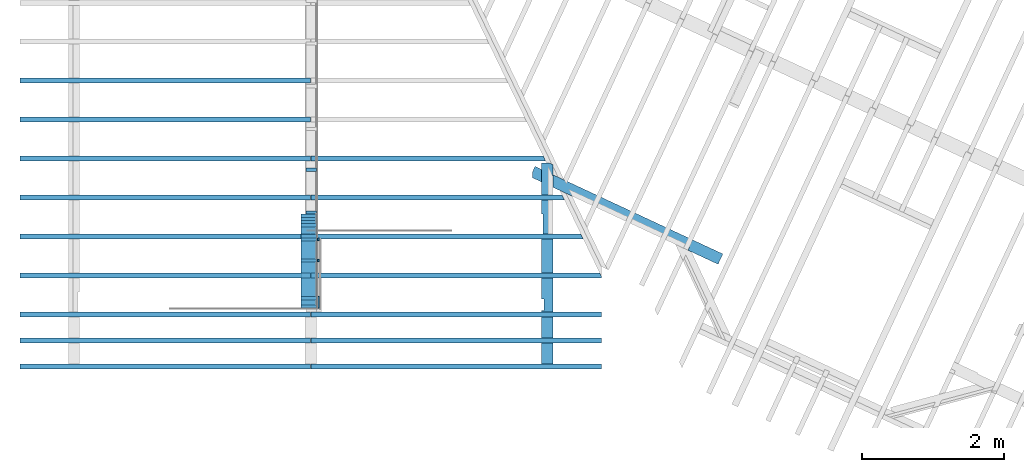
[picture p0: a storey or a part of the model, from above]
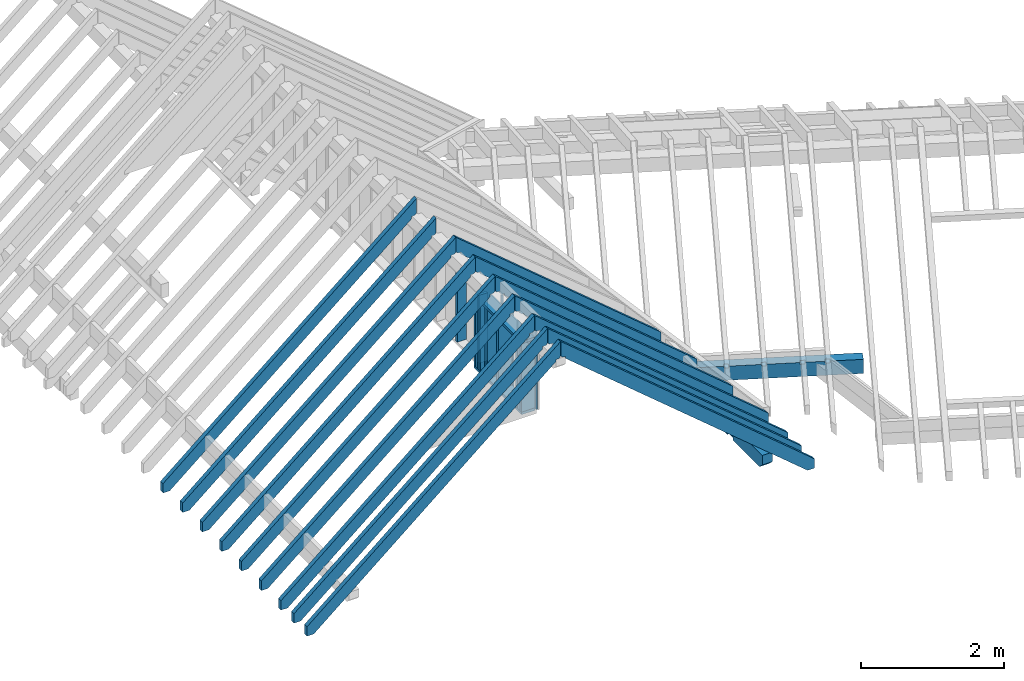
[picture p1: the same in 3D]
Properties of the parts of a building model (IFC2X3), part 1 of 4

# File
Description: ViewDefinition [CoordinationView_V2.0]
File name: Export_V2
Time: 2022-12-03T16:46:10
Made in: cadwork

# IfcSite
RefElevation: 0 m

# IfcBuildingStorey (4)
In: Building 1
Elevation: 0 m
Name
Comble et couverture
Dalle
Premier Etage
Rez de chaussée

# IfcBeam (12)
Material: NH II
BaseQuantities - GrossWeight: 0; NetWeight: 0
Pset cadwork 3d - Group: Charpente
Name | In | Width (m) | Height (m) | Length (m) | CrossSectionArea (m2) | OuterfaceArea (m2) | TotalSurfaceArea (m2) | GrossVolume (m3) | NetVolume (m3) | SubGroup | Prod_Nb
Blochet | Premier Etage | 0.092 | 0.192 | 1.5533 | 3.3915 | 0.8393 | 0.8747 | 0.0274 | 0.0259 | F01 | 1504
Solive balcon | Rez de chaussée | 0.092 | 0.192 | 1.0028 | 3.3915 | 0.5696 | 0.6049 | 0.0182 | 0.0177 | Balcon | 1508
2 x Solive balcon | Rez de chaussée | 0.092 | 0.192 | 2.862 | 3.3915 | 1.6256 | 1.6609 | 0.0515 | 0.0506 | Balcon | 1509
Solive balcon | Rez de chaussée | 0.2 | 0.2 | 1.1768 | 8 | 0.9042 | 0.9842 | 0.0482 | 0.0435 | Balcon | 1510
Poteau | Rez de chaussée | 0.2 | 0.2 | 2.605 | 8 | 2.084 | 2.164 | 0.106 | 0.1042 | Balcon | 1507
Blochet | Premier Etage | 0.092 | 0.192 | 1.5533 | 3.3915 | 0.8367 | 0.872 | 0.0274 | 0.0257 | F01 | 1504
Poteau | Rez de chaussée | 0.2 | 0.2 | 2.3756 | 8 | 1.8567 | 1.9367 | 0.095 | 0.088 | Ferme Garage | 1520
Solive balcon | Rez de chaussée | 0.2 | 0.2 | 3.656 | 8 | 2.8826 | 2.9626 | 0.1462 | 0.1422 | Balcon | 1511
Poteau | Premier Etage | 0.1 | 0.2 | 1.6441 | 4 | 0.9702 | 1.0102 | 0.0329 | 0.0319 | F01 | 1505
Poinçon | Rez de chaussée | 0.16 | 0.16 | 2.7152 | 4.096 | 1.7108 | 1.762 | 0.0695 | 0.0674 | Ferme Garage | 1518
Poteau | Rez de chaussée | 0.2 | 0.2 | 2.3756 | 8 | 1.8567 | 1.9367 | 0.095 | 0.088 | Ferme Garage | 1519

# IfcBuildingElementProxy (122)
Material: NH II
BaseQuantities - Width: 0 m; CrossSectionArea: 0 m2; GrossVolume: 0 m3; GrossWeight: 0; NetWeight: 0
Name | In | Height (m) | Length (m) | OuterfaceArea (m2) = TotalSurfaceArea (m2) | NetVolume (m3) | Group
Surf_doubl_mur_Etage | Premier Etage | 2.894 | 3.88 | 7.715 | 0.0077 | MURS ETAGE
Surf_doubl_mur_RDC | Rez de chaussée | 1.8334 | 0.28 | 0.5133 | 0.0005 | MURS RDC
Surf_doubl_mur_RDC | Rez de chaussée | 0.9327 | 0.152 | 0.1418 | 0.0001 | MURS RDC
Surf_doubl_mur_RDC | Rez de chaussée | 0.18 | 1.1 | 0.198 | 0.0002 | MURS RDC
Surf_doubl_refend_RDC | Rez de chaussée | 1.7023 | 2.8 | 4.7665 | 0.0048 | MURS RDC
Surf_rampant isolé | Comble et couverture | 4.8508 | 4.4463 | 16.2012 | 0.0162
Surf_doubl_mur_RDC | Rez de chaussée | 2.894 | 2.248 | 4.513 | 0.0045 | MURS RDC
Surf_doubl_mur_RDC | Rez de chaussée | 3.2344 | 2.248 | 3.1855 | 0.0032 | MURS RDC
Surf_plancher | Premier Etage | 9.0638 | 14.1239 | 82.3637 | 0.0824 | Plancher étage
Surf_doubl_mur_RDC | Rez de chaussée | 0.8282 | 3.6116 | 2.7932 | 0.0028 | MURS RDC
Surf_doubl_mur_RDC | Rez de chaussée | 5.0771 | 2.8 | 13.4331 | 0.0134 | MURS RDC
Surf_doubl_mur_RDC | Rez de chaussée | 0.4294 | 2.8 | 1.2023 | 0.0012 | MURS RDC
Surf_doubl_refend_RDC | Rez de chaussée | 1.5736 | 2.8 | 4.4061 | 0.0044 | MURS RDC
2 x Surf_doubl_refend_RDC | Rez de chaussée | 2.6107 | 2.8 | 7.3098 | 0.0073 | MURS RDC
Surf_doubl_refend_RDC | Rez de chaussée | 3.0682 | 2.8 | 8.5909 | 0.0086 | MURS RDC
Surf_rampant isolé | Comble et couverture | 4.851 | 4.0712 | 12.7698 | 0.0128
Surf_doubl_mur_Etage | Premier Etage | 5.1796 | 2.7561 | 10.3865 | 0.0104 | MURS ETAGE
Surf_doubl_mur_RDC | Rez de chaussée | 1.2715 | 0.325 | 0.4132 | 0.0004 | MURS RDC
Surf_doubl_mur_RDC | Rez de chaussée | 1.6903 | 0.152 | 0.2569 | 0.0003 | MURS RDC
Surf_doubl_mur_RDC | Rez de chaussée | 3.171 | 2.8 | 7.1393 | 0.0071 | MURS RDC
Surf_doubl_mur_Etage | Premier Etage | 1.2715 | 1.1631 | 1.1788 | 0.0012 | MURS ETAGE
Surf_doubl_mur_RDC | Rez de chaussée | 0.552 | 1.5291 | 0.7561 | 0.0008 | MURS RDC
Surf_doubl_mur_Etage | Premier Etage | 9.0512 | 1.3586 | 12.2969 | 0.0123 | MURS ETAGE
Surf_doubl_mur_RDC | Rez de chaussée | 2.2245 | 2.248 | 3.7389 | 0.0037 | MURS RDC
surf_placo | Premier Etage | 1.9838 | 2.3904 | 3.7124 | 0.0037 | MURS ETAGE
2 x Surf_doubl_mur_RDC | Rez de chaussée | 0.1385 | 0.4 | 0.0554 | 0.0001 | MURS RDC
Surf_doubl_mur_RDC | Rez de chaussée | 0.3275 | 1.1 | 0.3602 | 0.0004 | MURS RDC
2 x Surf_doubl_mur_RDC | Rez de chaussée | 0.0844 | 1.923 | 0.1624 | 0.0002 | MURS RDC
Surf_doubl_mur_RDC | Rez de chaussée | 4.519 | 0.6723 | 3.0382 | 0.003 | MURS RDC
Surf_rampant isolé | Comble et couverture | 3.1634 | 3.2996 | 8.223 | 0.0082
2 x Surf_doubl_refend_RDC | Rez de chaussée | 1.3947 | 2.8 | 3.9052 | 0.0039 | MURS RDC
2 x Surf_doubl_mur_RDC | Rez de chaussée | 0.1385 | 1.923 | 0.2664 | 0.0003 | MURS RDC
surf_placo | Premier Etage | 1.9838 | 3.9546 | 7.845 | 0.0078 | MURS ETAGE
2 x Surf_doubl_refend_RDC | Rez de chaussée | 0.277 | 2.8 | 0.7756 | 0.0008 | MURS RDC
Surf_doubl_mur_RDC | Rez de chaussée | 2.3298 | 1.923 | 4.4802 | 0.0045 | MURS RDC
Surf_doubl_mur_RDC | Rez de chaussée | 0.8282 | 0.152 | 0.1259 | 0.0001 | MURS RDC
Surf_rampant isolé | Comble et couverture | 4.3185 | 2.4595 | 8.3437 | 0.0083
Surf_doubl_mur_RDC | Rez de chaussée | 0.18 | 0.325 | 0.0585 | 0.0001 | MURS RDC
Surf_doubl_mur_RDC | Rez de chaussée | 0.7186 | 2.248 | 1.062 | 0.0011 | MURS RDC
Surf_doubl_mur_RDC | Rez de chaussée | 2.2947 | 0.152 | 0.3488 | 0.0003 | MURS RDC
Surf_doubl_refend_RDC | Rez de chaussée | 1.0276 | 2.8 | 2.8773 | 0.0029 | MURS RDC
Surf_doubl_mur_RDC | Rez de chaussée | 1.0637 | 3.6854 | 3.5148 | 0.0035 | MURS RDC
Surf_doubl_mur_RDC | Rez de chaussée | 1.9672 | 0.325 | 0.6394 | 0.0006 | MURS RDC
Surf_doubl_mur_RDC | Rez de chaussée | 1.7489 | 1.109 | 0.28 | 0.0003 | MURS RDC
Surf_doubl_mur_RDC | Rez de chaussée | 0.9327 | 0.325 | 0.3031 | 0.0003 | MURS RDC
Surf_doubl_mur_RDC | Rez de chaussée | 0.18 | 2.323 | 0.418 | 0.0004 | MURS RDC
Surf_doubl_mur_RDC | Rez de chaussée | 0.4632 | 1.2104 | 0.5606 | 0.0006 | MURS RDC
Surf_doubl_mur_RDC | Rez de chaussée | 0.2762 | 4.0116 | 1.0861 | 0.0011 | MURS RDC
Surf_doubl_mur_RDC | Rez de chaussée | 1.2271 | 3.5334 | 3.2899 | 0.0033 | MURS RDC
Surf_doubl_mur_RDC | Rez de chaussée | 0.3275 | 0.325 | 0.1064 | 0.0001 | MURS RDC
surf_placo | Premier Etage | 3.058 | 3.9546 | 7.4298 | 0.0074 | MURS ETAGE
surf_placo | Premier Etage | 3.058 | 3.9546 | 6.4139 | 0.0064 | MURS ETAGE
2 x Surf_doubl_mur_RDC | Rez de chaussée | 0.0844 | 0.4 | 0.0338 | 0 | MURS RDC
Surf_doubl_mur_RDC | Rez de chaussée | 1.1008 | 2.248 | 2.4747 | 0.0025 | MURS RDC
Surf_doubl_mur_RDC | Rez de chaussée | 0.3384 | 0.325 | 0.11 | 0.0001 | MURS RDC
Surf_doubl_mur_RDC | Rez de chaussée | 0.9492 | 1.923 | 1.8253 | 0.0018 | MURS RDC
Surf_doubl_mur_RDC | Rez de chaussée | 0.4632 | 1.923 | 0.8907 | 0.0009 | MURS RDC
Surf_rampant isolé | Comble et couverture | 7.908 | 4.3782 | 32.1627 | 0.0322
Surf_doubl_mur_RDC | Rez de chaussée | 0.9327 | 1.923 | 1.7936 | 0.0018 | MURS RDC
Surf_doubl_mur_RDC | Rez de chaussée | 0.552 | 1.923 | 1.0615 | 0.0011 | MURS RDC
Surf_doubl_mur_RDC | Rez de chaussée | 1.5214 | 2.248 | 2.775 | 0.0028 | MURS RDC
Surf_doubl_mur_RDC | Rez de chaussée | 0.1515 | 1.923 | 0.2914 | 0.0003 | MURS RDC
Surf_doubl_mur_RDC | Rez de chaussée | 3.2494 | 2.248 | 6.2115 | 0.0062 | MURS RDC
Surf_doubl_mur_RDC | Rez de chaussée | 0.2868 | 2.248 | 0.4353 | 0.0004 | MURS RDC
Surf_doubl_mur_RDC | Rez de chaussée | 3.26 | 2.248 | 2.9849 | 0.003 | MURS RDC
Surf_doubl_mur_RDC | Rez de chaussée | 0.3272 | 1.923 | 0.6293 | 0.0006 | MURS RDC
Surf_doubl_refend_RDC | Rez de chaussée | 0.2832 | 2.8 | 0.793 | 0.0008 | MURS RDC
2 x Surf_doubl_refend_RDC | Rez de chaussée | 2.4835 | 2.8 | 6.9539 | 0.007 | MURS RDC
Surf_doubl_refend_RDC | Rez de chaussée | 3.171 | 2.8 | 8.8788 | 0.0089 | MURS RDC
Surf_doubl_mur_RDC | Rez de chaussée | 1.9188 | 2.8 | 4.2796 | 0.0043 | MURS RDC
Surf_doubl_refend_RDC | Rez de chaussée | 2.1486 | 2.8 | 6.016 | 0.006 | MURS RDC
Surf_doubl_mur_RDC | Rez de chaussée | 0.0844 | 0.278 | 0.0215 | 0 | MURS RDC
Surf_doubl_mur_RDC | Rez de chaussée | 0.1385 | 1.7421 | 0.2362 | 0.0002 | MURS RDC
Surf_doubl_mur_RDC | Rez de chaussée | 1.8334 | 1.1548 | 0.2936 | 0.0003 | MURS RDC
Surf_doubl_mur_RDC | Rez de chaussée | 0.0844 | 0.2059 | 0.0135 | 0 | MURS RDC
Surf_doubl_mur_RDC | Rez de chaussée | 0.1385 | 0.2353 | 0.0222 | 0 | MURS RDC
Surf_rampant isolé | Comble et couverture | 4.4009 | 4.0712 | 12.4025 | 0.0124
2 x Surf_doubl_refend_RDC | Rez de chaussée | 0.202 | 2.8 | 0.5656 | 0.0006 | MURS RDC
Surf_doubl_mur_RDC | Rez de chaussée | 4.519 | 0.152 | 0.6869 | 0.0007 | MURS RDC
2 x Surf_doubl_mur_RDC | Rez de chaussée | 1.9719 | 0.152 | 0.2997 | 0.0003 | MURS RDC
Surf_doubl_mur_RDC | Rez de chaussée | 0.2606 | 2.9953 | 0.7804 | 0.0008 | MURS RDC
Surf_rampant isolé | Comble et couverture | 2.9828 | 2.8104 | 2.5966 | 0.0026
Surf_rampant isolé | Comble et couverture | 1.8478 | 2.8105 | 2.5966 | 0.0026
2 x Surf_doubl_refend_RDC | Rez de chaussée | 1.9838 | 2.8 | 5.5546 | 0.0056 | MURS RDC
Surf_doubl_refend_RDC | Rez de chaussée | 0.4124 | 2.8 | 1.1546 | 0.0012 | MURS RDC
Surf_doubl_mur_Etage | Premier Etage | 2.2947 | 0.6912 | 1.5861 | 0.0016 | MURS ETAGE
Surf_doubl_mur_Etage | Premier Etage | 1.5494 | 1.2662 | 1.5164 | 0.0015 | MURS ETAGE
Surf_doubl_mur_Etage | Premier Etage | 2.2245 | 1.2662 | 2.8166 | 0.0028 | MURS ETAGE
Surf_doubl_mur_Etage | Premier Etage | 0.2868 | 1.4515 | 0.3818 | 0.0004 | MURS ETAGE
Surf_doubl_mur_Etage | Premier Etage | 0.1764 | 1.4016 | 0.2434 | 0.0002 | MURS ETAGE
Surf_doubl_mur_Etage | Premier Etage | 6.229 | 4.0335 | 16.9842 | 0.017 | MURS ETAGE
Surf_rampant isolé | Comble et couverture | 7.908 | 4.554 | 22.9358 | 0.0229
2 x Surf_doubl_refend_Etage | Premier Etage | 3.103 | 3.9546 | 7.5511 | 0.0076 | MURS ETAGE
Surf_doubl_refend_Etage | Premier Etage | 6.2532 | 3.9546 | 21.217 | 0.0212 | MURS ETAGE
Surf_doubl_mur_Etage | Premier Etage | 7.354 | 1.4517 | 10.6756 | 0.0107 | MURS ETAGE
Surf_doubl_refend_Etage | Premier Etage | 6.2532 | 3.943 | 21.1444 | 0.0211 | MURS ETAGE
Surf_doubl_mur_Etage | Premier Etage | 0.7186 | 1.4515 | 1.0431 | 0.001 | MURS ETAGE
Surf_doubl_mur_Etage | Premier Etage | 3.26 | 4.0335 | 9.1627 | 0.0092 | MURS ETAGE
Surf_doubl_mur_Etage | Premier Etage | 1.1008 | 3.88 | 4.2712 | 0.0043 | MURS ETAGE
Surf_doubl_refend_Etage | Premier Etage | 5.001 | 2.7561 | 8.4138 | 0.0084 | MURS ETAGE
Surf_doubl_refend_Etage | Premier Etage | 5.5345 | 2.7561 | 9.4741 | 0.0095 | MURS ETAGE
Surf_rampant isolé | Comble et couverture | 5.3117 | 2.4595 | 10.7866 | 0.0108
Surf_doubl_refend_RDC | Rez de chaussée | 3.7651 | 2.8 | 10.5424 | 0.0105 | MURS RDC
Surf_doubl_refend_RDC | Rez de chaussée | 7.0648 | 2.8 | 19.7815 | 0.0198 | MURS RDC
Surf_doubl_mur_RDC | Rez de chaussée | 2.1569 | 2.323 | 5.0105 | 0.005 | MURS RDC
Surf_doubl_mur_RDC | Rez de chaussée | 0.0371 | 2.323 | 0.0863 | 0.0001 | MURS RDC
Surf_doubl_mur_RDC | Rez de chaussée | 1.2715 | 0.152 | 0.1933 | 0.0002 | MURS RDC
Surf_doubl_mur_RDC | Rez de chaussée | 1.12 | 0.152 | 0.1702 | 0.0002 | MURS RDC
Surf_doubl_mur_RDC | Rez de chaussée | 2.4175 | 0.152 | 0.3675 | 0.0004 | MURS RDC
Surf_doubl_mur_RDC | Rez de chaussée | 0.0371 | 0.152 | 0.0056 | 0 | MURS RDC

# IfcColumn, Poteau
In: Premier Etage
Material: NH II
BaseQuantities - Width: 0.2 m; Height: 0.2 m; Length: 1.4178 m; CrossSectionArea: 8 m2; OuterfaceArea: 1.0491 m2; TotalSurfaceArea: 1.1291 m2; GrossVolume: 0.0585 m3; NetVolume: 0.0493 m3; GrossWeight: 0; NetWeight: 0
Pset cadwork 3d - Group: Charpente; SubGroup: F01; Prod_Nb: 1506

# IfcCurtainWall (113)
Name | In | Material
71 x Escalier | Rez de chaussée | NH II
20 x Pare-pluie | Rez de chaussée | pare-pluie
18 x Pare-pluie | Premier Etage | pare-pluie
4 x Pare-pluie | Comble et couverture | pare-pluie

# IfcFooting (3)
Material: Béton
BaseQuantities - Height: 0.2 m
Pset cadwork 3d - Group: Maçonnerie
Name | In | Width (m) | Length (m) | CrossSectionArea (m2) | OuterfaceArea (m2) | TotalSurfaceArea (m2) | GrossVolume (m3) | NetVolume (m3) | GrossWeight | NetWeight
Dalle | Rez de chaussée | 6.28 | 5.3065 | 251.2 | 68.7722 | 71.2842 | 6.665 | 6.665 | 159.959 | 159.959 | Pset cadwork 3d - SubGroup: Garage
Dalle | Dalle | 18.5542 | 9.5894 | 742.167 | 237.702 | 245.124 | 35.5846 | 23.4288 | 854.03 | 562.292
Dalle | Rez de chaussée | 0.4 | 0.4 | 16 | 0.48 | 0.64 | 0.032 | 0.032 | 0.768 | 0.768

# IfcMember (1988)
Name | In | Material | Width (m) | Height (m) | Length (m) | CrossSectionArea (m2) | OuterfaceArea (m2) | TotalSurfaceArea (m2) | GrossVolume (m3) | NetVolume (m3) | GrossWeight | NetWeight | SKU | Group | SubGroup | Prod_Nb
5 x latte 27/40 | Premier Etage | Epicéa C24 | 0.04 | 0.024 | 0.6979 | 0.023 | 0.0893 | 0.0912 | 0.0007 | 0.0007 | 0.0028 | 0.0028 | 0 | MURS ETAGE | OB125 | 754
2 x Lisse basse | Premier Etage | Epicéa C24 | 0.045 | 0.145 | 2.1858 | 0.9461 | 0.8306 | 0.8436 | 0.0143 | 0.0143 | 0.0599 | 0.0599 | 0 | Plancher étage | ETA | 27
2 x Chevron | Comble et couverture | NH II | 0.07 | 0.192 | 5.4036 | 2.5805 | 2.7812 | 2.8081 | 0.0726 | 0.0712 | 0 | 0 |  | Charpente | Chevrons | 2091
7 x Montant | Premier Etage | Epicéa C24 | 0.045 | 0.22 | 0.5729 | 2.178 | 0.3036 | 0.3234 | 0.0057 | 0.0057 | 0.0238 | 0.0238 | 0 | MURS ETAGE | OB125 | 528
17 x latte 27/40 | Rez de chaussée | Epicéa C24 | 0.04 | 0.024 | 2.698 | 0.023 | 0.3453 | 0.3473 | 0.0026 | 0.0026 | 0.0109 | 0.0109 | 0 | MURS RDC | OB01 | 679
Solive | Premier Etage | NH II | 0.092 | 0.22 | 8.4685 | 4.4528 | 5.273 | 5.3135 | 0.1724 | 0.171 | 0 | 0 |  | Plancher étage | Solivage_220 | 1064
9 x Montant | Premier Etage | Epicéa C24 | 0.045 | 0.22 | 2.6405 | 2.178 | 1.3994 | 1.4192 | 0.0261 | 0.0261 | 0.1098 | 0.1098 | 0 | MURS ETAGE | OB13 | 248
latte 27/40 | Premier Etage | Epicéa C24 | 0.04 | 0.024 | 1.0505 | 0.023 | 0.1345 | 0.1364 | 0.001 | 0.001 | 0.0042 | 0.0042 | 0 | MURS COMBLE | OB12 | 612
15 x Montant | Premier Etage | Epicéa C24 | 0.045 | 0.145 | 2.6405 | 0.9461 | 1.0034 | 1.0164 | 0.0172 | 0.0172 | 0.0724 | 0.0724 | 0 | MURS ETAGE | OB129 | 252
4 x Couvre joint | Rez de chaussée | NH II | 0.027 | 0.105 | 3.4036 | 0.2977 | 0.8707 | 0.8764 | 0.0096 | 0.0092 | 0 | 0 |  | Couvre-joint
Panne | Comble et couverture | NH II | 0.16 | 0.2 | 5.1216 | 6.4 | 3.6585 | 3.7225 | 0.1639 | 0.1609 | 0 | 0 |  | Charpente | Toiture mezzanine | 1530
5 x Montant | Rez de chaussée | Epicéa C24 | 0.045 | 0.22 | 2.478 | 2.178 | 1.3133 | 1.3331 | 0.0245 | 0.0245 | 0.103 | 0.103 | 0 | MURS RDC | OB04 | 85
9 x Montant | Rez de chaussée | Epicéa C24 | 0.045 | 0.22 | 2.45 | 2.178 | 1.2985 | 1.3183 | 0.0243 | 0.0243 | 0.1019 | 0.1019 | 0 | MURS RDC | OB010 | 347
5 x latte 27/40 | Rez de chaussée | Epicéa C24 | 0.04 | 0.024 | 0.443 | 0.023 | 0.0567 | 0.0586 | 0.0004 | 0.0004 | 0.0018 | 0.0018 | 0 | MURS RDC | OB020 | 630
Montant | Premier Etage | Epicéa C24 | 0.045 | 0.145 | 0.87 | 0.9461 | 0.3306 | 0.3436 | 0.0057 | 0.0057 | 0.0238 | 0.0238 | 0 | MURS ETAGE | OB131 | 499
24 x Montant | Rez de chaussée | Epicéa C24 | 0.045 | 0.22 | 2.478 | 2.178 | 1.3133 | 1.3331 | 0.0245 | 0.0245 | 0.103 | 0.103 | 0 | MURS RDC | OB020 | 153
5 x Montant | Premier Etage | Epicéa C24 | 0.045 | 0.22 | 0.2045 | 2.178 | 0.1084 | 0.1282 | 0.002 | 0.002 | 0.0085 | 0.0085 | 0 | MURS ETAGE | OB14 | 89
9 x Montant | Rez de chaussée | Epicéa C24 | 0.045 | 0.22 | 0.73 | 2.178 | 0.3869 | 0.4067 | 0.0072 | 0.0072 | 0.0304 | 0.0304 | 0 | MURS RDC | OB01 | 260
23 x Montant | Rez de chaussée | Epicéa C24 | 0.045 | 0.22 | 2.478 | 2.178 | 1.3133 | 1.3331 | 0.0245 | 0.0245 | 0.103 | 0.103 | 0 | MURS RDC | OB01 | 262
Montant | Premier Etage | Epicéa C24 | 0.045 | 0.22 | 0.7144 | 2.178 | 0.3679 | 0.3877 | 0.0071 | 0.0068 | 0.0297 | 0.0286 | 0 | MURS ETAGE | OB124 | 518
7 x Montant | Rez de chaussée | Epicéa C24 | 0.045 | 0.145 | 2.43 | 0.9461 | 0.9234 | 0.9364 | 0.0159 | 0.0159 | 0.0666 | 0.0666 | 0 | MURS RDC | OB025 | 202
Montant | Rez de chaussée | Epicéa C24 | 0.045 | 0.1286 | 2.665 | 0.7445 | 0.8887 | 0.9003 | 0.0154 | 0.0144 | 0.0648 | 0.0607 | 0 | MURS RDC | OB013 | 429
Montant | Premier Etage | Epicéa C24 | 0.045 | 0.22 | 0.9874 | 2.178 | 0.5164 | 0.5362 | 0.0098 | 0.0096 | 0.0411 | 0.0403 | 0 | MURS COMBLE | OB12 | 75
2 x latte 27/40 | Premier Etage | Epicéa C24 | 0.04 | 0.024 | 1.1361 | 0.023 | 0.1454 | 0.1473 | 0.0011 | 0.0011 | 0.0046 | 0.0046 | 0 | MURS ETAGE | OB123 | 745
5 x Montant | Rez de chaussée | Epicéa C24 | 0.045 | 0.22 | 0.24 | 2.178 | 0.1272 | 0.147 | 0.0024 | 0.0024 | 0.01 | 0.01 | 0 | MURS RDC | OB08 | 309
Chevron | Comble et couverture | NH II | 0.07 | 0.192 | 2.3318 | 2.5805 | 1.1547 | 1.1816 | 0.0313 | 0.0293 | 0 | 0 |  | Charpente | Chevrons | 2071
Montant | Rez de chaussée | Epicéa C24 | 0.045 | 0.178 | 2.935 | 1.4263 | 1.2603 | 1.2763 | 0.0235 | 0.0221 | 0.0988 | 0.0929 | 0 | MURS RDC | OB014 | 454
Montant | Premier Etage | Epicéa C24 | 0.045 | 0.22 | 1.4003 | 2.178 | 0.7352 | 0.755 | 0.0139 | 0.0137 | 0.0582 | 0.0574 | 0 | MURS COMBLE | OB12 | 76
7 x Montant | Rez de chaussée | Epicéa C24 | 0.045 | 0.22 | 2.67 | 2.178 | 1.4151 | 1.4349 | 0.0264 | 0.0264 | 0.111 | 0.111 | 0 | MURS RDC | OB08 | 314
2 x Enrayure | Dalle | NH II | 0.188 | 0.5 | 2.2539 | 47 | 2.9905 | 3.1785 | 0.2119 | 0.2025 | 0 | 0 |  | Maçonnerie
10 x Montant | Premier Etage | Epicéa C24 | 0.045 | 0.145 | 2.5593 | 0.9461 | 0.9725 | 0.9856 | 0.0167 | 0.0167 | 0.0701 | 0.0701 | 0 | MURS ETAGE | OB128 | 132
4 x latte 27/40 | Rez de chaussée | Epicéa C24 | 0.04 | 0.024 | 2.67 | 0.023 | 0.3418 | 0.3437 | 0.0026 | 0.0026 | 0.0108 | 0.0108 | 0 | MURS RDC | OB07 | 687
9 x Montant | Rez de chaussée | Epicéa C24 | 0.045 | 0.22 | 0.417 | 2.178 | 0.221 | 0.2408 | 0.0041 | 0.0041 | 0.0173 | 0.0173 | 0 | MURS RDC | OB01 | 259
2 x Montant | Comble et couverture | Epicéa C24 | 0.045 | 0.22 | 1.3208 | 2.178 | 0.7 | 0.7198 | 0.0131 | 0.0131 | 0.0549 | 0.0549 | 0 | MURS COMBLE | OB13 | 255
3 x Montant | Premier Etage | Epicéa C24 | 0.045 | 0.145 | 0.1783 | 0.9461 | 0.0678 | 0.0808 | 0.0012 | 0.0012 | 0.0049 | 0.0049 | 0 | MURS ETAGE | OB131 | 493
4 x Solive | Premier Etage | NH II | 0.07 | 0.192 | 0.3809 | 2.5805 | 0.1996 | 0.2265 | 0.0053 | 0.0051 | 0 | 0 |  | Plancher étage | Solivage_192 | 1022
3 x Montant | Rez de chaussée | Epicéa C24 | 0.045 | 0.145 | 2.45 | 0.9461 | 0.931 | 0.944 | 0.016 | 0.016 | 0.0671 | 0.0671 | 0 | MURS RDC | OB024 | 536
contre poutre | Premier Etage | NH II | 0.027 | 0.165 | 0.8587 | 0.7351 | 0.2944 | 0.3034 | 0.0038 | 0.0034 | 0 | 0 |  | Plancher étage
2 x latte 27/40 | Rez de chaussée | Epicéa C24 | 0.04 | 0.024 | 0.715 | 0.023 | 0.0915 | 0.0934 | 0.0007 | 0.0007 | 0.0029 | 0.0029 | 0 | MURS RDC | OB011 | 718
Montant | Premier Etage | Epicéa C24 | 0.012 | 0.22 | 0.4051 | 0.5808 | 0.188 | 0.1932 | 0.0011 | 0.0011 | 0.0045 | 0.0045 | 0 | MURS ETAGE | OB126 | 538
Montant | Premier Etage | Epicéa C24 | 0.045 | 0.1414 | 0.4736 | 0.8999 | 0.1635 | 0.1762 | 0.003 | 0.0026 | 0.0127 | 0.011 | 0 | MURS ETAGE | OB19 | 335
4 x Montant | Premier Etage | Epicéa C24 | 0.045 | 0.22 | 1.8448 | 2.178 | 0.9777 | 0.9975 | 0.0183 | 0.0183 | 0.0767 | 0.0767 | 0 | MURS ETAGE | OB127 | 177
latte 27/40 | Premier Etage | Epicéa C24 | 0.04 | 0.024 | 0.5515 | 0.023 | 0.0706 | 0.0725 | 0.0005 | 0.0005 | 0.0022 | 0.0022 | 0 | MURS COMBLE | OB14 | 625
Solive | Premier Etage | NH II | 0.07 | 0.192 | 0.3725 | 2.5805 | 0.1952 | 0.2221 | 0.0051 | 0.005 | 0 | 0 |  | Plancher étage | Solivage_192 | 1021
contre poutre | Premier Etage | NH II | 0.027 | 0.165 | 1.3492 | 0.7351 | 0.5181 | 0.527 | 0.006 | 0.006 | 0 | 0 |  | Plancher étage
Montant | Premier Etage | Epicéa C24 | 0.045 | 0.22 | 0.6367 | 2.178 | 0.3324 | 0.3522 | 0.0063 | 0.0062 | 0.0265 | 0.026 | 0 | MURS ETAGE | OB122 | 447
3 x Montant | Premier Etage | Epicéa C24 | 0.045 | 0.22 | 1.0511 | 2.178 | 0.5571 | 0.5769 | 0.0104 | 0.0104 | 0.0437 | 0.0437 | 0 | MURS ETAGE | OB127 | 169
Couvre joint | Rez de chaussée | NH II | 0.027 | 0.105 | 3.41 | 0.2977 | 0.8391 | 0.8448 | 0.0097 | 0.0086 | 0 | 0 |  | Couvre-joint
11 x Montant | Rez de chaussée | Epicéa C24 | 0.045 | 0.22 | 2.478 | 2.178 | 1.3133 | 1.3331 | 0.0245 | 0.0245 | 0.103 | 0.103 | 0 | MURS RDC | OB03 | 242
12 x Solive | Premier Etage | NH II | 0.092 | 0.22 | 0.3432 | 4.4528 | 0.2142 | 0.2547 | 0.0071 | 0.0069 | 0 | 0 |  | Plancher étage | Solivage_220 | 1045
Montant | Premier Etage | Epicéa C24 | 0.045 | 0.22 | 2.2698 | 2.178 | 1.1873 | 1.2071 | 0.0225 | 0.022 | 0.0944 | 0.0925 | 0 | MURS COMBLE | OB12 | 80
2 x latte 27/40 | Premier Etage | Epicéa C24 | 0.04 | 0.024 | 0.9027 | 0.023 | 0.1155 | 0.1175 | 0.0009 | 0.0009 | 0.0036 | 0.0036 | 0 | MURS ETAGE | OB127 | 646
6 x Montant | Rez de chaussée | Epicéa C24 | 0.045 | 0.22 | 1.926 | 2.178 | 1.0208 | 1.0406 | 0.0191 | 0.0191 | 0.0801 | 0.0801 | 0 | MURS RDC | OB01 | 261
latte 27/40 | Premier Etage | Epicéa C24 | 0.04 | 0.024 | 0.7094 | 0.023 | 0.0908 | 0.0927 | 0.0007 | 0.0007 | 0.0029 | 0.0029 | 0 | MURS COMBLE | OB12 | 611
Lisse basse traitée | Dalle | Epicéa C24 Traité | 0.045 | 0.22 | 1.4915 | 2.178 | 0.7438 | 0.7636 | 0.0148 | 0.0139 | 0 | 0 | 0 | MURS RDC | Ossature RDC | 12
10 x latte 27/40 | Rez de chaussée | Epicéa C24 | 0.04 | 0.024 | 2.67 | 0.023 | 0.3418 | 0.3437 | 0.0026 | 0.0026 | 0.0108 | 0.0108 | 0 | MURS RDC | OB015 | 741
Montant | Comble et couverture | Epicéa C24 | 0.045 | 0.145 | 1.0525 | 0.9461 | 0.3948 | 0.4078 | 0.0069 | 0.0067 | 0.0288 | 0.0283 | 0 | MURS COMBLE | OB128 | 138
latte 27/40 | Rez de chaussée | Epicéa C24 | 0.04 | 0.024 | 0.415 | 0.023 | 0.0531 | 0.055 | 0.0004 | 0.0004 | 0.0017 | 0.0017 | 0 | MURS RDC | OB015 | 739
3 x latte 27/40 | Rez de chaussée | Epicéa C24 | 0.04 | 0.024 | 1.047 | 0.023 | 0.134 | 0.1359 | 0.001 | 0.001 | 0.0042 | 0.0042 | 0 | MURS RDC | OB020 | 631
Lisse basse | Rez de chaussée | Epicéa C24 | 0.045 | 0.145 | 2.6107 | 0.9461 | 0.992 | 1.0051 | 0.017 | 0.017 | 0.0715 | 0.0715 | 0 | MURS RDC | OB026 | 490
2 x Montant | Premier Etage | Epicéa C24 | 0.045 | 0.22 | 0.2449 | 2.178 | 0.1298 | 0.1496 | 0.0024 | 0.0024 | 0.0102 | 0.0102 | 0 | MURS ETAGE | OB120 | 359
Lisse basse | Premier Etage | Epicéa C24 | 0.045 | 0.22 | 2.094 | 2.178 | 1.1098 | 1.1296 | 0.0207 | 0.0207 | 0.0871 | 0.0871 | 0 | Plancher étage | ETA | 39
Lisse basse | Rez de chaussée | Epicéa C24 | 0.045 | 0.22 | 0.5962 | 2.178 | 0.316 | 0.3358 | 0.0059 | 0.0059 | 0.0248 | 0.0248 | 0 | MURS RDC | OB016 | 491
2 x Montant | Rez de chaussée | Epicéa C24 | 0.045 | 0.22 | 2.17 | 2.178 | 1.1501 | 1.1699 | 0.0215 | 0.0215 | 0.0902 | 0.0902 | 0 | MURS RDC | OB04 | 84
Main courante | Premier Etage | NH II | 0.045 | 0.057 | 0.078 | 0.1462 | 0.0159 | 0.021 | 0.0002 | 0.0002 | 0 | 0 |  | Balcon Etage | balustrade | 5006
4 x Chevron | Comble et couverture | NH II | 0.07 | 0.192 | 3.6791 | 2.5805 | 1.8304 | 1.8573 | 0.0494 | 0.0463 | 0 | 0 |  | Charpente | Chevrons | 2112
3 x latte 27/40 | Rez de chaussée | Epicéa C24 | 0.04 | 0.024 | 0.547 | 0.023 | 0.07 | 0.0719 | 0.0005 | 0.0005 | 0.0022 | 0.0022 | 0 | MURS RDC | OB01 | 678
Montant | Premier Etage | Epicéa C24 | 0.045 | 0.22 | 0.278 | 2.178 | 0.1422 | 0.162 | 0.0028 | 0.0026 | 0.0116 | 0.0111 | 0 | MURS ETAGE | OB121 | 419
16 x Chevron | Comble et couverture | NH II | 0.07 | 0.192 | 5.4354 | 2.5805 | 2.7841 | 2.811 | 0.0731 | 0.0713 | 0 | 0 |  | Charpente | Chevrons | 2030
2 x latte 27/40 | Premier Etage | Epicéa C24 | 0.04 | 0.024 | 2.1655 | 0.023 | 0.2772 | 0.2791 | 0.0021 | 0.0021 | 0.0087 | 0.0087 | 0 | MURS ETAGE | OB127 | 660
4 x Balustre horizontale | Premier Etage | NH II | 0.027 | 0.165 | 1.2258 | 0.7351 | 0.4707 | 0.4796 | 0.0055 | 0.0055 | 0 | 0 |  | Balcon Etage | balustrade | 5001
Montant | Premier Etage | Epicéa C24 | 0.0322 | 0.22 | 0.3425 | 1.5577 | 0.1728 | 0.1869 | 0.0024 | 0.0024 | 0.0102 | 0.0102 | 0 | MURS ETAGE | OB127 | 156
Panne | Comble et couverture | NH II | 0.16 | 0.2 | 9.715 | 6.4 | 6.959 | 7.023 | 0.3109 | 0.3071 | 0 | 0 |  | Charpente | Toiture habitation | 1527
4 x Montant | Premier Etage | Epicéa C24 | 0.045 | 0.22 | 0.73 | 2.178 | 0.3869 | 0.4067 | 0.0072 | 0.0072 | 0.0304 | 0.0304 | 0 | MURS ETAGE | OB127 | 166
2 x latte 27/40 | Rez de chaussée | Epicéa C24 | 0.04 | 0.024 | 0.147 | 0.023 | 0.0188 | 0.0207 | 0.0001 | 0.0001 | 0.0006 | 0.0006 | 0 | MURS RDC | OB07 | 685
2 x latte 27/40 | Rez de chaussée | Epicéa C24 | 0.04 | 0.024 | 2.74 | 0.023 | 0.3507 | 0.3526 | 0.0026 | 0.0026 | 0.011 | 0.011 | 0 | MURS RDC | OB016 | 747
2 x Cache moineau | Comble et couverture | NH II | 0.07 | 0.192 | 0.4302 | 2.5805 | 0.2196 | 0.2465 | 0.0058 | 0.0056 | 0 | 0 |  | Chevrons | Toiture Salon | 2102
10 x Montant | Premier Etage | Epicéa C24 | 0.045 | 0.22 | 2.6405 | 2.178 | 1.3994 | 1.4192 | 0.0261 | 0.0261 | 0.1098 | 0.1098 | 0 | MURS ETAGE | OB127 | 182
Montant | Premier Etage | Epicéa C24 | 0.045 | 0.22 | 2.4876 | 2.178 | 1.3184 | 1.3382 | 0.0246 | 0.0246 | 0.1034 | 0.1034 | 0 | MURS ETAGE | OB18 | 319
Montant | Rez de chaussée | Epicéa C24 | 0.045 | 0.22 | 1.7489 | 2.178 | 0.9269 | 0.9467 | 0.0173 | 0.0173 | 0.0727 | 0.0727 | 0 | MURS RDC | OB012 | 408
3 x Montant | Premier Etage | Epicéa C24 | 0.045 | 0.22 | 0.6787 | 2.178 | 0.3458 | 0.3656 | 0.0067 | 0.0063 | 0.0282 | 0.0267 | 0 | MURS ETAGE | OB14 | 94
9 x Montant | Comble et couverture | Epicéa C24 | 0.045 | 0.22 | 1.16 | 2.178 | 0.6148 | 0.6346 | 0.0115 | 0.0115 | 0.0482 | 0.0482 | 0 | MURS COMBLE | OB13 | 254
3 x latte 27/40 | Premier Etage | Epicéa C24 | 0.04 | 0.024 | 1.1678 | 0.023 | 0.1495 | 0.1514 | 0.0011 | 0.0011 | 0.0047 | 0.0047 | 0 | MURS ETAGE | OB11 | 680
10 x latte 27/40 | Rez de chaussée | Epicéa C24 | 0.04 | 0.024 | 2.698 | 0.023 | 0.3453 | 0.3473 | 0.0026 | 0.0026 | 0.0109 | 0.0109 | 0 | MURS RDC | OB020 | 636
Montant | Premier Etage | Epicéa C24 | 0.045 | 0.22 | 0.2808 | 2.178 | 0.1488 | 0.1686 | 0.0028 | 0.0028 | 0.0117 | 0.0117 | 0 | MURS ETAGE | OB15 | 204
2 x latte 27/40 | Premier Etage | Epicéa C24 | 0.04 | 0.024 | 0.6579 | 0.023 | 0.0842 | 0.0861 | 0.0006 | 0.0006 | 0.0027 | 0.0027 | 0 | MURS ETAGE | OB125 | 753
7 x Cache moineau | Comble et couverture | NH II | 0.07 | 0.192 | 0.53 | 2.5805 | 0.2777 | 0.3046 | 0.0071 | 0.0071 | 0 | 0 |  | Chevrons | Toiture Salon | 2103
3 x Montant | Premier Etage | Epicéa C24 | 0.045 | 0.22 | 0.4622 | 2.178 | 0.245 | 0.2648 | 0.0046 | 0.0046 | 0.0192 | 0.0192 | 0 | MURS ETAGE | OB127 | 164
2 x Solive | Premier Etage | NH II | 0.07 | 0.192 | 0.242 | 2.5805 | 0.1268 | 0.1537 | 0.0033 | 0.0033 | 0 | 0 |  | Plancher étage | Solivage_192 | 1019
latte 27/40 | Rez de chaussée | Epicéa C24 | 0.04 | 0.024 | 2.4452 | 0.023 | 0.313 | 0.3149 | 0.0023 | 0.0023 | 0.0099 | 0.0099 | 0 | MURS RDC | OB020 | 633
Lisse basse | Rez de chaussée | Epicéa C24 | 0.045 | 0.22 | 1.3069 | 2.178 | 0.6927 | 0.7125 | 0.0129 | 0.0129 | 0.0543 | 0.0543 | 0 | MURS RDC | OB07 | 292
4 x Montant | Premier Etage | Epicéa C24 | 0.045 | 0.145 | 2.166 | 0.9461 | 0.8231 | 0.8361 | 0.0141 | 0.0141 | 0.0594 | 0.0594 | 0 | MURS ETAGE | OB129 | 251
Lisse basse | Rez de chaussée | Epicéa C24 | 0.045 | 0.145 | 1.6186 | 0.9461 | 0.6151 | 0.6281 | 0.0106 | 0.0106 | 0.0444 | 0.0444 | 0 | MURS RDC | OB024 | 535
Solive | Premier Etage | NH II | 0.092 | 0.22 | 5.8533 | 4.4528 | 3.6412 | 3.6817 | 0.1195 | 0.118 | 0 | 0 |  | Plancher étage | Solivage_220 | 1054
Montant | Premier Etage | Epicéa C24 | 0.045 | 0.22 | 1.4594 | 2.178 | 0.7578 | 0.7776 | 0.0144 | 0.014 | 0.0607 | 0.0588 | 0 | MURS ETAGE | OB12 | 63
4 x latte 27/40 | Rez de chaussée | Epicéa C24 | 0.04 | 0.024 | 2.67 | 0.023 | 0.3418 | 0.3437 | 0.0026 | 0.0026 | 0.0108 | 0.0108 | 0 | MURS RDC | OB06 | 682
3 x latte 27/40 | Rez de chaussée | Epicéa C24 | 0.04 | 0.024 | 0.124 | 0.023 | 0.0159 | 0.0178 | 0.0001 | 0.0001 | 0.0005 | 0.0005 | 0 | MURS RDC | OB04 | 614
latte 27/40 | Comble et couverture | Epicéa C24 | 0.165 | 0.024 | 1.3669 | 0.095 | 0.5167 | 0.5246 | 0.0054 | 0.0054 | 0.0227 | 0.0227 | 0 | MURS COMBLE | OB13 | 676
2 x Lisse basse traitée | Dalle | Epicéa C24 Traité | 0.045 | 0.22 | 1.0482 | 2.178 | 0.5556 | 0.5754 | 0.0104 | 0.0104 | 0 | 0 | 0 | MURS RDC | Ossature RDC | 10
Solive | Premier Etage | NH II | 0.07 | 0.192 | 0.4025 | 2.5805 | 0.2109 | 0.2378 | 0.0055 | 0.0054 | 0 | 0 |  | Plancher étage | Solivage_192 | 1024
4 x Montant | Premier Etage | Epicéa C24 | 0.045 | 0.145 | 1.0511 | 0.9461 | 0.3994 | 0.4125 | 0.0069 | 0.0069 | 0.0288 | 0.0288 | 0 | MURS ETAGE | OB130 | 221
2 x Montant | Premier Etage | Epicéa C24 | 0.045 | 0.145 | 3.103 | 0.9461 | 1.1791 | 1.1922 | 0.0202 | 0.0202 | 0.085 | 0.085 | 0 | MURS ETAGE | OB128 | 133
Montant | Rez de chaussée | Epicéa C24 | 0.045 | 0.22 | 2.2142 | 2.178 | 1.1735 | 1.1933 | 0.0219 | 0.0219 | 0.0921 | 0.0921 | 0 | MURS RDC | OB014 | 461
3 x latte 27/40 | Rez de chaussée | Epicéa C24 | 0.04 | 0.024 | 0.443 | 0.023 | 0.0567 | 0.0586 | 0.0004 | 0.0004 | 0.0018 | 0.0018 | 0 | MURS RDC | OB04 | 615
Montant | Premier Etage | Epicéa C24 | 0.045 | 0.22 | 0.1133 | 2.178 | 0.0601 | 0.0799 | 0.0011 | 0.0011 | 0.0047 | 0.0047 | 0 | MURS ETAGE | OB120 | 355
8 x Cache moineau | Comble et couverture | NH II | 0.07 | 0.22 | 0.4776 | 3.388 | 0.277 | 0.3078 | 0.0074 | 0.0074 | 0 | 0 |  | Chevrons | Toiture habitation | 2008
3 x Montant | Rez de chaussée | Epicéa C24 | 0.045 | 0.145 | 2.67 | 0.9461 | 1.0146 | 1.0276 | 0.0174 | 0.0174 | 0.0732 | 0.0732 | 0 | MURS RDC | OB022 | 118
3 x latte 27/40 | Premier Etage | Epicéa C24 | 0.04 | 0.024 | 0.653 | 0.023 | 0.0836 | 0.0855 | 0.0006 | 0.0006 | 0.0026 | 0.0026 | 0 | MURS ETAGE | OB12 | 604
Montant | Premier Etage | Epicéa C24 | 0.045 | 0.22 | 1.7576 | 2.178 | 0.9315 | 0.9513 | 0.0174 | 0.0174 | 0.0731 | 0.0731 | 0 | MURS COMBLE | OB14 | 113
8 x Montant | Rez de chaussée | Epicéa C24 | 0.045 | 0.22 | 2.67 | 2.178 | 1.4151 | 1.4349 | 0.0264 | 0.0264 | 0.111 | 0.111 | 0 | MURS RDC | OB017 | 525
Couvre joint | Rez de chaussée | NH II | 0.027 | 0.105 | 0.8111 | 0.2977 | 0.2141 | 0.2198 | 0.0023 | 0.0023 | 0 | 0 |  | Couvre-joint
Cache moineau | Comble et couverture | NH II | 0.07 | 0.22 | 0.8413 | 3.388 | 0.4093 | 0.4401 | 0.013 | 0.0105 | 0 | 0 |  | Chevrons | Toiture mezzanine | 2052
15 x Montant | Premier Etage | Epicéa C24 | 0.045 | 0.22 | 1.0828 | 2.178 | 0.5739 | 0.5937 | 0.0107 | 0.0107 | 0.045 | 0.045 | 0 | MURS ETAGE | OB11 | 265
6 x Montant | Premier Etage | Epicéa C24 | 0.045 | 0.145 | 0.4295 | 0.9461 | 0.1632 | 0.1762 | 0.0028 | 0.0028 | 0.0118 | 0.0118 | 0 | MURS ETAGE | OB129 | 249
2 x Montant | Rez de chaussée | Epicéa C24 | 0.045 | 0.145 | 2.288 | 0.9461 | 0.8694 | 0.8825 | 0.0149 | 0.0149 | 0.0627 | 0.0627 | 0 | MURS RDC | OB021 | 244
Enrayure | Dalle | NH II | 0.2 | 0.5 | 6.5952 | 50 | 9.2185 | 9.4185 | 0.6595 | 0.6454 | 0 | 0 |  | Maçonnerie
Montant | Premier Etage | Epicéa C24 | 0.045 | 0.22 | 3.8884 | 2.178 | 2.0608 | 2.0806 | 0.0385 | 0.0385 | 0.1617 | 0.1617 | 0 | MURS COMBLE | OB127 | 199
latte chantier | Rez de chaussée | Epicéa C24 | 0.04 | 0.024 | 1.0092 | 0.023 | 0.1292 | 0.1311 | 0.001 | 0.001 | 0.0041 | 0.0041 | 0 | MURS RDC | L2 | 824
latte 27/40 | Premier Etage | Epicéa C24 | 0.04 | 0.024 | 1.5011 | 0.023 | 0.1921 | 0.1941 | 0.0014 | 0.0014 | 0.0061 | 0.0061 | 0 | MURS COMBLE | OB12 | 613
6 x latte 27/40 | Rez de chaussée | Epicéa C24 | 0.04 | 0.024 | 2.74 | 0.023 | 0.3507 | 0.3526 | 0.0026 | 0.0026 | 0.011 | 0.011 | 0 | MURS RDC | OB017 | 752
2 x latte 27/40 | Premier Etage | Epicéa C24 | 0.04 | 0.024 | 0.2557 | 0.023 | 0.0327 | 0.0346 | 0.0002 | 0.0002 | 0.001 | 0.001 | 0 | MURS ETAGE | OB127 | 638
2 x Montant | Premier Etage | Epicéa C24 | 0.045 | 0.145 | 0.1183 | 0.9461 | 0.045 | 0.058 | 0.0008 | 0.0008 | 0.0032 | 0.0032 | 0 | MURS ETAGE | OB130 | 211
3 x Montant | Rez de chaussée | Epicéa C24 | 0.045 | 0.22 | 2.21 | 2.178 | 1.1713 | 1.1911 | 0.0219 | 0.0219 | 0.0919 | 0.0919 | 0 | MURS RDC | OB06 | 274
2 x Montant | Premier Etage | Epicéa C24 | 0.045 | 0.145 | 0.87 | 0.9461 | 0.3306 | 0.3436 | 0.0057 | 0.0057 | 0.0238 | 0.0238 | 0 | MURS ETAGE | OB129 | 250
Chevron | Comble et couverture | NH II | 0.07 | 0.192 | 1.445 | 2.5805 | 0.69 | 0.7169 | 0.0194 | 0.0174 | 0 | 0 |  | Charpente | Chevrons | 2066
Lisse basse | Rez de chaussée | Epicéa C24 | 0.045 | 0.145 | 3.059 | 0.9461 | 1.1624 | 1.1755 | 0.02 | 0.02 | 0.0838 | 0.0838 | 0 | MURS RDC | OB022 | 119
Montant | Rez de chaussée | Epicéa C24 | 0.045 | 0.22 | 1.64 | 2.178 | 0.8692 | 0.889 | 0.0162 | 0.0162 | 0.0682 | 0.0682 | 0 | MURS RDC | OB08 | 310
2 x Montant | Rez de chaussée | Epicéa C24 | 0.045 | 0.22 | 1.426 | 2.178 | 0.7558 | 0.7756 | 0.0141 | 0.0141 | 0.0593 | 0.0593 | 0 | MURS RDC | OB020 | 148
Montant | Premier Etage | Epicéa C24 | 0.045 | 0.22 | 0.278 | 2.178 | 0.1422 | 0.162 | 0.0028 | 0.0026 | 0.0116 | 0.0111 | 0 | MURS ETAGE | OB122 | 445
Montant | Premier Etage | Epicéa C24 | 0.045 | 0.22 | 0.8486 | 2.178 | 0.4498 | 0.4696 | 0.0084 | 0.0084 | 0.0353 | 0.0353 | 0 | MURS ETAGE | OB15 | 205
3 x latte 27/40 | Rez de chaussée | Epicéa C24 | 0.04 | 0.024 | 0.443 | 0.023 | 0.0567 | 0.0586 | 0.0004 | 0.0004 | 0.0018 | 0.0018 | 0 | MURS RDC | OB02 | 600
Lisse basse | Rez de chaussée | Epicéa C24 | 0.045 | 0.22 | 3.028 | 2.178 | 1.6048 | 1.6246 | 0.03 | 0.03 | 0.1259 | 0.1259 | 0 | MURS RDC | OB04 | 86
Montant | Premier Etage | Epicéa C24 | 0.045 | 0.22 | 1.5182 | 2.178 | 0.8046 | 0.8244 | 0.015 | 0.015 | 0.0631 | 0.0631 | 0 | MURS COMBLE | OB127 | 196
5 x Montant | Premier Etage | Epicéa C24 | 0.045 | 0.22 | 0.873 | 2.178 | 0.4627 | 0.4825 | 0.0086 | 0.0086 | 0.0363 | 0.0363 | 0 | MURS ETAGE | OB14 | 96
Chevron | Comble et couverture | NH II | 0.07 | 0.192 | 2.9047 | 2.5805 | 1.4307 | 1.4576 | 0.039 | 0.0363 | 0 | 0 |  | Charpente | Chevrons | 2018
6 x latte 27/40 | Rez de chaussée | Epicéa C24 | 0.04 | 0.024 | 2.698 | 0.023 | 0.3453 | 0.3473 | 0.0026 | 0.0026 | 0.0109 | 0.0109 | 0 | MURS RDC | OB02 | 602
Montant | Premier Etage | Epicéa C24 | 0.045 | 0.22 | 0.4884 | 2.178 | 0.2519 | 0.2717 | 0.0048 | 0.0046 | 0.0203 | 0.0195 | 0 | MURS COMBLE | OB14 | 108
latte chantier | Rez de chaussée | Epicéa C24 | 0.04 | 0.024 | 0.5086 | 0.023 | 0.0651 | 0.067 | 0.0005 | 0.0005 | 0.0021 | 0.0021 | 0 | MURS RDC | L2 | 823
3 x Montant | Rez de chaussée | Epicéa C24 | 0.045 | 0.145 | 1.8389 | 0.9461 | 0.6988 | 0.7118 | 0.012 | 0.012 | 0.0504 | 0.0504 | 0 | MURS RDC | OB013 | 430
3 x Montant | Premier Etage | Epicéa C24 | 0.045 | 0.22 | 0.4051 | 2.178 | 0.2147 | 0.2345 | 0.004 | 0.004 | 0.0168 | 0.0168 | 0 | MURS ETAGE | OB126 | 539
2 x Contrefiche | Rez de chaussée | NH II | 0.16 | 0.16 | 1.5694 | 4.096 | 0.9607 | 1.0119 | 0.042 | 0.0381 | 0 | 0 |  | Charpente | Ferme Garage | 1512
Montant | Premier Etage | Epicéa C24 | 0.045 | 0.22 | 2.327 | 2.178 | 1.2176 | 1.2374 | 0.023 | 0.0226 | 0.0968 | 0.0949 | 0 | MURS COMBLE | OB14 | 114
2 x Cache moineau | Comble et couverture | NH II | 0.07 | 0.192 | 0.3256 | 2.5805 | 0.1706 | 0.1975 | 0.0044 | 0.0044 | 0 | 0 |  | Chevrons | Toiture mezzanine | 2088
3 x latte 27/40 | Premier Etage | Epicéa C24 | 0.04 | 0.024 | 1.0436 | 0.023 | 0.1336 | 0.1355 | 0.001 | 0.001 | 0.0042 | 0.0042 | 0 | MURS ETAGE | OB16 | 684
3 x latte 27/40 | Premier Etage | Epicéa C24 | 0.04 | 0.024 | 0.04 | 0.023 | 0.0051 | 0.007 | 0 | 0 | 0.0002 | 0.0002 | 0 | MURS ETAGE | OB122 | 732
2 x Montant | Premier Etage | Epicéa C24 | 0.045 | 0.145 | 0.87 | 0.9461 | 0.3306 | 0.3436 | 0.0057 | 0.0057 | 0.0238 | 0.0238 | 0 | MURS ETAGE | OB130 | 220
Couvre joint | Rez de chaussée | NH II | 0.027 | 0.105 | 3.9386 | 0.2977 | 1.0355 | 1.0412 | 0.0112 | 0.0099 | 0 | 0 |  | Couvre-joint
Cache moineau | Comble et couverture | NH II | 0.07 | 0.22 | 0.4052 | 3.388 | 0.213 | 0.2438 | 0.0062 | 0.0051 | 0 | 0 |  | Chevrons | Toiture habitation | 2003
latte 27/40 | Premier Etage | Epicéa C24 | 0.04 | 0.024 | 0.7249 | 0.023 | 0.0928 | 0.0947 | 0.0007 | 0.0007 | 0.0029 | 0.0029 | 0 | MURS ETAGE | OB14 | 620
Chevron | Comble et couverture | NH II | 0.07 | 0.192 | 5.4355 | 2.5805 | 2.7842 | 2.811 | 0.0731 | 0.0713 | 0 | 0 |  | Charpente | Chevrons | 2032
11 x Montant | Rez de chaussée | Epicéa C24 | 0.045 | 0.145 | 2.67 | 0.9461 | 1.0146 | 1.0276 | 0.0174 | 0.0174 | 0.0732 | 0.0732 | 0 | MURS RDC | OB023 | 125
Montant | Premier Etage | Epicéa C24 | 0.045 | 0.22 | 1.2513 | 2.178 | 0.6581 | 0.6779 | 0.0124 | 0.0123 | 0.052 | 0.0515 | 0 | MURS ETAGE | OB122 | 449
Ceinture | Premier Etage | NH II | 0.092 | 0.22 | 1.6925 | 4.4528 | 0.9838 | 1.0242 | 0.0343 | 0.0309 | 0 | 0 |  | Plancher étage | Solivage_220 | 1040
2 x Montant | Premier Etage | Epicéa C24 | 0.045 | 0.22 | 1.6278 | 2.178 | 0.8627 | 0.8825 | 0.0161 | 0.0161 | 0.0677 | 0.0677 | 0 | MURS ETAGE | OB11 | 266
Montant | Rez de chaussée | Epicéa C24 | 0.045 | 0.22 | 0.2248 | 2.178 | 0.1191 | 0.1389 | 0.0022 | 0.0022 | 0.0093 | 0.0093 | 0 | MURS RDC | OB011 | 389
2 x latte 27/40 | Premier Etage | Epicéa C24 | 0.04 | 0.024 | 1.003 | 0.023 | 0.1284 | 0.1303 | 0.001 | 0.001 | 0.004 | 0.004 | 0 | MURS ETAGE | OB14 | 621
4 x Montant | Premier Etage | Epicéa C24 | 0.045 | 0.22 | 0.9186 | 2.178 | 0.4869 | 0.5067 | 0.0091 | 0.0091 | 0.0382 | 0.0382 | 0 | MURS ETAGE | OB15 | 206
3 x latte 27/40 | Premier Etage | Epicéa C24 | 0.04 | 0.024 | 0.04 | 0.023 | 0.0051 | 0.007 | 0 | 0 | 0.0002 | 0.0002 | 0 | MURS ETAGE | OB121 | 723
4 x latte 27/40 | Premier Etage | Epicéa C24 | 0.04 | 0.024 | 0.5086 | 0.023 | 0.0651 | 0.067 | 0.0005 | 0.0005 | 0.0021 | 0.0021 | 0 | MURS ETAGE | OB18 | 696
10 x Chevron | Comble et couverture | NH II | 0.07 | 0.165 | 4.2825 | 1.9058 | 1.9637 | 1.9868 | 0.0495 | 0.0481 | 0 | 0 |  | Charpente | Chevrons | 2001
2 x latte 27/40 | Rez de chaussée | Epicéa C24 | 0.04 | 0.024 | 0.415 | 0.023 | 0.0531 | 0.055 | 0.0004 | 0.0004 | 0.0017 | 0.0017 | 0 | MURS RDC | OB07 | 686
latte 27/40 | Premier Etage | Epicéa C24 | 0.04 | 0.024 | 0.7537 | 0.023 | 0.0965 | 0.0984 | 0.0007 | 0.0007 | 0.003 | 0.003 | 0 | MURS ETAGE | OB122 | 735
3 x Montant | Rez de chaussée | Epicéa C24 | 0.045 | 0.22 | 2.845 | 2.178 | 1.5079 | 1.5277 | 0.0282 | 0.0282 | 0.1183 | 0.1183 | 0 | MURS RDC | OB011 | 400
2 x latte 27/40 | Rez de chaussée | Epicéa C24 | 0.04 | 0.024 | 0.124 | 0.023 | 0.0159 | 0.0178 | 0.0001 | 0.0001 | 0.0005 | 0.0005 | 0 | MURS RDC | OB020 | 628
Montant | Premier Etage | Epicéa C24 | 0.045 | 0.22 | 1.4101 | 2.178 | 0.742 | 0.7618 | 0.014 | 0.0138 | 0.0586 | 0.0581 | 0 | MURS ETAGE | OB124 | 520
5 x Montant | Rez de chaussée | Epicéa C24 | 0.045 | 0.22 | 0.917 | 2.178 | 0.486 | 0.5058 | 0.0091 | 0.0091 | 0.0381 | 0.0381 | 0 | MURS RDC | OB020 | 146
3 x Montant | Rez de chaussée | Epicéa C24 | 0.045 | 0.22 | 2.45 | 2.178 | 1.2985 | 1.3183 | 0.0243 | 0.0243 | 0.1019 | 0.1019 | 0 | MURS RDC | OB09 | 331
Montant | Premier Etage | Epicéa C24 | 0.045 | 0.22 | 7.884 | 2.178 | 4.1785 | 4.1983 | 0.0781 | 0.0781 | 0.3278 | 0.3278 | 0 | MURS ETAGE | OB11 | 268
latte 27/40 | Premier Etage | Epicéa C24 | 0.04 | 0.024 | 0.9835 | 0.023 | 0.1259 | 0.1278 | 0.0009 | 0.0009 | 0.004 | 0.004 | 0 | MURS COMBLE | OB127 | 664
Cache moineau | Comble et couverture | NH II | 0.07 | 0.192 | 0.5528 | 2.5805 | 0.2897 | 0.3166 | 0.0074 | 0.0074 | 0 | 0 |  | Chevrons | Toiture mezzanine | 2049
2 x Cache moineau | Comble et couverture | NH II | 0.07 | 0.192 | 0.3254 | 2.5805 | 0.1589 | 0.1858 | 0.0044 | 0.004 | 0 | 0 |  | Chevrons | Toiture Salon | 2099
latte 27/40 | Premier Etage | Epicéa C24 | 0.04 | 0.024 | 1.8105 | 0.023 | 0.2317 | 0.2337 | 0.0017 | 0.0017 | 0.0073 | 0.0073 | 0 | MURS ETAGE | OB127 | 655
4 x Montant | Premier Etage | Epicéa C24 | 0.045 | 0.22 | 2.6405 | 2.178 | 1.3994 | 1.4192 | 0.0261 | 0.0261 | 0.1098 | 0.1098 | 0 | MURS ETAGE | OB14 | 104
Montant | Premier Etage | Epicéa C24 | 0.045 | 0.22 | 2.1907 | 2.178 | 1.1541 | 1.1739 | 0.0217 | 0.0215 | 0.0911 | 0.0903 | 0 | MURS ETAGE | OB12 | 67
Solive | Premier Etage | NH II | 0.07 | 0.192 | 0.2722 | 2.5805 | 0.1426 | 0.1695 | 0.0038 | 0.0037 | 0 | 0 |  | Plancher étage | Solivage_192 | 1020
4 x Couvre joint | Rez de chaussée | NH II | 0.027 | 0.105 | 3.5929 | 0.2977 | 0.891 | 0.8966 | 0.0102 | 0.0089 | 0 | 0 |  | Couvre-joint
latte chantier | Rez de chaussée | Epicéa C24 | 0.04 | 0.024 | 1.2078 | 0.023 | 0.1546 | 0.1565 | 0.0012 | 0.0012 | 0.0049 | 0.0049 | 0 | MURS RDC | A2 | 801
Solive | Premier Etage | NH II | 0.07 | 0.192 | 0.3802 | 2.5805 | 0.1992 | 0.2261 | 0.0052 | 0.0051 | 0 | 0 |  | Plancher étage | Solivage_192 | 1023
Lisse basse | Rez de chaussée | Epicéa C24 | 0.045 | 0.145 | 3.7651 | 0.9461 | 1.4307 | 1.4438 | 0.0246 | 0.0246 | 0.1032 | 0.1032 | 0 | MURS RDC | OB023 | 126
Montant | Premier Etage | Epicéa C24 | 0.045 | 0.22 | 0.2671 | 2.178 | 0.1346 | 0.1544 | 0.0026 | 0.0025 | 0.0111 | 0.0103 | 0 | MURS COMBLE | OB12 | 72
Montant | Premier Etage | Epicéa C24 | 0.045 | 0.22 | 1.74 | 2.178 | 0.9152 | 0.935 | 0.0172 | 0.017 | 0.0723 | 0.0716 | 0 | MURS ETAGE | OB14 | 101
2 x Couvre joint | Rez de chaussée | NH II | 0.027 | 0.105 | 4.2711 | 0.2977 | 1.0593 | 1.0649 | 0.0121 | 0.0106 | 0 | 0 |  | Couvre-joint
Montant | Premier Etage | Epicéa C24 | 0.045 | 0.22 | 1.2513 | 2.178 | 0.6581 | 0.6779 | 0.0124 | 0.0123 | 0.052 | 0.0515 | 0 | MURS ETAGE | OB121 | 423
Chevron | Comble et couverture | NH II | 0.07 | 0.192 | 4.274 | 2.5805 | 2.1829 | 2.2098 | 0.0574 | 0.0559 | 0 | 0 |  | Charpente | Chevrons | 2081
contre poutre | Premier Etage | NH II | 0.027 | 0.165 | 1.0161 | 0.7351 | 0.3902 | 0.3991 | 0.0045 | 0.0045 | 0 | 0 |  | MURS ETAGE
5 x Chevron | Comble et couverture | NH II | 0.07 | 0.192 | 4.264 | 2.5805 | 2.1841 | 2.2109 | 0.0573 | 0.0559 | 0 | 0 |  | Charpente | Chevrons | 2079
Montant | Premier Etage | Epicéa C24 | 0.045 | 0.145 | 0.1234 | 0.9461 | 0.0433 | 0.0563 | 0.0008 | 0.0007 | 0.0034 | 0.0031 | 0 | MURS ETAGE | OB130 | 212
4 x Chevron | Comble et couverture | NH II | 0.07 | 0.192 | 3.6791 | 2.5805 | 1.8304 | 1.8573 | 0.0494 | 0.0463 | 0 | 0 |  | Charpente | Chevrons | 2111
Cache moineau | Comble et couverture | NH II | 0.07 | 0.192 | 0.1139 | 2.5805 | 0.0525 | 0.0794 | 0.0015 | 0.0013 | 0 | 0 |  | Chevrons | Toiture Salon | 2098
4 x Montant | Rez de chaussée | Epicéa C24 | 0.045 | 0.22 | 1.117 | 2.178 | 0.592 | 0.6118 | 0.0111 | 0.0111 | 0.0464 | 0.0464 | 0 | MURS RDC | OB017 | 522
6 x Montant | Rez de chaussée | Epicéa C24 | 0.045 | 0.22 | 2.478 | 2.178 | 1.3133 | 1.3331 | 0.0245 | 0.0245 | 0.103 | 0.103 | 0 | MURS RDC | OB05 | 201
4 x Montant | Rez de chaussée | Epicéa C24 | 0.045 | 0.22 | 1.117 | 2.178 | 0.592 | 0.6118 | 0.0111 | 0.0111 | 0.0464 | 0.0464 | 0 | MURS RDC | OB015 | 466
latte 27/40 | Rez de chaussée | Epicéa C24 | 0.04 | 0.024 | 0.1455 | 0.023 | 0.0186 | 0.0205 | 0.0001 | 0.0001 | 0.0006 | 0.0006 | 0 | MURS RDC | OB020 | 629
9 x latte 27/40 | Rez de chaussée | Epicéa C24 | 0.04 | 0.024 | 2.97 | 0.023 | 0.3802 | 0.3821 | 0.0029 | 0.0029 | 0.012 | 0.012 | 0 | MURS RDC | OB011 | 719
Panne | Comble et couverture | NH II | 0.16 | 0.28 | 1.7921 | 12.544 | 1.5135 | 1.6031 | 0.0803 | 0.0732 | 0 | 0 |  | Charpente | Toiture habitation | 1529
3 x latte 27/40 | Rez de chaussée | Epicéa C24 | 0.04 | 0.024 | 0.443 | 0.023 | 0.0567 | 0.0586 | 0.0004 | 0.0004 | 0.0018 | 0.0018 | 0 | MURS RDC | OB01 | 677
Lisse basse | Premier Etage | Epicéa C24 | 0.045 | 0.22 | 0.8808 | 2.178 | 0.4668 | 0.4866 | 0.0087 | 0.0087 | 0.0366 | 0.0366 | 0 | Plancher étage | ETA | 35
6 x Montant | Rez de chaussée | Epicéa C24 | 0.045 | 0.22 | 2.478 | 2.178 | 1.3133 | 1.3331 | 0.0245 | 0.0245 | 0.103 | 0.103 | 0 | MURS RDC | OB02 | 53
2 x Echantignole | Rez de chaussée | NH II | 0.16 | 0.0952 | 0.2269 | 1.4496 | 0.0748 | 0.1053 | 0.0035 | 0.0017 | 0 | 0 |  | Charpente | Ferme Garage | 1516
5 x latte 27/40 | Rez de chaussée | Epicéa C24 | 0.04 | 0.024 | 2.698 | 0.023 | 0.3453 | 0.3473 | 0.0026 | 0.0026 | 0.0109 | 0.0109 | 0 | MURS RDC | OB04 | 616
latte chantier | Rez de chaussée | Epicéa C24 | 0.04 | 0.024 | 0.265 | 0.023 | 0.0339 | 0.0358 | 0.0003 | 0.0003 | 0.0011 | 0.0011 | 0 | MURS RDC | R2 | 833
2 x Montant | Premier Etage | Epicéa C24 | 0.045 | 0.22 | 1.4593 | 2.178 | 0.7664 | 0.7862 | 0.0144 | 0.0143 | 0.0607 | 0.0599 | 0 | MURS COMBLE | OB127 | 195
latte 27/40 | Premier Etage | Epicéa C24 | 0.04 | 0.024 | 2.3366 | 0.023 | 0.2991 | 0.301 | 0.0022 | 0.0022 | 0.0094 | 0.0094 | 0 | MURS ETAGE | OB12 | 608
3 x Montant | Premier Etage | Epicéa C24 | 0.045 | 0.22 | 2.7993 | 2.178 | 1.4836 | 1.5034 | 0.0277 | 0.0277 | 0.1164 | 0.1164 | 0 | MURS ETAGE | OB120 | 381
Montant | Premier Etage | Epicéa C24 | 0.045 | 0.145 | 0.205 | 0.9461 | 0.0779 | 0.0909 | 0.0013 | 0.0013 | 0.0056 | 0.0056 | 0 | MURS ETAGE | OB131 | 494
Montant | Premier Etage | Epicéa C24 | 0.045 | 0.22 | 3.028 | 2.178 | 1.6048 | 1.6246 | 0.03 | 0.03 | 0.1259 | 0.1259 | 0 | MURS ETAGE | OB14 | 105
2 x Montant | Rez de chaussée | Epicéa C24 | 0.045 | 0.22 | 1.63 | 2.178 | 0.8639 | 0.8837 | 0.0161 | 0.0161 | 0.0678 | 0.0678 | 0 | MURS RDC | OB04 | 83
4 x Couvre joint | Rez de chaussée | NH II | 0.027 | 0.105 | 7.1105 | 0.2977 | 1.764 | 1.7696 | 0.0202 | 0.0176 | 0 | 0 |  | Couvre-joint
Cache moineau | Comble et couverture | NH II | 0.07 | 0.192 | 0.43 | 2.5805 | 0.2253 | 0.2522 | 0.0058 | 0.0058 | 0 | 0 |  | Chevrons | Toiture Salon | 2101
Aisselier | Premier Etage | NH II | 0.16 | 0.16 | 2.061 | 4.096 | 1.2236 | 1.2748 | 0.0538 | 0.0475 | 0 | 0 |  | Charpente | F01 | 1501
3 x latte 27/40 | Rez de chaussée | Epicéa C24 | 0.04 | 0.024 | 2.698 | 0.023 | 0.3453 | 0.3473 | 0.0026 | 0.0026 | 0.0109 | 0.0109 | 0 | MURS RDC | OB03 | 672
latte chantier | Rez de chaussée | Epicéa C24 | 0.04 | 0.024 | 2.7105 | 0.023 | 0.3469 | 0.3489 | 0.0026 | 0.0026 | 0.0109 | 0.0109 | 0 | MURS RDC | A2 | 802
Enrayure | Dalle | NH II | 0.2 | 0.5 | 2.1715 | 50 | 2.9351 | 3.1351 | 0.2172 | 0.2004 | 0 | 0 |  | Maçonnerie
2 x latte 27/40 | Premier Etage | Epicéa C24 | 0.04 | 0.024 | 1.0036 | 0.023 | 0.1285 | 0.1304 | 0.001 | 0.001 | 0.004 | 0.004 | 0 | MURS ETAGE | OB16 | 683
8 x Solive | Premier Etage | NH II | 0.092 | 0.22 | 0.3499 | 4.4528 | 0.2183 | 0.2588 | 0.0073 | 0.0071 | 0 | 0 |  | Plancher étage | Solivage_220 | 1046
4 x latte 27/40 | Rez de chaussée | Epicéa C24 | 0.04 | 0.024 | 2.74 | 0.023 | 0.3507 | 0.3526 | 0.0026 | 0.0026 | 0.011 | 0.011 | 0 | MURS RDC | OB08 | 694
Montant | Comble et couverture | Epicéa C24 | 0.0385 | 0.145 | 0.1901 | 0.8102 | 0.0698 | 0.081 | 0.0011 | 0.0011 | 0.0045 | 0.0045 | 0 | MURS COMBLE | OB128 | 134
Montant | Premier Etage | Epicéa C24 | 0.045 | 0.22 | 0.6612 | 2.178 | 0.3453 | 0.3651 | 0.0065 | 0.0064 | 0.0275 | 0.027 | 0 | MURS ETAGE | OB122 | 448
Lisse basse | Premier Etage | Epicéa C24 | 0.045 | 0.145 | 3.4387 | 0.9461 | 1.3067 | 1.3198 | 0.0224 | 0.0224 | 0.0942 | 0.0942 | 0 | Plancher étage | ETA | 29
2 x Cache moineau | Comble et couverture | NH II | 0.07 | 0.22 | 0.4804 | 3.388 | 0.2786 | 0.3094 | 0.0076 | 0.0074 | 0 | 0 |  | Chevrons | Toiture habitation | 2010
Montant | Comble et couverture | Epicéa C24 | 0.045 | 0.145 | 0.3845 | 0.9461 | 0.1461 | 0.1591 | 0.0025 | 0.0025 | 0.0105 | 0.0105 | 0 | MURS COMBLE | OB128 | 139
15 x Montant | Rez de chaussée | Epicéa C24 | 0.045 | 0.22 | 2.45 | 2.178 | 1.2985 | 1.3183 | 0.0243 | 0.0243 | 0.1019 | 0.1019 | 0 | MURS RDC | OB015 | 468
5 x Montant | Rez de chaussée | Epicéa C24 | 0.045 | 0.22 | 2.45 | 2.178 | 1.2985 | 1.3183 | 0.0243 | 0.0243 | 0.1019 | 0.1019 | 0 | MURS RDC | OB06 | 275
Panne | Comble et couverture | NH II | 0.16 | 0.24 | 6.2385 | 9.216 | 4.9577 | 5.0345 | 0.2396 | 0.2361 | 0 | 0 |  | Charpente | Toiture garage | 1524
4 x latte 27/40 | Rez de chaussée | Epicéa C24 | 0.04 | 0.024 | 2.645 | 0.023 | 0.3386 | 0.3405 | 0.0025 | 0.0025 | 0.0107 | 0.0107 | 0 | MURS RDC | OB013 | 731
2 x Cache moineau | Comble et couverture | NH II | 0.07 | 0.192 | 0.279 | 2.5805 | 0.1462 | 0.1731 | 0.0037 | 0.0037 | 0 | 0 |  | Chevrons | Toiture mezzanine | 2038
latte 27/40 | Rez de chaussée | Epicéa C24 | 0.04 | 0.024 | 0.415 | 0.023 | 0.0531 | 0.055 | 0.0004 | 0.0004 | 0.0017 | 0.0017 | 0 | MURS RDC | OB09 | 698
Enrayure | Dalle | NH II | 0.188 | 0.5 | 2.908 | 47 | 4.0014 | 4.1894 | 0.2734 | 0.2734 | 0 | 0 |  | Maçonnerie
latte 27/40 | Premier Etage | Epicéa C24 | 0.04 | 0.024 | 1.5211 | 0.023 | 0.1947 | 0.1966 | 0.0015 | 0.0015 | 0.0061 | 0.0061 | 0 | MURS ETAGE | OB126 | 757
Montant | Rez de chaussée | Epicéa C24 | 0.045 | 0.22 | 0.3642 | 2.178 | 0.193 | 0.2128 | 0.0036 | 0.0036 | 0.0151 | 0.0151 | 0 | MURS RDC | OB011 | 391
latte chantier | Rez de chaussée | Epicéa C24 | 0.04 | 0.024 | 0.25 | 0.023 | 0.032 | 0.0339 | 0.0002 | 0.0002 | 0.001 | 0.001 | 0 | MURS RDC | F3 | 812
latte 27/40 | Rez de chaussée | Epicéa C24 | 0.04 | 0.024 | 0.147 | 0.023 | 0.0188 | 0.0207 | 0.0001 | 0.0001 | 0.0006 | 0.0006 | 0 | MURS RDC | OB09 | 697
4 x Couvre joint | Rez de chaussée | NH II | 0.027 | 0.105 | 4.1028 | 0.2977 | 1.0175 | 1.0232 | 0.0116 | 0.0101 | 0 | 0 |  | Couvre-joint
4 x latte 27/40 | Premier Etage | Epicéa C24 | 0.04 | 0.024 | 2.7105 | 0.023 | 0.3469 | 0.3489 | 0.0026 | 0.0026 | 0.0109 | 0.0109 | 0 | MURS ETAGE | OB14 | 624
Chevron | Comble et couverture | NH II | 0.07 | 0.192 | 3.435 | 2.5805 | 1.7142 | 1.7411 | 0.0462 | 0.0437 | 0 | 0 |  | Charpente | Chevrons | 2020
Montant | Rez de chaussée | Epicéa C24 | 0.045 | 0.124 | 2.54 | 0.6921 | 0.8162 | 0.8273 | 0.0142 | 0.013 | 0.0595 | 0.0545 | 0 | MURS RDC | OB019 | 471
Montant | Premier Etage | Epicéa C24 | 0.045 | 0.22 | 2.7233 | 2.178 | 1.438 | 1.4578 | 0.027 | 0.0268 | 0.1132 | 0.1127 | 0 | MURS ETAGE | OB120 | 380
Cache moineau | Comble et couverture | NH II | 0.07 | 0.22 | 0.413 | 3.388 | 0.2395 | 0.2703 | 0.0064 | 0.0064 | 0 | 0 |  | Chevrons | Toiture habitation | 2002
2 x Couvre joint | Rez de chaussée | NH II | 0.027 | 0.105 | 4.2711 | 0.2977 | 1.1276 | 1.1332 | 0.0121 | 0.0121 | 0 | 0 |  | Couvre-joint
latte chantier | Rez de chaussée | Epicéa C24 | 0.04 | 0.024 | 1.0436 | 0.023 | 0.1336 | 0.1355 | 0.001 | 0.001 | 0.0042 | 0.0042 | 0 | MURS RDC | M3 | 827
2 x latte chantier | Rez de chaussée | Epicéa C24 | 0.04 | 0.024 | 2.645 | 0.023 | 0.3386 | 0.3405 | 0.0025 | 0.0025 | 0.0107 | 0.0107 | 0 | MURS RDC | P1 | 829
Montant | Rez de chaussée | Epicéa C24 | 0.045 | 0.199 | 2.935 | 1.7823 | 1.3835 | 1.4014 | 0.0263 | 0.0249 | 0.1104 | 0.1046 | 0 | MURS RDC | OB014 | 455
2 x Chevetre | Comble et couverture | NH II | 0.07 | 0.192 | 1.39 | 2.5805 | 0.7284 | 0.7552 | 0.0188 | 0.0187 | 0 | 0 |  | Chevrons | Toiture habitation | 2012
Chevron | Comble et couverture | NH II | 0.07 | 0.192 | 4.8164 | 2.5805 | 2.438 | 2.4649 | 0.0647 | 0.0622 | 0 | 0 |  | Charpente | Chevrons | 2027
Solive | Premier Etage | NH II | 0.092 | 0.22 | 0.8319 | 4.4528 | 0.5191 | 0.5596 | 0.018 | 0.0168 | 0 | 0 |  | Plancher étage | Solivage_220 | 1067
Enrayure | Dalle | NH II | 0.1891 | 0.5 | 2.6349 | 47.2811 | 3.5045 | 3.6936 | 0.2492 | 0.2374 | 0 | 0 |  | Maçonnerie
latte chantier | Rez de chaussée | Epicéa C24 | 0.04 | 0.024 | 0.6979 | 0.023 | 0.0893 | 0.0912 | 0.0007 | 0.0007 | 0.0028 | 0.0028 | 0 | MURS RDC | U4 | 842
2 x latte 27/40 | Premier Etage | Epicéa C24 | 0.04 | 0.024 | 0.4411 | 0.023 | 0.0565 | 0.0584 | 0.0004 | 0.0004 | 0.0018 | 0.0018 | 0 | MURS ETAGE | OB127 | 640
2 x Entrait | Rez de chaussée | NH II | 0.1 | 0.24 | 6.38 | 5.76 | 4.3384 | 4.3864 | 0.1531 | 0.1531 | 0 | 0 |  | Charpente | Ferme Garage | 1517
latte 27/40 | Premier Etage | Epicéa C24 | 0.04 | 0.024 | 1.2043 | 0.023 | 0.1541 | 0.1561 | 0.0012 | 0.0012 | 0.0049 | 0.0049 | 0 | MURS ETAGE | OB126 | 756
Montant | Rez de chaussée | Epicéa C24 | 0.045 | 0.145 | 2.67 | 0.9461 | 1.0146 | 1.0277 | 0.0174 | 0.0174 | 0.0732 | 0.0732 | 0 | MURS RDC | OB023 | 125
4 x Solive | Premier Etage | NH II | 0.092 | 0.192 | 6.424 | 3.3915 | 3.6488 | 3.6842 | 0.1145 | 0.1135 | 0 | 0 |  | Plancher étage | Solivage_192 | 1032
2 x Couvre joint | Rez de chaussée | NH II | 0.027 | 0.105 | 4.4753 | 0.2977 | 1.145 | 1.1507 | 0.0127 | 0.0121 | 0 | 0 |  | Couvre-joint
3 x Montant | Premier Etage | Epicéa C24 | 0.045 | 0.22 | 0.4051 | 2.178 | 0.2147 | 0.2345 | 0.004 | 0.004 | 0.0168 | 0.0168 | 0 | MURS ETAGE | OB124 | 516
Chevron | Comble et couverture | NH II | 0.07 | 0.192 | 3.7803 | 2.5805 | 1.8951 | 1.922 | 0.0508 | 0.0483 | 0 | 0 |  | Charpente | Chevrons | 2022
4 x Couvre joint | Rez de chaussée | NH II | 0.027 | 0.105 | 3.06 | 0.2977 | 0.7677 | 0.7734 | 0.0087 | 0.0079 | 0 | 0 |  | Couvre-joint
5 x Montant | Premier Etage | Epicéa C24 | 0.045 | 0.22 | 0.523 | 2.178 | 0.2772 | 0.297 | 0.0052 | 0.0052 | 0.0217 | 0.0217 | 0 | MURS ETAGE | OB12 | 59
latte chantier | Rez de chaussée | Epicéa C24 | 0.04 | 0.024 | 0.6979 | 0.023 | 0.0893 | 0.0912 | 0.0007 | 0.0007 | 0.0028 | 0.0028 | 0 | MURS RDC | W3 | 844
4 x Balustre horizontale | Premier Etage | NH II | 0.027 | 0.165 | 3.385 | 0.7351 | 1.2998 | 1.3087 | 0.0151 | 0.0151 | 0 | 0 |  | Balcon Etage | balustrade | 5002
4 x Montant | Premier Etage | Epicéa C24 | 0.045 | 0.22 | 0.7507 | 2.178 | 0.3979 | 0.4177 | 0.0074 | 0.0074 | 0.0312 | 0.0312 | 0 | MURS ETAGE | OB127 | 167
Solive | Premier Etage | NH II | 0.092 | 0.22 | 0.4724 | 4.4528 | 0.2665 | 0.307 | 0.0096 | 0.0083 | 0 | 0 |  | Plancher étage | Solivage_220 | 1048
3 x latte 27/40 | Rez de chaussée | Epicéa C24 | 0.04 | 0.024 | 0.39 | 0.023 | 0.0499 | 0.0518 | 0.0004 | 0.0004 | 0.0016 | 0.0016 | 0 | MURS RDC | OB013 | 730
Montant | Premier Etage | Epicéa C24 | 0.0252 | 0.22 | 1.0086 | 1.2192 | 0.4946 | 0.5057 | 0.0056 | 0.0056 | 0.0235 | 0.0235 | 0 | MURS ETAGE | OB120 | 353
3 x Montant | Premier Etage | Epicéa C24 | 0.045 | 0.22 | 0.4051 | 2.178 | 0.2147 | 0.2345 | 0.004 | 0.004 | 0.0168 | 0.0168 | 0 | MURS ETAGE | OB120 | 361
3 x Montant | Rez de chaussée | Epicéa C24 | 0.045 | 0.22 | 1.53 | 2.178 | 0.8109 | 0.8307 | 0.0151 | 0.0151 | 0.0636 | 0.0636 | 0 | MURS RDC | OB020 | 149
2 x Montant | Rez de chaussée | Epicéa C24 | 0.045 | 0.22 | 0.415 | 2.178 | 0.2199 | 0.2397 | 0.0041 | 0.0041 | 0.0173 | 0.0173 | 0 | MURS RDC | OB011 | 393
3 x Solive | Premier Etage | NH II | 0.092 | 0.192 | 0.941 | 3.3915 | 0.5345 | 0.5698 | 0.0176 | 0.0166 | 0 | 0 |  | Plancher étage | Solivage_192 | 1025
Couvre joint | Rez de chaussée | NH II | 0.027 | 0.105 | 3.9386 | 0.2977 | 1.0365 | 1.0422 | 0.0112 | 0.0111 | 0 | 0 |  | Couvre-joint
Main courante | Premier Etage | NH II | 0.045 | 0.14 | 3.421 | 0.882 | 1.2418 | 1.2544 | 0.0216 | 0.0207 | 0 | 0 |  | Balcon Etage | balustrade | 5006
5 x Montant | Premier Etage | Epicéa C24 | 0.045 | 0.22 | 1.323 | 2.178 | 0.7012 | 0.721 | 0.0131 | 0.0131 | 0.055 | 0.055 | 0 | MURS ETAGE | OB127 | 171
6 x Montant | Rez de chaussée | Epicéa C24 | 0.045 | 0.22 | 2.845 | 2.178 | 1.5078 | 1.5276 | 0.0282 | 0.0282 | 0.1183 | 0.1183 | 0 | MURS RDC | OB011 | 400
Ceinture | Premier Etage | NH II | 0.07 | 0.192 | 3.388 | 2.5805 | 1.7619 | 1.7888 | 0.0455 | 0.0451 | 0 | 0 |  | Plancher étage | Solivage_192 | 1011
Montant | Premier Etage | Epicéa C24 | 0.045 | 0.22 | 2.4654 | 2.178 | 1.2997 | 1.3195 | 0.0244 | 0.0242 | 0.1025 | 0.1017 | 0 | MURS ETAGE | OB127 | 180
2 x Montant | Premier Etage | Epicéa C24 | 0.045 | 0.145 | 2.166 | 0.9461 | 0.8231 | 0.8361 | 0.0141 | 0.0141 | 0.0594 | 0.0594 | 0 | MURS ETAGE | OB128 | 130
latte 27/40 | Premier Etage | Epicéa C24 | 0.04 | 0.024 | 0.5006 | 0.023 | 0.0641 | 0.066 | 0.0005 | 0.0005 | 0.002 | 0.002 | 0 | MURS COMBLE | OB127 | 662
Couvre joint | Rez de chaussée | NH II | 0.027 | 0.105 | 3.2403 | 0.2977 | 0.8085 | 0.8142 | 0.0092 | 0.0084 | 0 | 0 |  | Couvre-joint
Lisse basse | Rez de chaussée | Epicéa C24 | 0.045 | 0.22 | 1.4236 | 2.178 | 0.7545 | 0.7743 | 0.0141 | 0.0141 | 0.0592 | 0.0592 | 0 | MURS RDC | OB010 | 345
contre poutre | Premier Etage | NH II | 0.027 | 0.165 | 3.244 | 0.7351 | 1.2457 | 1.2546 | 0.0145 | 0.0145 | 0 | 0 |  | Plancher étage
latte 27/40 | Rez de chaussée | Epicéa C24 | 0.04 | 0.024 | 1.247 | 0.023 | 0.1596 | 0.1615 | 0.0012 | 0.0012 | 0.005 | 0.005 | 0 | MURS RDC | OB015 | 740
5 x Montant | Rez de chaussée | Epicéa C24 | 0.045 | 0.145 | 2.45 | 0.9461 | 0.931 | 0.9441 | 0.016 | 0.016 | 0.0671 | 0.0671 | 0 | MURS RDC | OB023 | 124
Ceinture | Premier Etage | NH II | 0.092 | 0.22 | 2.2013 | 4.4528 | 1.3079 | 1.3484 | 0.0446 | 0.0416 | 0 | 0 |  | Plancher étage | Solivage_220 | 1041
Montant | Premier Etage | Epicéa C24 | 0.045 | 0.145 | 0.2454 | 0.9461 | 0.0896 | 0.1027 | 0.0016 | 0.0015 | 0.0067 | 0.0064 | 0 | MURS ETAGE | OB130 | 214
2 x Couvre joint | Rez de chaussée | NH II | 0.027 | 0.105 | 3.9386 | 0.2977 | 1.0077 | 1.0133 | 0.0112 | 0.0106 | 0 | 0 |  | Couvre-joint
2 x Montant | Premier Etage | Epicéa C24 | 0.045 | 0.22 | 1.3208 | 2.178 | 0.7 | 0.7198 | 0.0131 | 0.0131 | 0.0549 | 0.0549 | 0 | MURS ETAGE | OB13 | 247
Montant | Rez de chaussée | Epicéa C24 | 0.045 | 0.22 | 2.385 | 2.178 | 1.264 | 1.2838 | 0.0236 | 0.0236 | 0.0992 | 0.0992 | 0 | MURS RDC | OB012 | 411
Cache moineau | Comble et couverture | NH II | 0.07 | 0.22 | 0.4966 | 3.388 | 0.288 | 0.3188 | 0.0076 | 0.0076 | 0 | 0 |  | Chevrons | Toiture habitation | 2007
Montant | Premier Etage | Epicéa C24 | 0.045 | 0.22 | 0.7145 | 2.178 | 0.3717 | 0.3915 | 0.0071 | 0.0069 | 0.0297 | 0.0289 | 0 | MURS COMBLE | OB127 | 188
Couvre joint | Rez de chaussée | NH II | 0.027 | 0.105 | 4.0628 | 0.2977 | 1.0726 | 1.0783 | 0.0115 | 0.0115 | 0 | 0 |  | Couvre-joint
6 x Montant | Rez de chaussée | Epicéa C24 | 0.045 | 0.145 | 2.45 | 0.9461 | 0.931 | 0.944 | 0.016 | 0.016 | 0.0671 | 0.0671 | 0 | MURS RDC | OB026 | 489
Montant | Premier Etage | Epicéa C24 | 0.045 | 0.22 | 0.1673 | 2.178 | 0.0817 | 0.1015 | 0.0017 | 0.0015 | 0.007 | 0.0062 | 0 | MURS ETAGE | OB127 | 160
Montant | Premier Etage | Epicéa C24 | 0.045 | 0.145 | 2.4521 | 0.9461 | 0.9282 | 0.9412 | 0.016 | 0.0159 | 0.0672 | 0.0669 | 0 | MURS ETAGE | OB130 | 232
Couvre joint | Rez de chaussée | NH II | 0.027 | 0.0126 | 3.9386 | 0.0043 | 0.2729 | 0.2736 | 0.0013 | 0.0007 | 0 | 0 |  | Couvre-joint
2 x Montant | Rez de chaussée | Epicéa C24 | 0.045 | 0.22 | 0.73 | 2.178 | 0.3869 | 0.4067 | 0.0072 | 0.0072 | 0.0304 | 0.0304 | 0 | MURS RDC | OB015 | 465
latte 27/40 | Premier Etage | Epicéa C24 | 0.04 | 0.024 | 0.5611 | 0.023 | 0.0718 | 0.0737 | 0.0005 | 0.0005 | 0.0023 | 0.0023 | 0 | MURS ETAGE | OB17 | 689
3 x Montant | Comble et couverture | Epicéa C24 | 0.045 | 0.145 | 1.16 | 0.9461 | 0.4408 | 0.4539 | 0.0076 | 0.0076 | 0.0318 | 0.0318 | 0 | MURS COMBLE | OB129 | 257
5 x latte 27/40 | Rez de chaussée | Epicéa C24 | 0.04 | 0.024 | 2.97 | 0.023 | 0.3802 | 0.3821 | 0.0029 | 0.0029 | 0.012 | 0.012 | 0 | MURS RDC | OB014 | 738
Cache moineau | Comble et couverture | NH II | 0.07 | 0.192 | 0.4088 | 2.5805 | 0.207 | 0.2339 | 0.0055 | 0.0053 | 0 | 0 |  | Chevrons | Toiture Salon | 2100
3 x Montant | Rez de chaussée | Epicéa C24 | 0.045 | 0.22 | 1.117 | 2.178 | 0.592 | 0.6118 | 0.0111 | 0.0111 | 0.0464 | 0.0464 | 0 | MURS RDC | OB019 | 475
latte 27/40 | Rez de chaussée | Epicéa C24 | 0.04 | 0.024 | 1.247 | 0.023 | 0.1596 | 0.1615 | 0.0012 | 0.0012 | 0.005 | 0.005 | 0 | MURS RDC | OB019 | 743
latte chantier | Rez de chaussée | Epicéa C24 | 0.04 | 0.024 | 2.67 | 0.023 | 0.3418 | 0.3437 | 0.0026 | 0.0026 | 0.0108 | 0.0108 | 0 | MURS RDC | OB08 | 825
Lisse basse | Premier Etage | Epicéa C24 | 0.045 | 0.22 | 4.8508 | 2.178 | 2.5709 | 2.5907 | 0.048 | 0.048 | 0.2017 | 0.2017 | 0 | Plancher étage | ETA | 47
2 x latte chantier | Rez de chaussée | Epicéa C24 | 0.04 | 0.024 | 0.4686 | 0.023 | 0.06 | 0.0619 | 0.0004 | 0.0004 | 0.0019 | 0.0019 | 0 | MURS RDC | K2 | 821
3 x Montant | Premier Etage | Epicéa C24 | 0.045 | 0.22 | 2.6405 | 2.178 | 1.3994 | 1.4192 | 0.0261 | 0.0261 | 0.1098 | 0.1098 | 0 | MURS ETAGE | OB12 | 69
2 x Montant | Rez de chaussée | Epicéa C24 | 0.045 | 0.22 | 0.415 | 2.178 | 0.22 | 0.2398 | 0.0041 | 0.0041 | 0.0173 | 0.0173 | 0 | MURS RDC | OB011 | 393
2 x Montant | Rez de chaussée | Epicéa C24 | 0.045 | 0.22 | 1.33 | 2.178 | 0.7049 | 0.7247 | 0.0132 | 0.0132 | 0.0553 | 0.0553 | 0 | MURS RDC | OB011 | 398
2 x latte 27/40 | Premier Etage | Epicéa C24 | 0.04 | 0.024 | 1.3999 | 0.023 | 0.1792 | 0.1811 | 0.0013 | 0.0013 | 0.0056 | 0.0056 | 0 | MURS ETAGE | OB127 | 651
latte 27/40 | Premier Etage | Epicéa C24 | 0.04 | 0.024 | 0.7776 | 0.023 | 0.0995 | 0.1015 | 0.0007 | 0.0007 | 0.0031 | 0.0031 | 0 | MURS COMBLE | OB127 | 663
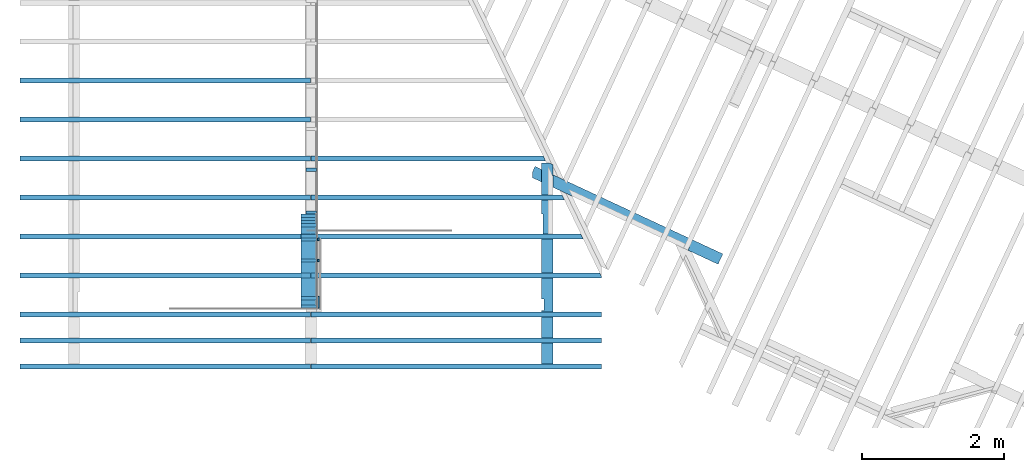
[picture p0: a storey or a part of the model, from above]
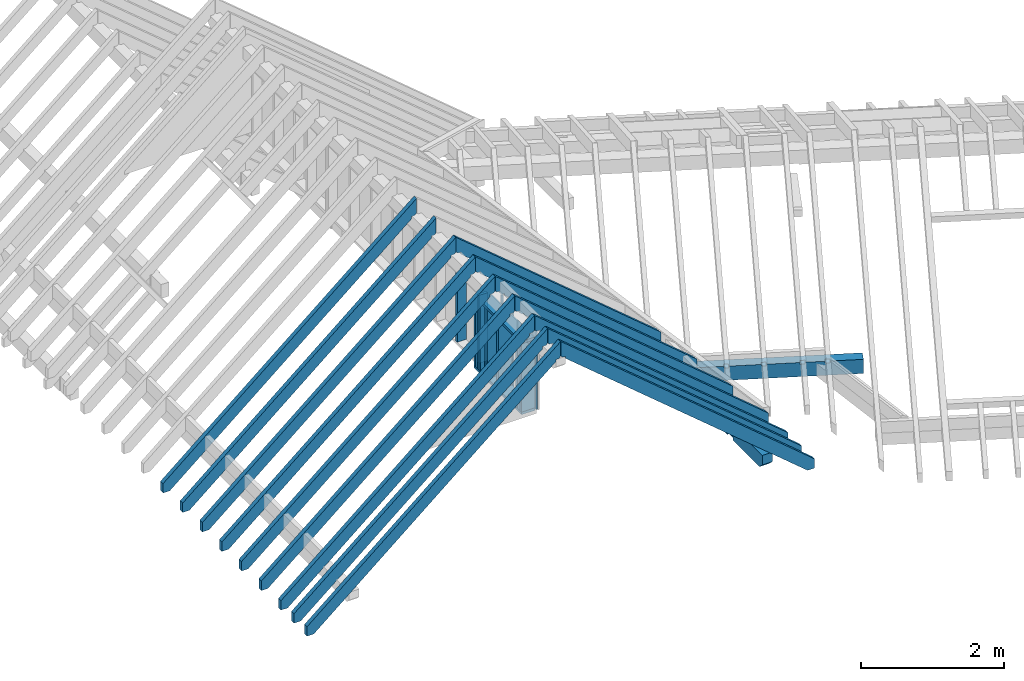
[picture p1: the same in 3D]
Properties of the parts of a building model (IFC2X3), part 2 of 4

# IfcMember (1988)
Name | In | Material | Width (m) | Height (m) | Length (m) | CrossSectionArea (m2) | OuterfaceArea (m2) | TotalSurfaceArea (m2) | GrossVolume (m3) | NetVolume (m3) | GrossWeight | NetWeight | SKU | Group | SubGroup | Prod_Nb
Lisse basse | Premier Etage | Epicéa C24 | 0.045 | 0.22 | 2.844 | 2.178 | 1.5073 | 1.5271 | 0.0282 | 0.0282 | 0.1183 | 0.1183 | 0 | Plancher étage | ETA | 42
Chevron | Comble et couverture | NH II | 0.07 | 0.192 | 3.8273 | 2.5805 | 1.9384 | 1.9652 | 0.0514 | 0.0494 | 0 | 0 |  | Charpente | Chevrons | 2075
2 x Montant | Rez de chaussée | Epicéa C24 | 0.045 | 0.22 | 1.923 | 2.178 | 1.0192 | 1.039 | 0.019 | 0.019 | 0.08 | 0.08 | 0 | MURS RDC | OB011 | 399
latte 27/40 | Premier Etage | Epicéa C24 | 0.04 | 0.024 | 1.8105 | 0.023 | 0.2317 | 0.2337 | 0.0017 | 0.0017 | 0.0073 | 0.0073 | 0 | MURS ETAGE | OB12 | 607
4 x Montant | Rez de chaussée | Epicéa C24 | 0.045 | 0.22 | 0.417 | 2.178 | 0.221 | 0.2408 | 0.0041 | 0.0041 | 0.0173 | 0.0173 | 0 | MURS RDC | OB011 | 394
4 x Montant | Premier Etage | Epicéa C24 | 0.045 | 0.22 | 0.4557 | 2.178 | 0.2415 | 0.2613 | 0.0045 | 0.0045 | 0.0189 | 0.0189 | 0 | MURS ETAGE | OB127 | 163
latte 27/40 | Premier Etage | Epicéa C24 | 0.04 | 0.024 | 1.2866 | 0.023 | 0.1647 | 0.1666 | 0.0012 | 0.0012 | 0.0052 | 0.0052 | 0 | MURS ETAGE | OB127 | 650
contre poutre | Premier Etage | NH II | 0.027 | 0.165 | 5.32 | 0.7351 | 1.9723 | 1.9812 | 0.0237 | 0.0228 | 0 | 0 |  | Plancher étage
3 x Montant | Rez de chaussée | Epicéa C24 | 0.045 | 0.145 | 0.465 | 0.9461 | 0.1767 | 0.1897 | 0.003 | 0.003 | 0.0127 | 0.0127 | 0 | MURS RDC | OB022 | 115
4 x latte 27/40 | Rez de chaussée | Epicéa C24 | 0.04 | 0.024 | 2.645 | 0.023 | 0.3386 | 0.3405 | 0.0025 | 0.0025 | 0.0107 | 0.0107 | 0 | MURS RDC | OB012 | 722
Enrayure | Dalle | NH II | 0.188 | 0.5 | 7.508 | 47 | 10.331 | 10.519 | 0.7058 | 0.7058 | 0 | 0 |  | Maçonnerie
2 x Montant | Rez de chaussée | Epicéa C24 | 0.045 | 0.22 | 2.575 | 2.178 | 1.3648 | 1.3846 | 0.0255 | 0.0255 | 0.1071 | 0.1071 | 0 | MURS RDC | OB012 | 412
Montant | Rez de chaussée | Epicéa C24 | 0.045 | 0.22 | 2.385 | 2.178 | 1.264 | 1.2838 | 0.0236 | 0.0236 | 0.0992 | 0.0992 | 0 | MURS RDC | OB013 | 437
Montant | Premier Etage | Epicéa C24 | 0.045 | 0.22 | 2.4585 | 2.178 | 1.2869 | 1.3067 | 0.0243 | 0.0238 | 0.1022 | 0.1001 | 0 | MURS ETAGE | OB120 | 376
contre poutre | Premier Etage | NH II | 0.027 | 0.165 | 0.8376 | 0.7351 | 0.2864 | 0.2953 | 0.0037 | 0.0033 | 0 | 0 |  | Plancher étage
6 x Montant | Premier Etage | Epicéa C24 | 0.045 | 0.22 | 0.5273 | 2.178 | 0.2795 | 0.2993 | 0.0052 | 0.0052 | 0.0219 | 0.0219 | 0 | MURS ETAGE | OB127 | 165
2 x latte chantier | Rez de chaussée | Epicéa C24 | 0.04 | 0.024 | 2.97 | 0.023 | 0.3802 | 0.3821 | 0.0029 | 0.0029 | 0.012 | 0.012 | 0 | MURS RDC | N1 | 828
Lisse basse | Rez de chaussée | Epicéa C24 | 0.045 | 0.22 | 1.8539 | 2.178 | 0.9825 | 1.0023 | 0.0184 | 0.0184 | 0.0771 | 0.0771 | 0 | MURS RDC | OB06 | 273
latte 27/40 | Premier Etage | Epicéa C24 | 0.04 | 0.024 | 1.411 | 0.023 | 0.1806 | 0.1825 | 0.0014 | 0.0014 | 0.0057 | 0.0057 | 0 | MURS ETAGE | OB127 | 652
Montant | Rez de chaussée | Epicéa C24 | 0.017 | 0.22 | 1.7489 | 0.8228 | 0.829 | 0.8365 | 0.0065 | 0.0065 | 0.0275 | 0.0275 | 0 | MURS RDC | OB012 | 407
Montant | Rez de chaussée | Epicéa C24 | 0.045 | 0.22 | 2.385 | 2.178 | 1.264 | 1.2839 | 0.0236 | 0.0236 | 0.0992 | 0.0992 | 0 | MURS RDC | OB012 | 411
Linteau | Comble et couverture | Epicéa C24 | 0.14 | 0.2 | 0.87 | 5.6 | 0.5916 | 0.6476 | 0.0244 | 0.0244 | 0.1023 | 0.1023 | 0 | Charpente | OB130 | 1500
Montant | Premier Etage | Epicéa C24 | 0.045 | 0.145 | 1.8739 | 0.9461 | 0.7085 | 0.7215 | 0.0122 | 0.0122 | 0.0514 | 0.051 | 0 | MURS ETAGE | OB130 | 227
2 x latte 27/40 | Rez de chaussée | Epicéa C24 | 0.04 | 0.024 | 2.698 | 0.023 | 0.3453 | 0.3473 | 0.0026 | 0.0026 | 0.0109 | 0.0109 | 0 | MURS RDC | OB05 | 668
Cache moineau | Comble et couverture | NH II | 0.07 | 0.22 | 0.424 | 3.388 | 0.2459 | 0.2767 | 0.0065 | 0.0065 | 0 | 0 |  | Chevrons | Toiture habitation | 2011
2 x contre poutre | Premier Etage | NH II | 0.027 | 0.165 | 3.922 | 0.7351 | 1.506 | 1.515 | 0.0175 | 0.0175 | 0 | 0 |  | Plancher étage
3 x latte 27/40 | Premier Etage | Epicéa C24 | 0.04 | 0.024 | 0.4371 | 0.023 | 0.0559 | 0.0579 | 0.0004 | 0.0004 | 0.0018 | 0.0018 | 0 | MURS ETAGE | OB121 | 724
3 x Montant | Premier Etage | Epicéa C24 | 0.045 | 0.22 | 0.135 | 2.178 | 0.0715 | 0.0913 | 0.0013 | 0.0013 | 0.0056 | 0.0056 | 0 | MURS ETAGE | OB127 | 157
3 x Cache moineau | Comble et couverture | NH II | 0.07 | 0.192 | 0.384 | 2.5805 | 0.2012 | 0.2281 | 0.0052 | 0.0052 | 0 | 0 |  | Chevrons | Toiture mezzanine | 2043
Montant | Premier Etage | Epicéa C24 | 0.012 | 0.22 | 0.4051 | 0.5808 | 0.188 | 0.1932 | 0.0011 | 0.0011 | 0.0045 | 0.0045 | 0 | MURS ETAGE | OB120 | 352
Chevron | Comble et couverture | NH II | 0.07 | 0.192 | 3.2708 | 2.5805 | 1.6622 | 1.6891 | 0.044 | 0.0425 | 0 | 0 |  | Charpente | Chevrons | 2060
2 x Montant | Rez de chaussée | Epicéa C24 | 0.045 | 0.22 | 2.39 | 2.178 | 1.2667 | 1.2865 | 0.0237 | 0.0237 | 0.0994 | 0.0994 | 0 | MURS RDC | OB027 | 350
2 x Couvre joint | Rez de chaussée | NH II | 0.027 | 0.105 | 4.0711 | 0.2977 | 1.0529 | 1.0586 | 0.0115 | 0.0112 | 0 | 0 |  | Couvre-joint
3 x latte 27/40 | Rez de chaussée | Epicéa C24 | 0.04 | 0.024 | 0.485 | 0.023 | 0.0621 | 0.064 | 0.0005 | 0.0005 | 0.002 | 0.002 | 0 | MURS RDC | OB08 | 693
Panne | Comble et couverture | NH II | 0.16 | 0.2 | 5.4964 | 6.4 | 3.9074 | 3.9714 | 0.1759 | 0.1727 | 0 | 0 |  | Charpente | Toiture Salon | 1538
2 x latte 27/40 | Premier Etage | Epicéa C24 | 0.04 | 0.024 | 0.4495 | 0.023 | 0.0575 | 0.0595 | 0.0004 | 0.0004 | 0.0018 | 0.0018 | 0 | MURS ETAGE | OB14 | 618
Montant | Premier Etage | Epicéa C24 | 0.045 | 0.22 | 0.5239 | 2.178 | 0.2707 | 0.2905 | 0.0052 | 0.005 | 0.0218 | 0.021 | 0 | MURS ETAGE | OB12 | 60
4 x poteau de balcon | Premier Etage | Sapin | 0.117 | 0.07 | 1.182 | 0.5733 | 0.4295 | 0.4459 | 0.0097 | 0.0089 | 0.0484 | 0.0447 |  | Balcon Etage | balustrade | 5000
2 x Montant | Premier Etage | Epicéa C24 | 0.045 | 0.22 | 1.5878 | 2.178 | 0.8415 | 0.8613 | 0.0157 | 0.0157 | 0.066 | 0.066 | 0 | MURS ETAGE | OB15 | 209
Montant | Rez de chaussée | Epicéa C24 | 0.045 | 0.22 | 0.0976 | 2.178 | 0.0517 | 0.0715 | 0.001 | 0.001 | 0.0041 | 0.0041 | 0 | MURS RDC | OB014 | 456
Solive | Premier Etage | NH II | 0.092 | 0.22 | 7.8347 | 4.4528 | 4.8776 | 4.918 | 0.1596 | 0.1581 | 0 | 0 |  | Plancher étage | Solivage_220 | 1061
latte chantier | Rez de chaussée | Epicéa C24 | 0.04 | 0.024 | 1.1678 | 0.023 | 0.1495 | 0.1514 | 0.0011 | 0.0011 | 0.0047 | 0.0047 | 0 | MURS RDC | B2 | 805
2 x Montant | Rez de chaussée | Epicéa C24 | 0.045 | 0.22 | 1.426 | 2.178 | 0.7558 | 0.7756 | 0.0141 | 0.0141 | 0.0593 | 0.0593 | 0 | MURS RDC | OB02 | 51
8 x Chevron | Comble et couverture | NH II | 0.07 | 0.192 | 3.4939 | 2.5805 | 1.7798 | 1.8067 | 0.047 | 0.0456 | 0 | 0 |  | Charpente | Chevrons | 2110
Montant | Premier Etage | Epicéa C24 | 0.045 | 0.145 | 1.4523 | 0.9461 | 0.5519 | 0.5649 | 0.0095 | 0.0095 | 0.0398 | 0.0398 | 0 | MURS ETAGE | OB131 | 512
2 x Montant | Premier Etage | Epicéa C24 | 0.045 | 0.22 | 1.0428 | 2.178 | 0.5527 | 0.5725 | 0.0103 | 0.0103 | 0.0434 | 0.0434 | 0 | MURS ETAGE | OB15 | 208
3 x latte 27/40 | Premier Etage | Epicéa C24 | 0.04 | 0.024 | 2.7105 | 0.023 | 0.3469 | 0.3489 | 0.0026 | 0.0026 | 0.0109 | 0.0109 | 0 | MURS ETAGE | OB12 | 609
latte 27/40 | Premier Etage | Epicéa C24 | 0.04 | 0.024 | 1.1278 | 0.023 | 0.1444 | 0.1463 | 0.0011 | 0.0011 | 0.0045 | 0.0045 | 0 | MURS ETAGE | OB15 | 669
Panne | Comble et couverture | NH II | 0.16 | 0.24 | 6.2385 | 9.216 | 4.9577 | 5.0345 | 0.2396 | 0.2365 | 0 | 0 |  | Charpente | Toiture garage | 1525
2 x Montant | Premier Etage | Epicéa C24 | 0.045 | 0.22 | 0.9386 | 2.178 | 0.4975 | 0.5173 | 0.0093 | 0.0093 | 0.039 | 0.039 | 0 | MURS ETAGE | OB15 | 207
Montant | Premier Etage | Epicéa C24 | 0.045 | 0.22 | 6.5091 | 2.178 | 3.4498 | 3.4696 | 0.0644 | 0.0644 | 0.2707 | 0.2707 | 0 | MURS ETAGE | OB127 | 183
2 x Montant | Rez de chaussée | Epicéa C24 | 0.045 | 0.22 | 2.845 | 2.178 | 1.5079 | 1.5277 | 0.0282 | 0.0282 | 0.1183 | 0.1183 | 0 | MURS RDC | OB014 | 462
Montant | Premier Etage | Epicéa C24 | 0.045 | 0.145 | 1.6939 | 0.9461 | 0.64 | 0.6531 | 0.0111 | 0.011 | 0.0464 | 0.0461 | 0 | MURS ETAGE | OB130 | 225
Lisse basse | Premier Etage | Epicéa C24 | 0.045 | 0.22 | 0.7186 | 2.178 | 0.3809 | 0.4007 | 0.0071 | 0.0071 | 0.0299 | 0.0299 | 0 | Plancher étage | ETA | 33
Montant | Premier Etage | Epicéa C24 | 0.045 | 0.22 | 0.8674 | 2.178 | 0.456 | 0.4758 | 0.0086 | 0.0085 | 0.0361 | 0.0357 | 0 | MURS ETAGE | OB17 | 303
4 x Montant | Premier Etage | Epicéa C24 | 0.045 | 0.22 | 1.2153 | 2.178 | 0.6441 | 0.6639 | 0.012 | 0.012 | 0.0505 | 0.0505 | 0 | MURS ETAGE | OB120 | 365
Montant | Rez de chaussée | Epicéa C24 | 0.045 | 0.145 | 2.45 | 0.9461 | 0.931 | 0.9441 | 0.016 | 0.016 | 0.0671 | 0.0671 | 0 | MURS RDC | OB026 | 489
Montant | Premier Etage | Epicéa C24 | 0.045 | 0.22 | 3.284 | 2.178 | 1.7405 | 1.7603 | 0.0325 | 0.0325 | 0.1365 | 0.1365 | 0 | MURS ETAGE | OB125 | 531
Montant | Rez de chaussée | Epicéa C24 | 0.045 | 0.1315 | 2.54 | 0.7778 | 0.8213 | 0.8332 | 0.015 | 0.012 | 0.0631 | 0.0502 | 0 | MURS RDC | OB09 | 322
Lisse basse | Premier Etage | Epicéa C24 | 0.045 | 0.22 | 3.48 | 2.178 | 1.8444 | 1.8642 | 0.0345 | 0.0345 | 0.1447 | 0.1447 | 0 | Plancher étage | ETA | 45
4 x Montant | Premier Etage | Epicéa C24 | 0.045 | 0.22 | 0.3045 | 2.178 | 0.1614 | 0.1812 | 0.003 | 0.003 | 0.0127 | 0.0127 | 0 | MURS ETAGE | OB127 | 162
Lisse basse | Rez de chaussée | Epicéa C24 | 0.045 | 0.22 | 7.884 | 2.178 | 4.1785 | 4.1983 | 0.0781 | 0.0781 | 0.3278 | 0.3278 | 0 | MURS RDC | OB01 | 263
5 x Montant | Rez de chaussée | Epicéa C24 | 0.045 | 0.22 | 2.45 | 2.178 | 1.2985 | 1.3183 | 0.0243 | 0.0243 | 0.1019 | 0.1019 | 0 | MURS RDC | OB027 | 351
3 x latte 27/40 | Rez de chaussée | Epicéa C24 | 0.04 | 0.024 | 0.39 | 0.023 | 0.0499 | 0.0518 | 0.0004 | 0.0004 | 0.0016 | 0.0016 | 0 | MURS RDC | OB012 | 721
Montant | Premier Etage | Epicéa C24 | 0.045 | 0.22 | 1.622 | 2.178 | 0.8597 | 0.8795 | 0.0161 | 0.0161 | 0.0674 | 0.0674 | 0 | MURS ETAGE | OB120 | 381
Chevron | Comble et couverture | NH II | 0.07 | 0.192 | 2.233 | 2.5805 | 1.0882 | 1.115 | 0.03 | 0.027 | 0 | 0 |  | Charpente | Chevrons | 2106
Montant | Premier Etage | Epicéa C24 | 0.045 | 0.22 | 2.3542 | 2.178 | 1.2424 | 1.2622 | 0.0233 | 0.0232 | 0.0979 | 0.0973 | 0 | MURS ETAGE | OB120 | 375
Lisse basse | Premier Etage | Epicéa C24 | 0.045 | 0.145 | 3.115 | 0.9461 | 1.1837 | 1.1967 | 0.0203 | 0.0203 | 0.0854 | 0.0854 | 0 | Plancher étage | ETA | 28
Panne | Comble et couverture | NH II | 0.2 | 0.24 | 11.2429 | 11.52 | 9.9137 | 10.0097 | 0.5397 | 0.5306 | 0 | 0 |  | Charpente | Toiture mezzanine | 1536
5 x Cache moineau | Comble et couverture | NH II | 0.07 | 0.192 | 0.433 | 2.5805 | 0.2269 | 0.2538 | 0.0058 | 0.0058 | 0 | 0 |  | Chevrons | Toiture mezzanine | 2042
Cache moineau | Comble et couverture | NH II | 0.07 | 0.22 | 0.4542 | 3.388 | 0.2634 | 0.2942 | 0.007 | 0.007 | 0 | 0 |  | Chevrons | Toiture habitation | 2006
2 x Chevron | Comble et couverture | NH II | 0.07 | 0.192 | 1.3263 | 2.5805 | 0.6676 | 0.6944 | 0.0179 | 0.017 | 0 | 0 |  | Charpente | Chevrons | 2064
Lisse basse | Rez de chaussée | Epicéa C24 | 0.045 | 0.22 | 4.9958 | 2.178 | 2.6478 | 2.6676 | 0.0495 | 0.0495 | 0.2077 | 0.2077 | 0 | MURS RDC | OB015 | 469
latte 27/40 | Premier Etage | Epicéa C24 | 0.04 | 0.024 | 2.0641 | 0.023 | 0.2642 | 0.2661 | 0.002 | 0.002 | 0.0083 | 0.0083 | 0 | MURS ETAGE | OB127 | 659
4 x Solive | Premier Etage | NH II | 0.092 | 0.192 | 3.294 | 3.3915 | 1.871 | 1.9063 | 0.0592 | 0.0582 | 0 | 0 |  | Plancher étage | Solivage_192 | 1029
Montant | Premier Etage | Epicéa C24 | 0.045 | 0.22 | 2.0189 | 2.178 | 1.07 | 1.0898 | 0.02 | 0.02 | 0.0839 | 0.0839 | 0 | MURS ETAGE | OB121 | 425
Panne | Comble et couverture | NH II | 0.16 | 0.2 | 10.3774 | 6.4 | 7.412 | 7.476 | 0.3321 | 0.3221 | 0 | 0 |  | Charpente | Toiture mezzanine | 1534
Chevron | Comble et couverture | NH II | 0.07 | 0.192 | 4.2639 | 2.5805 | 2.184 | 2.2109 | 0.0573 | 0.0559 | 0 | 0 |  | Charpente | Chevrons | 2078
Ceinture | Premier Etage | NH II | 0.092 | 0.22 | 2.2241 | 4.4528 | 1.3765 | 1.417 | 0.045 | 0.0446 | 0 | 0 |  | Plancher étage | Solivage_220 | 1042
Montant | Premier Etage | Epicéa C24 | 0.012 | 0.22 | 0.4622 | 0.5808 | 0.2145 | 0.2197 | 0.0012 | 0.0012 | 0.0051 | 0.0051 | 0 | MURS ETAGE | OB127 | 155
2 x Couvre joint | Rez de chaussée | NH II | 0.027 | 0.105 | 3.06 | 0.2977 | 0.8078 | 0.8135 | 0.0087 | 0.0087 | 0 | 0 |  | Couvre-joint
12 x latte 27/40 | Premier Etage | Epicéa C24 | 0.04 | 0.024 | 1.2078 | 0.023 | 0.1546 | 0.1565 | 0.0012 | 0.0012 | 0.0049 | 0.0049 | 0 | MURS ETAGE | OB11 | 681
Montant | Rez de chaussée | Epicéa C24 | 0.045 | 0.22 | 0.09 | 2.178 | 0.0477 | 0.0675 | 0.0009 | 0.0009 | 0.0037 | 0.0037 | 0 | MURS RDC | OB010 | 344
2 x latte chantier | Rez de chaussée | Epicéa C24 | 0.04 | 0.024 | 2.67 | 0.023 | 0.3418 | 0.3437 | 0.0026 | 0.0026 | 0.0108 | 0.0108 | 0 | MURS RDC | T1 | 837
Montant | Premier Etage | Epicéa C24 | 0.045 | 0.22 | 9.2299 | 2.178 | 4.8919 | 4.9117 | 0.0914 | 0.0914 | 0.3838 | 0.3838 | 0 | MURS ETAGE | OB123 | 486
2 x Montant | Premier Etage | Epicéa C24 | 0.045 | 0.145 | 0.214 | 0.9461 | 0.0813 | 0.0944 | 0.0014 | 0.0014 | 0.0059 | 0.0059 | 0 | MURS ETAGE | OB130 | 213
12 x latte 27/40 | Premier Etage | Epicéa C24 | 0.04 | 0.024 | 1.1761 | 0.023 | 0.1505 | 0.1525 | 0.0011 | 0.0011 | 0.0047 | 0.0047 | 0 | MURS ETAGE | OB123 | 746
Lisse basse traitée | Dalle | Epicéa C24 Traité | 0.045 | 0.22 | 3.48 | 2.178 | 1.8444 | 1.8642 | 0.0345 | 0.0345 | 0 | 0 | 0 | MURS RDC | Ossature RDC | 22
Montant | Premier Etage | Epicéa C24 | 0.045 | 0.22 | 1.5961 | 2.178 | 0.8459 | 0.8657 | 0.0158 | 0.0158 | 0.0664 | 0.0664 | 0 | MURS ETAGE | OB123 | 484
10 x Montant | Comble et couverture | Epicéa C24 | 0.045 | 0.145 | 1.16 | 0.9461 | 0.4408 | 0.4538 | 0.0076 | 0.0076 | 0.0318 | 0.0318 | 0 | MURS COMBLE | OB129 | 257
2 x Chevron | Comble et couverture | NH II | 0.07 | 0.192 | 5.4355 | 2.5805 | 2.7842 | 2.811 | 0.0731 | 0.0713 | 0 | 0 |  | Charpente | Chevrons | 2031
latte 27/40 | Premier Etage | Epicéa C24 | 0.04 | 0.024 | 1.727 | 0.023 | 0.2211 | 0.223 | 0.0017 | 0.0017 | 0.007 | 0.007 | 0 | MURS ETAGE | OB122 | 736
26 x Montant | Premier Etage | Epicéa C24 | 0.045 | 0.22 | 1.0511 | 2.178 | 0.5571 | 0.5769 | 0.0104 | 0.0104 | 0.0437 | 0.0437 | 0 | MURS ETAGE | OB123 | 483
Lisse basse traitée | Dalle | Epicéa C24 Traité | 0.045 | 0.22 | 4.8392 | 2.178 | 2.5521 | 2.5719 | 0.0479 | 0.0477 | 0 | 0 | 0 | MURS RDC | Ossature RDC | 24
Montant | Premier Etage | Epicéa C24 | 0.045 | 0.22 | 0.1964 | 2.178 | 0.0971 | 0.1169 | 0.0019 | 0.0018 | 0.0082 | 0.0074 | 0 | MURS ETAGE | OB12 | 57
Montant | Rez de chaussée | Epicéa C24 | 0.045 | 0.136 | 2.54 | 0.8325 | 0.8771 | 0.8894 | 0.0155 | 0.0143 | 0.0653 | 0.0603 | 0 | MURS RDC | OB024 | 534
Cache moineau | Comble et couverture | NH II | 0.07 | 0.192 | 0.3946 | 2.5805 | 0.1921 | 0.219 | 0.0053 | 0.0047 | 0 | 0 |  | Chevrons | Toiture mezzanine | 2039
latte chantier | Rez de chaussée | Epicéa C24 | 0.04 | 0.024 | 0.3776 | 0.023 | 0.0483 | 0.0503 | 0.0004 | 0.0004 | 0.0015 | 0.0015 | 0 | MURS RDC | M3 | 826
Cache moineau | Comble et couverture | NH II | 0.07 | 0.22 | 0.4732 | 3.388 | 0.2745 | 0.3053 | 0.0073 | 0.0073 | 0 | 0 |  | Chevrons | Toiture habitation | 2005
Cache moineau | Comble et couverture | NH II | 0.07 | 0.22 | 0.413 | 3.388 | 0.2395 | 0.2703 | 0.0064 | 0.0064 | 0 | 0 |  | Chevrons | Toiture habitation | 2004
Lisse basse | Rez de chaussée | Epicéa C24 | 0.045 | 0.22 | 6.5091 | 2.178 | 3.4498 | 3.4696 | 0.0644 | 0.0644 | 0.2707 | 0.2707 | 0 | MURS RDC | OB020 | 154
latte 27/40 | Premier Etage | Epicéa C24 | 0.04 | 0.024 | 0.7666 | 0.023 | 0.0981 | 0.1 | 0.0007 | 0.0007 | 0.0031 | 0.0031 | 0 | MURS ETAGE | OB120 | 705
Montant | Premier Etage | Epicéa C24 | 0.045 | 0.22 | 0.6179 | 2.178 | 0.3275 | 0.3473 | 0.0061 | 0.0061 | 0.0257 | 0.0257 | 0 | MURS ETAGE | OB125 | 529
Montant | Premier Etage | Epicéa C24 | 0.045 | 0.22 | 5.233 | 2.178 | 2.7735 | 2.7933 | 0.0518 | 0.0518 | 0.2176 | 0.2176 | 0 | MURS ETAGE | OB120 | 383
Montant | Rez de chaussée | Epicéa C24 | 0.045 | 0.22 | 0.0948 | 2.178 | 0.0502 | 0.07 | 0.0009 | 0.0009 | 0.0039 | 0.0039 | 0 | MURS RDC | OB011 | 388
Montant | Premier Etage | Epicéa C24 | 0.045 | 0.22 | 9.1399 | 2.178 | 4.8442 | 4.864 | 0.0905 | 0.0905 | 0.38 | 0.38 | 0 | MURS ETAGE | OB123 | 485
2 x Montant | Rez de chaussée | Epicéa C24 | 0.045 | 0.22 | 2.575 | 2.178 | 1.3647 | 1.3845 | 0.0255 | 0.0255 | 0.1071 | 0.1071 | 0 | MURS RDC | OB012 | 412
2 x Montant | Premier Etage | Epicéa C24 | 0.045 | 0.22 | 0.225 | 2.178 | 0.1192 | 0.139 | 0.0022 | 0.0022 | 0.0094 | 0.0094 | 0 | MURS ETAGE | OB127 | 161
Montant | Rez de chaussée | Epicéa C24 | 0.045 | 0.22 | 0.2342 | 2.178 | 0.1241 | 0.1439 | 0.0023 | 0.0023 | 0.0097 | 0.0097 | 0 | MURS RDC | OB011 | 390
Montant | Premier Etage | Epicéa C24 | 0.045 | 0.145 | 1.3598 | 0.9461 | 0.5167 | 0.5298 | 0.0089 | 0.0089 | 0.0373 | 0.0373 | 0 | MURS ETAGE | OB131 | 512
Montant | Rez de chaussée | Epicéa C24 | 0.045 | 0.22 | 2.984 | 2.178 | 1.5815 | 1.6013 | 0.0295 | 0.0295 | 0.1241 | 0.1241 | 0 | MURS RDC | OB02 | 54
Montant | Premier Etage | Epicéa C24 | 0.045 | 0.22 | 0.4492 | 2.178 | 0.2343 | 0.2541 | 0.0044 | 0.0044 | 0.0187 | 0.0183 | 0 | MURS ETAGE | OB17 | 301
2 x Chevron | Comble et couverture | NH II | 0.07 | 0.192 | 3.7864 | 2.5805 | 1.8755 | 1.9023 | 0.0509 | 0.0473 | 0 | 0 |  | Charpente | Chevrons | 2113
Lisse basse | Premier Etage | Epicéa C24 | 0.045 | 0.22 | 5.35 | 2.178 | 2.8355 | 2.8553 | 0.053 | 0.053 | 0.2225 | 0.2225 | 0 | Plancher étage | ETA | 48
Couvre joint | Rez de chaussée | NH II | 0.027 | 0.0752 | 3.9386 | 0.1527 | 0.7662 | 0.7703 | 0.008 | 0.0073 | 0 | 0 |  | Couvre-joint
5 x Montant | Premier Etage | Epicéa C24 | 0.045 | 0.22 | 0.3808 | 2.178 | 0.1916 | 0.2114 | 0.0038 | 0.0035 | 0.0158 | 0.0148 | 0 | MURS ETAGE | OB122 | 446
2 x Cache moineau | Comble et couverture | NH II | 0.07 | 0.22 | 0.4804 | 3.388 | 0.2786 | 0.3094 | 0.0074 | 0.0074 | 0 | 0 |  | Chevrons | Toiture habitation | 2009
Chevron | Comble et couverture | NH II | 0.07 | 0.192 | 2.8389 | 2.5805 | 1.4204 | 1.4473 | 0.0382 | 0.0361 | 0 | 0 |  | Charpente | Chevrons | 2072
2 x Montant | Rez de chaussée | Epicéa C24 | 0.045 | 0.22 | 2.385 | 2.178 | 1.264 | 1.2838 | 0.0236 | 0.0236 | 0.0992 | 0.0992 | 0 | MURS RDC | OB09 | 330
contre poutre | Premier Etage | NH II | 0.027 | 0.165 | 4.5138 | 0.7351 | 1.7333 | 1.7422 | 0.0201 | 0.0201 | 0 | 0 |  | Plancher étage
Montant | Rez de chaussée | Epicéa C24 | 0.017 | 0.22 | 1.64 | 0.8228 | 0.7774 | 0.7848 | 0.0061 | 0.0061 | 0.0258 | 0.0258 | 0 | MURS RDC | OB08 | 308
Montant | Premier Etage | Epicéa C24 | 0.012 | 0.22 | 0.4622 | 0.5808 | 0.2145 | 0.2197 | 0.0012 | 0.0012 | 0.0051 | 0.0051 | 0 | MURS ETAGE | OB12 | 55
Montant | Rez de chaussée | Epicéa C24 | 0.045 | 0.22 | 2.385 | 2.178 | 1.264 | 1.2839 | 0.0236 | 0.0236 | 0.0992 | 0.0992 | 0 | MURS RDC | OB08 | 312
2 x Montant | Rez de chaussée | Epicéa C24 | 0.045 | 0.22 | 1.223 | 2.178 | 0.6482 | 0.668 | 0.0121 | 0.0121 | 0.0509 | 0.0509 | 0 | MURS RDC | OB017 | 523
2 x Montant | Rez de chaussée | Epicéa C24 | 0.045 | 0.22 | 0.218 | 2.178 | 0.1155 | 0.1353 | 0.0022 | 0.0022 | 0.0091 | 0.0091 | 0 | MURS RDC | OB04 | 82
Montant | Premier Etage | Epicéa C24 | 0.045 | 0.145 | 2.4756 | 0.9461 | 0.9371 | 0.9502 | 0.0162 | 0.0161 | 0.0678 | 0.0675 | 0 | MURS ETAGE | OB130 | 233
Montant | Rez de chaussée | Epicéa C24 | 0.045 | 0.22 | 2.385 | 2.178 | 1.2641 | 1.2839 | 0.0236 | 0.0236 | 0.0992 | 0.0992 | 0 | MURS RDC | OB08 | 312
2 x Blochets | Premier Etage | NH II | 0.092 | 0.192 | 1.1851 | 3.3915 | 0.6546 | 0.6899 | 0.0209 | 0.0195 | 0 | 0 |  | Charpente | F01 | 1503
2 x Montant | Rez de chaussée | Epicéa C24 | 0.045 | 0.22 | 2.17 | 2.178 | 1.1501 | 1.1699 | 0.0215 | 0.0215 | 0.0902 | 0.0902 | 0 | MURS RDC | OB020 | 151
4 x Montant | Rez de chaussée | Epicéa C24 | 0.045 | 0.22 | 0.24 | 2.178 | 0.1272 | 0.147 | 0.0024 | 0.0024 | 0.01 | 0.01 | 0 | MURS RDC | OB017 | 521
2 x Montant | Premier Etage | Epicéa C24 | 0.045 | 0.22 | 1.0569 | 2.178 | 0.5462 | 0.566 | 0.0105 | 0.0101 | 0.0439 | 0.0424 | 0 | MURS ETAGE | OB12 | 62
2 x latte chantier | Rez de chaussée | Epicéa C24 | 0.04 | 0.024 | 2.67 | 0.023 | 0.3418 | 0.3437 | 0.0026 | 0.0026 | 0.0108 | 0.0108 | 0 | MURS RDC | T2 | 838
2 x Lisse basse | Premier Etage | Epicéa C24 | 0.045 | 0.22 | 3.424 | 2.178 | 1.8147 | 1.8345 | 0.0339 | 0.0339 | 0.1424 | 0.1424 | 0 | Plancher étage | ETA | 44
2 x Montant | Rez de chaussée | Epicéa C24 | 0.045 | 0.22 | 1.53 | 2.178 | 0.8109 | 0.8307 | 0.0151 | 0.0151 | 0.0636 | 0.0636 | 0 | MURS RDC | OB017 | 524
Montant | Rez de chaussée | Epicéa C24 | 0.045 | 0.22 | 3.028 | 2.178 | 1.6048 | 1.6246 | 0.03 | 0.03 | 0.1259 | 0.1259 | 0 | MURS RDC | OB04 | 86
Montant | Rez de chaussée | Epicéa C24 | 0.045 | 0.22 | 2.575 | 2.178 | 1.3648 | 1.3845 | 0.0255 | 0.0255 | 0.1071 | 0.1071 | 0 | MURS RDC | OB013 | 438
Chevron | Comble et couverture | NH II | 0.07 | 0.192 | 2.7443 | 2.5805 | 1.3523 | 1.3791 | 0.0369 | 0.0344 | 0 | 0 |  | Charpente | Chevrons | 2017
Solive | Premier Etage | NH II | 0.092 | 0.192 | 3.2655 | 3.3915 | 1.8548 | 1.8901 | 0.0582 | 0.0577 | 0 | 0 |  | Plancher étage | Solivage_192 | 1028
2 x Montant | Rez de chaussée | Epicéa C24 | 0.045 | 0.22 | 1.223 | 2.178 | 0.6482 | 0.668 | 0.0121 | 0.0121 | 0.0509 | 0.0509 | 0 | MURS RDC | OB015 | 467
5 x Montant | Rez de chaussée | Epicéa C24 | 0.045 | 0.22 | 0.917 | 2.178 | 0.486 | 0.5058 | 0.0091 | 0.0091 | 0.0381 | 0.0381 | 0 | MURS RDC | OB02 | 50
2 x latte 27/40 | Rez de chaussée | Epicéa C24 | 0.04 | 0.024 | 2.74 | 0.023 | 0.3507 | 0.3526 | 0.0026 | 0.0026 | 0.011 | 0.011 | 0 | MURS RDC | OB018 | 755
Montant | Rez de chaussée | Epicéa C24 | 0.045 | 0.22 | 4.9958 | 2.178 | 2.6478 | 2.6676 | 0.0495 | 0.0495 | 0.2077 | 0.2077 | 0 | MURS RDC | OB015 | 469
3 x latte 27/40 | Rez de chaussée | Epicéa C24 | 0.04 | 0.024 | 0.147 | 0.023 | 0.0188 | 0.0207 | 0.0001 | 0.0001 | 0.0006 | 0.0006 | 0 | MURS RDC | OB08 | 692
Montant | Premier Etage | Epicéa C24 | 0.045 | 0.145 | 2.5019 | 0.9461 | 0.9471 | 0.9601 | 0.0163 | 0.0162 | 0.0686 | 0.0682 | 0 | MURS ETAGE | OB130 | 234
Montant | Rez de chaussée | Epicéa C24 | 0.045 | 0.1414 | 2.54 | 0.8999 | 0.8843 | 0.897 | 0.0162 | 0.014 | 0.0679 | 0.0588 | 0 | MURS RDC | OB07 | 285
Solive | Premier Etage | NH II | 0.092 | 0.192 | 6.43 | 3.3915 | 3.6522 | 3.6876 | 0.1146 | 0.1136 | 0 | 0 |  | Plancher étage | Solivage_192 | 1033
4 x Montant | Rez de chaussée | Epicéa C24 | 0.045 | 0.22 | 2.0356 | 2.178 | 1.0789 | 1.0987 | 0.0202 | 0.0202 | 0.0846 | 0.0846 | 0 | MURS RDC | OB020 | 150
Montant | Rez de chaussée | Epicéa C24 | 0.045 | 0.145 | 3.059 | 0.9461 | 1.1624 | 1.1755 | 0.02 | 0.02 | 0.0838 | 0.0838 | 0 | MURS RDC | OB022 | 119
Montant | Premier Etage | Epicéa C24 | 0.045 | 0.22 | 0.6612 | 2.178 | 0.3453 | 0.3651 | 0.0065 | 0.0064 | 0.0275 | 0.027 | 0 | MURS ETAGE | OB121 | 422
Montant | Premier Etage | Epicéa C24 | 0.045 | 0.145 | 0.555 | 0.9461 | 0.2021 | 0.2152 | 0.0036 | 0.0033 | 0.0152 | 0.014 | 0 | MURS ETAGE | OB130 | 217
2 x latte chantier | Rez de chaussée | Epicéa C24 | 0.04 | 0.024 | 2.698 | 0.023 | 0.3453 | 0.3473 | 0.0026 | 0.0026 | 0.0109 | 0.0109 | 0 | MURS RDC | OB02 | 800
Montant | Premier Etage | Epicéa C24 | 0.045 | 0.145 | 0.555 | 0.9461 | 0.2109 | 0.2239 | 0.0036 | 0.0036 | 0.0152 | 0.0152 | 0 | MURS ETAGE | OB130 | 216
5 x Montant | Rez de chaussée | Epicéa C24 | 0.045 | 0.145 | 2.67 | 0.9461 | 1.0146 | 1.0277 | 0.0174 | 0.0174 | 0.0732 | 0.0732 | 0 | MURS RDC | OB022 | 118
Montant | Rez de chaussée | Epicéa C24 | 0.045 | 0.22 | 1.3901 | 2.178 | 0.7368 | 0.7566 | 0.0138 | 0.0138 | 0.0578 | 0.0578 | 0 | MURS RDC | OB019 | 477
Montant | Rez de chaussée | Epicéa C24 | 0.045 | 0.145 | 2.665 | 0.9461 | 0.976 | 0.9891 | 0.0174 | 0.0164 | 0.073 | 0.0689 | 0 | MURS RDC | OB013 | 431
2 x Chevron | Comble et couverture | NH II | 0.07 | 0.192 | 1.2661 | 2.5805 | 0.636 | 0.6629 | 0.0171 | 0.0162 | 0 | 0 |  | Charpente | Chevrons | 2063
Montant | Premier Etage | Epicéa C24 | 0.045 | 0.22 | 7.794 | 2.178 | 4.1308 | 4.1506 | 0.0772 | 0.0772 | 0.3241 | 0.3241 | 0 | MURS ETAGE | OB11 | 267
2 x Chevron | Comble et couverture | NH II | 0.07 | 0.192 | 1.2662 | 2.5805 | 0.6361 | 0.663 | 0.0171 | 0.0162 | 0 | 0 |  | Charpente | Chevrons | 2065
Chevron | Comble et couverture | NH II | 0.07 | 0.192 | 4.1078 | 2.5805 | 2.0611 | 2.088 | 0.0552 | 0.0525 | 0 | 0 |  | Charpente | Chevrons | 2023
Enrayure | Dalle | NH II | 0.188 | 0.5 | 1.4915 | 47 | 1.9607 | 2.1487 | 0.1402 | 0.1329 | 0 | 0 |  | Maçonnerie
Montant | Premier Etage | Epicéa C24 | 0.045 | 0.22 | 0.5962 | 2.178 | 0.316 | 0.3358 | 0.0059 | 0.0059 | 0.0248 | 0.0248 | 0 | MURS ETAGE | OB124 | 517
2 x Montant | Premier Etage | Epicéa C24 | 0.045 | 0.145 | 6.3432 | 0.9461 | 2.4104 | 2.4235 | 0.0414 | 0.0414 | 0.1738 | 0.1738 | 0 | MURS ETAGE | OB129 | 253
Montant | Premier Etage | Epicéa C24 | 0.045 | 0.22 | 1.437 | 2.178 | 0.7547 | 0.7745 | 0.0142 | 0.014 | 0.0598 | 0.059 | 0 | MURS COMBLE | OB14 | 111
Montant | Comble et couverture | Epicéa C24 | 0.045 | 0.145 | 0.0918 | 0.9461 | 0.0349 | 0.0479 | 0.0006 | 0.0006 | 0.0025 | 0.0025 | 0 | MURS COMBLE | OB128 | 135
Montant | Premier Etage | Epicéa C24 | 0.045 | 0.145 | 1.2824 | 0.9461 | 0.4837 | 0.4967 | 0.0084 | 0.0083 | 0.0351 | 0.0348 | 0 | MURS ETAGE | OB130 | 223
Montant | Premier Etage | Epicéa C24 | 0.045 | 0.145 | 0.274 | 0.9461 | 0.1041 | 0.1172 | 0.0018 | 0.0018 | 0.0075 | 0.0075 | 0 | MURS ETAGE | OB131 | 496
4 x Montant | Premier Etage | Epicéa C24 | 0.045 | 0.22 | 0.923 | 2.178 | 0.4892 | 0.509 | 0.0091 | 0.0091 | 0.0384 | 0.0384 | 0 | MURS ETAGE | OB127 | 168
Montant | Premier Etage | Epicéa C24 | 0.045 | 0.22 | 1.4968 | 2.178 | 0.7933 | 0.8131 | 0.0148 | 0.0148 | 0.0622 | 0.0622 | 0 | MURS COMBLE | OB12 | 77
Montant | Premier Etage | Epicéa C24 | 0.045 | 0.22 | 0.2419 | 2.178 | 0.1282 | 0.148 | 0.0024 | 0.0024 | 0.0101 | 0.0101 | 0 | MURS ETAGE | OB120 | 358
contre poutre | Premier Etage | NH II | 0.027 | 0.165 | 2.3395 | 0.7351 | 0.8984 | 0.9073 | 0.0104 | 0.0104 | 0 | 0 |  | Plancher étage
Enrayure | Dalle | NH II | 0.2 | 0.5 | 9.1869 | 50 | 12.6817 | 12.8817 | 0.9187 | 0.8614 | 0 | 0 |  | Maçonnerie
latte chantier | Rez de chaussée | Epicéa C24 | 0.04 | 0.024 | 2.698 | 0.023 | 0.3453 | 0.3473 | 0.0026 | 0.0026 | 0.0109 | 0.0109 | 0 | MURS RDC | OB03 | 811
Lisse basse | Rez de chaussée | Epicéa C24 | 0.045 | 0.145 | 2.4835 | 0.9461 | 0.9437 | 0.9568 | 0.0162 | 0.0162 | 0.0681 | 0.0681 | 0 | MURS RDC | OB025 | 203
Chevron | Comble et couverture | NH II | 0.07 | 0.192 | 4.2639 | 2.5805 | 2.184 | 2.2109 | 0.0573 | 0.0559 | 0 | 0 |  | Charpente | Chevrons | 2080
2 x Arbalétrier | Rez de chaussée | NH II | 0.16 | 0.24 | 3.8499 | 9.216 | 2.9358 | 3.0126 | 0.1478 | 0.1377 | 0 | 0 |  | Charpente | Ferme Garage | 1513
Montant | Premier Etage | Epicéa C24 | 0.045 | 0.22 | 1.5385 | 2.178 | 0.8154 | 0.8352 | 0.0152 | 0.0152 | 0.064 | 0.064 | 0 | MURS ETAGE | OB127 | 182
Montant | Premier Etage | Epicéa C24 | 0.045 | 0.22 | 0.5962 | 2.178 | 0.316 | 0.3358 | 0.0059 | 0.0059 | 0.0248 | 0.0248 | 0 | MURS ETAGE | OB126 | 540
Chevron | Comble et couverture | NH II | 0.07 | 0.192 | 4.434 | 2.5805 | 2.2561 | 2.283 | 0.0596 | 0.0576 | 0 | 0 |  | Charpente | Chevrons | 2083
latte chantier | Rez de chaussée | Epicéa C24 | 0.04 | 0.024 | 1.4403 | 0.023 | 0.1844 | 0.1863 | 0.0014 | 0.0014 | 0.0058 | 0.0058 | 0 | MURS RDC | P2 | 831
Montant | Premier Etage | Epicéa C24 | 0.045 | 0.145 | 0.8312 | 0.9461 | 0.3076 | 0.3206 | 0.0054 | 0.0052 | 0.0228 | 0.0217 | 0 | MURS ETAGE | OB131 | 498
Montant | Premier Etage | Epicéa C24 | 0.045 | 0.22 | 0.6998 | 2.178 | 0.3639 | 0.3837 | 0.0069 | 0.0067 | 0.0291 | 0.0283 | 0 | MURS ETAGE | OB12 | 61
Montant | Rez de chaussée | Epicéa C24 | 0.045 | 0.1445 | 2.54 | 0.9394 | 0.8999 | 0.9129 | 0.0165 | 0.0144 | 0.0694 | 0.0603 | 0 | MURS RDC | OB07 | 286
3 x latte 27/40 | Premier Etage | Epicéa C24 | 0.04 | 0.024 | 0.13 | 0.023 | 0.0166 | 0.0186 | 0.0001 | 0.0001 | 0.0005 | 0.0005 | 0 | MURS ETAGE | OB127 | 637
Montant | Premier Etage | Epicéa C24 | 0.045 | 0.22 | 2.2189 | 2.178 | 1.1658 | 1.1856 | 0.022 | 0.0217 | 0.0923 | 0.0912 | 0 | MURS ETAGE | OB122 | 453
latte 27/40 | Rez de chaussée | Epicéa C24 | 0.04 | 0.024 | 0.415 | 0.023 | 0.0531 | 0.055 | 0.0004 | 0.0004 | 0.0017 | 0.0017 | 0 | MURS RDC | OB019 | 742
Montant | Premier Etage | Epicéa C24 | 0.045 | 0.22 | 0.1672 | 2.178 | 0.0816 | 0.1014 | 0.0017 | 0.0015 | 0.007 | 0.0062 | 0 | MURS ETAGE | OB127 | 159
Montant | Rez de chaussée | Epicéa C24 | 0.045 | 0.22 | 2.385 | 2.178 | 1.264 | 1.2838 | 0.0236 | 0.0236 | 0.0992 | 0.0992 | 0 | MURS RDC | OB07 | 293
Montant | Rez de chaussée | Epicéa C24 | 0.045 | 0.145 | 1.6186 | 0.9461 | 0.6151 | 0.6281 | 0.0106 | 0.0106 | 0.0444 | 0.0444 | 0 | MURS RDC | OB024 | 535
Montant | Premier Etage | Epicéa C24 | 0.045 | 0.22 | 0.3262 | 2.178 | 0.1729 | 0.1927 | 0.0032 | 0.0032 | 0.0136 | 0.0136 | 0 | MURS ETAGE | OB120 | 360
2 x Montant | Premier Etage | Epicéa C24 | 0.045 | 0.22 | 1.6907 | 2.178 | 0.8961 | 0.9159 | 0.0167 | 0.0167 | 0.0703 | 0.0703 | 0 | MURS ETAGE | OB127 | 174
Montant | Premier Etage | Epicéa C24 | 0.045 | 0.22 | 0.211 | 2.178 | 0.1049 | 0.1247 | 0.0021 | 0.0019 | 0.0088 | 0.008 | 0 | MURS COMBLE | OB127 | 185
4 x Montant | Premier Etage | Epicéa C24 | 0.045 | 0.145 | 0.3483 | 0.9461 | 0.1324 | 0.1454 | 0.0023 | 0.0023 | 0.0095 | 0.0095 | 0 | MURS ETAGE | OB128 | 128
latte 27/40 | Premier Etage | Epicéa C24 | 0.04 | 0.024 | 0.7667 | 0.023 | 0.0981 | 0.1001 | 0.0007 | 0.0007 | 0.0031 | 0.0031 | 0 | MURS ETAGE | OB12 | 605
Enrayure | Dalle | NH II | 0.2 | 0.5 | 2.8055 | 50 | 3.8312 | 4.0312 | 0.2806 | 0.2592 | 0 | 0 |  | Maçonnerie
Montant | Premier Etage | Epicéa C24 | 0.045 | 0.22 | 0.84 | 2.178 | 0.4452 | 0.465 | 0.0083 | 0.0083 | 0.0349 | 0.0349 | 0 | MURS ETAGE | OB14 | 95
Cache moineau | Comble et couverture | NH II | 0.07 | 0.22 | 0.9537 | 3.388 | 0.4709 | 0.5017 | 0.0147 | 0.0122 | 0 | 0 |  | Chevrons | Toiture mezzanine | 2054
2 x Montant | Rez de chaussée | Epicéa C24 | 0.045 | 0.22 | 2.575 | 2.178 | 1.3647 | 1.3846 | 0.0255 | 0.0255 | 0.1071 | 0.1071 | 0 | MURS RDC | OB013 | 438
Montant | Comble et couverture | Epicéa C24 | 0.045 | 0.145 | 1.4861 | 0.9461 | 0.5647 | 0.5778 | 0.0097 | 0.0097 | 0.0407 | 0.0407 | 0 | MURS COMBLE | OB128 | 140
Lisse basse | Premier Etage | Epicéa C24 | 0.045 | 0.22 | 1.6294 | 2.178 | 0.8224 | 0.8422 | 0.0161 | 0.0153 | 0.0678 | 0.0644 | 0 | Plancher étage | ETA | 38
Montant | Premier Etage | Epicéa C24 | 0.023 | 0.22 | 0.84 | 1.1132 | 0.4082 | 0.4184 | 0.0043 | 0.0043 | 0.0179 | 0.0179 | 0 | MURS ETAGE | OB14 | 88
Lisse basse | Rez de chaussée | Epicéa C24 | 0.045 | 0.22 | 2.984 | 2.178 | 1.5815 | 1.6013 | 0.0295 | 0.0295 | 0.1241 | 0.1241 | 0 | MURS RDC | OB02 | 54
Montant | Rez de chaussée | Epicéa C24 | 0.045 | 0.145 | 2.935 | 0.9461 | 1.0664 | 1.0795 | 0.0192 | 0.0178 | 0.0804 | 0.0746 | 0 | MURS RDC | OB010 | 386
Lisse basse | Rez de chaussée | Epicéa C24 | 0.045 | 0.22 | 1.3208 | 2.178 | 0.7 | 0.7198 | 0.0131 | 0.0131 | 0.0549 | 0.0549 | 0 | MURS RDC | OB03 | 241
Cheminée | Rez de chaussée | NH II | 0.47 | 0.47 | 4.1756 | 103.823 | 7.8501 | 8.2919 | 0.9224 | 0.9224 | 0 | 0 |  | Maçonnerie
Chevron | Comble et couverture | NH II | 0.092 | 0.192 | 4.264 | 3.3915 | 2.3683 | 2.4037 | 0.0753 | 0.0735 | 0 | 0 |  | Charpente | Chevrons | 2093
Enrayure | Dalle | NH II | 0.188 | 0.5 | 6.7291 | 47 | 9.2329 | 9.4209 | 0.6325 | 0.6306 | 0 | 0 |  | Maçonnerie
Chevron | Comble et couverture | NH II | 0.07 | 0.192 | 2.2494 | 2.5805 | 1.1009 | 1.1278 | 0.0302 | 0.0276 | 0 | 0 |  | Charpente | Chevrons | 2108
2 x Montant | Premier Etage | Epicéa C24 | 0.045 | 0.22 | 2.391 | 2.178 | 1.2672 | 1.287 | 0.0237 | 0.0237 | 0.0994 | 0.0994 | 0 | MURS ETAGE | OB14 | 103
Montant | Rez de chaussée | Epicéa C24 | 0.045 | 0.22 | 2.385 | 2.178 | 1.2641 | 1.2839 | 0.0236 | 0.0236 | 0.0992 | 0.0992 | 0 | MURS RDC | OB013 | 437
Montant | Premier Etage | Epicéa C24 | 0.045 | 0.145 | 2.5743 | 0.9461 | 0.9782 | 0.9913 | 0.0168 | 0.0168 | 0.0705 | 0.0705 | 0 | MURS ETAGE | OB131 | 510
2 x Lisse basse traitée | Dalle | Epicéa C24 Traité | 0.045 | 0.22 | 3.424 | 2.178 | 1.8147 | 1.8345 | 0.0339 | 0.0339 | 0 | 0 | 0 | MURS RDC | Ossature RDC | 21
latte chantier | Rez de chaussée | Epicéa C24 | 0.04 | 0.024 | 1.0247 | 0.023 | 0.1312 | 0.1331 | 0.001 | 0.001 | 0.0041 | 0.0041 | 0 | MURS RDC | J2 | 819
11 x Chevron | Comble et couverture | NH II | 0.07 | 0.165 | 4.2823 | 1.9057 | 1.9636 | 1.9867 | 0.0495 | 0.0481 | 0 | 0 |  | Charpente | Chevrons | 2000
Linteau | Comble et couverture | Epicéa C24 | 0.14 | 0.14 | 0.87 | 2.744 | 0.484 | 0.5232 | 0.0171 | 0.017 | 0.0716 | 0.0714 | 0 | Charpente | OB131 | 1540
3 x latte 27/40 | Premier Etage | Epicéa C24 | 0.04 | 0.024 | 1.8756 | 0.023 | 0.2401 | 0.242 | 0.0018 | 0.0018 | 0.0076 | 0.0076 | 0 | MURS ETAGE | OB127 | 657
Montant | Premier Etage | Epicéa C24 | 0.045 | 0.2036 | 0.27 | 1.8658 | 0.1299 | 0.1482 | 0.0025 | 0.0024 | 0.0104 | 0.01 | 0 | MURS ETAGE | OB121 | 417
Enrayure | Dalle | NH II | 0.2 | 0.5 | 6.1712 | 50 | 8.6138 | 8.8138 | 0.6171 | 0.6022 | 0 | 0 |  | Maçonnerie
Enrayure | Dalle | NH II | 0.188 | 0.5 | 1.6178 | 47 | 2.1474 | 2.3354 | 0.1521 | 0.1421 | 0 | 0 |  | Maçonnerie
Montant | Premier Etage | Epicéa C24 | 0.045 | 0.22 | 1.7611 | 2.178 | 0.9334 | 0.9532 | 0.0174 | 0.0174 | 0.0732 | 0.0732 | 0 | MURS ETAGE | OB12 | 69
Montant | Premier Etage | Epicéa C24 | 0.045 | 0.22 | 1.518 | 2.178 | 0.8046 | 0.8244 | 0.015 | 0.015 | 0.0631 | 0.0631 | 0 | MURS COMBLE | OB127 | 196
Lisse basse traitée | Dalle | Epicéa C24 Traité | 0.045 | 0.22 | 2.1858 | 2.178 | 1.1585 | 1.1783 | 0.0216 | 0.0216 | 0 | 0 | 0 | MURS RDC | Ossature RDC | 14
Montant | Rez de chaussée | Epicéa C24 | 0.045 | 0.22 | 7.884 | 2.178 | 4.1785 | 4.1983 | 0.0781 | 0.0781 | 0.3278 | 0.3278 | 0 | MURS RDC | OB01 | 263
Montant | Rez de chaussée | Epicéa C24 | 0.045 | 0.1122 | 2.665 | 0.5669 | 0.8014 | 0.8115 | 0.0135 | 0.0125 | 0.0565 | 0.0524 | 0 | MURS RDC | OB012 | 402
Enrayure | Dalle | NH II | 0.188 | 0.5 | 2.4876 | 47 | 3.3409 | 3.5289 | 0.2338 | 0.2274 | 0 | 0 |  | Maçonnerie
2 x Montant | Rez de chaussée | Epicéa C24 | 0.045 | 0.22 | 0.218 | 2.178 | 0.1155 | 0.1353 | 0.0022 | 0.0022 | 0.0091 | 0.0091 | 0 | MURS RDC | OB020 | 145
Enrayure | Dalle | NH II | 0.2 | 0.5 | 5.5682 | 50 | 7.7213 | 7.9213 | 0.5568 | 0.5474 | 0 | 0 |  | Maçonnerie
Montant | Rez de chaussée | Epicéa C24 | 0.045 | 0.22 | 1.7489 | 2.178 | 0.9269 | 0.9467 | 0.0173 | 0.0173 | 0.0727 | 0.0727 | 0 | MURS RDC | OB013 | 434
Montant | Rez de chaussée | Epicéa C24 | 0.045 | 0.22 | 0.94 | 2.178 | 0.4982 | 0.518 | 0.0093 | 0.0093 | 0.0391 | 0.0391 | 0 | MURS RDC | OB07 | 290
Enrayure | Dalle | NH II | 0.188 | 0.5 | 4.5225 | 47 | 6.1025 | 6.2905 | 0.4251 | 0.4148 | 0 | 0 |  | Maçonnerie
Enrayure | Dalle | NH II | 0.188 | 0.5 | 3.424 | 47 | 4.7114 | 4.8994 | 0.3219 | 0.3219 | 0 | 0 |  | Maçonnerie
Montant | Premier Etage | Epicéa C24 | 0.045 | 0.22 | 3.194 | 2.178 | 1.6928 | 1.7126 | 0.0316 | 0.0316 | 0.1328 | 0.1328 | 0 | MURS ETAGE | OB125 | 530
6 x Montant | Premier Etage | Epicéa C24 | 0.045 | 0.22 | 0.9186 | 2.178 | 0.4869 | 0.5067 | 0.0091 | 0.0091 | 0.0382 | 0.0382 | 0 | MURS ETAGE | OB16 | 279
16 x Montant | Rez de chaussée | Epicéa C24 | 0.045 | 0.145 | 2.478 | 0.9461 | 0.9416 | 0.9547 | 0.0162 | 0.0162 | 0.0679 | 0.0679 | 0 | MURS RDC | OB021 | 245
Montant | Rez de chaussée | Epicéa C24 | 0.045 | 0.145 | 2.6107 | 0.9461 | 0.992 | 1.0051 | 0.017 | 0.017 | 0.0715 | 0.0715 | 0 | MURS RDC | OB026 | 490
Montant | Rez de chaussée | Epicéa C24 | 0.017 | 0.22 | 0.94 | 0.8228 | 0.4456 | 0.453 | 0.0035 | 0.0035 | 0.0148 | 0.0148 | 0 | MURS RDC | OB09 | 325
Chevron | Comble et couverture | NH II | 0.07 | 0.192 | 4.274 | 2.5805 | 2.1893 | 2.2162 | 0.0574 | 0.0561 | 0 | 0 |  | Charpente | Chevrons | 2082
Montant | Rez de chaussée | Epicéa C24 | 0.045 | 0.22 | 1.3208 | 2.178 | 0.7 | 0.7198 | 0.0131 | 0.0131 | 0.0549 | 0.0549 | 0 | MURS RDC | OB03 | 241
2 x Montant | Premier Etage | Epicéa C24 | 0.045 | 0.22 | 0.93 | 2.178 | 0.4929 | 0.5127 | 0.0092 | 0.0092 | 0.0387 | 0.0387 | 0 | MURS ETAGE | OB14 | 97
Montant | Rez de chaussée | Epicéa C24 | 0.017 | 0.22 | 1.7489 | 0.8228 | 0.829 | 0.8365 | 0.0065 | 0.0065 | 0.0275 | 0.0275 | 0 | MURS RDC | OB013 | 433
Enrayure | Dalle | NH II | 0.2 | 0.5 | 7.508 | 50 | 10.4893 | 10.6893 | 0.7508 | 0.7353 | 0 | 0 |  | Maçonnerie
Montant | Rez de chaussée | Epicéa C24 | 0.045 | 0.22 | 1.165 | 2.178 | 0.6175 | 0.6373 | 0.0115 | 0.0115 | 0.0484 | 0.0484 | 0 | MURS RDC | OB09 | 329
latte 27/40 | Rez de chaussée | Epicéa C24 | 0.04 | 0.024 | 2.595 | 0.023 | 0.3322 | 0.3341 | 0.0025 | 0.0025 | 0.0105 | 0.0105 | 0 | MURS RDC | OB03 | 671
Lisse basse traitée | Dalle | Epicéa C24 Traité | 0.045 | 0.22 | 0.8808 | 2.178 | 0.4668 | 0.4866 | 0.0087 | 0.0087 | 0 | 0 | 0 | MURS RDC | Ossature RDC | 9
2 x latte 27/40 | Comble et couverture | Epicéa C24 | 0.04 | 0.024 | 1.3669 | 0.023 | 0.175 | 0.1769 | 0.0013 | 0.0013 | 0.0055 | 0.0055 | 0 | MURS COMBLE | OB13 | 675
Solive | Premier Etage | NH II | 0.092 | 0.192 | 6.43 | 3.3915 | 3.6522 | 3.6876 | 0.1146 | 0.1136 | 0 | 0 |  | Plancher étage | Solivage_192 | 1034
Lisse basse | Rez de chaussée | Epicéa C24 | 0.045 | 0.22 | 2.0189 | 2.178 | 1.07 | 1.0898 | 0.02 | 0.02 | 0.0839 | 0.0839 | 0 | MURS RDC | OB012 | 410
Enrayure | Dalle | NH II | 0.188 | 0.5 | 3.0598 | 47 | 4.2103 | 4.3983 | 0.2876 | 0.2876 | 0 | 0 |  | Maçonnerie
Montant | Comble et couverture | Epicéa C24 | 0.045 | 0.145 | 1.4412 | 0.9461 | 0.5476 | 0.5607 | 0.0094 | 0.0094 | 0.0395 | 0.0395 | 0 | MURS COMBLE | OB128 | 139
latte 27/40 | Premier Etage | Epicéa C24 | 0.04 | 0.024 | 1.1939 | 0.023 | 0.1528 | 0.1547 | 0.0011 | 0.0011 | 0.0048 | 0.0048 | 0 | MURS ETAGE | OB120 | 711
4 x latte 27/40 | Rez de chaussée | Epicéa C24 | 0.04 | 0.024 | 2.67 | 0.023 | 0.3418 | 0.3437 | 0.0026 | 0.0026 | 0.0108 | 0.0108 | 0 | MURS RDC | OB09 | 699
2 x Lisse basse | Premier Etage | Epicéa C24 | 0.045 | 0.22 | 0.8282 | 2.178 | 0.439 | 0.4588 | 0.0082 | 0.0082 | 0.0344 | 0.0344 | 0 | Plancher étage | ETA | 34
Montant | Premier Etage | Epicéa C24 | 0.045 | 0.22 | 1.3147 | 2.178 | 0.6893 | 0.7091 | 0.013 | 0.0129 | 0.0547 | 0.054 | 0 | MURS ETAGE | OB17 | 307
Montant | Premier Etage | Epicéa C24 | 0.012 | 0.22 | 0.4051 | 0.5808 | 0.188 | 0.1932 | 0.0011 | 0.0011 | 0.0045 | 0.0045 | 0 | MURS ETAGE | OB124 | 515
Lisse basse traitée | Dalle | Epicéa C24 Traité | 0.045 | 0.22 | 0.7186 | 2.178 | 0.3809 | 0.4007 | 0.0071 | 0.0071 | 0 | 0 | 0 | MURS RDC | Ossature RDC | 8
Chevron | Comble et couverture | NH II | 0.07 | 0.192 | 5.0651 | 2.5805 | 2.5868 | 2.6137 | 0.0681 | 0.0661 | 0 | 0 |  | Charpente | Chevrons | 2089
3 x Montant | Rez de chaussée | Epicéa C24 | 0.045 | 0.145 | 1.8389 | 0.9461 | 0.6988 | 0.7118 | 0.012 | 0.012 | 0.0504 | 0.0504 | 0 | MURS RDC | OB012 | 404
Montant | Rez de chaussée | Epicéa C24 | 0.045 | 0.22 | 0.9386 | 2.178 | 0.4975 | 0.5173 | 0.0093 | 0.0093 | 0.039 | 0.039 | 0 | MURS RDC | OB05 | 200
Montant | Comble et couverture | Epicéa C24 | 0.045 | 0.145 | 0.5696 | 0.9461 | 0.2113 | 0.2243 | 0.0037 | 0.0036 | 0.0156 | 0.0151 | 0 | MURS COMBLE | OB128 | 137
2 x contre poutre | Premier Etage | NH II | 0.027 | 0.165 | 0.6452 | 0.7351 | 0.2478 | 0.2567 | 0.0029 | 0.0029 | 0 | 0 |  | Plancher étage
Montant | Rez de chaussée | Epicéa C24 | 0.045 | 0.145 | 2.54 | 0.9461 | 0.9228 | 0.9358 | 0.0166 | 0.0154 | 0.0696 | 0.0646 | 0 | MURS RDC | OB019 | 472
latte chantier | Rez de chaussée | Epicéa C24 | 0.04 | 0.024 | 2.2585 | 0.023 | 0.2891 | 0.291 | 0.0022 | 0.0022 | 0.0091 | 0.0091 | 0 | MURS RDC | D1 | 808
latte 27/40 | Premier Etage | Epicéa C24 | 0.04 | 0.024 | 1.727 | 0.023 | 0.2211 | 0.223 | 0.0017 | 0.0017 | 0.007 | 0.007 | 0 | MURS ETAGE | OB121 | 727
Chevron | Comble et couverture | NH II | 0.07 | 0.192 | 4.6132 | 2.5805 | 2.35 | 2.3769 | 0.062 | 0.06 | 0 | 0 |  | Charpente | Chevrons | 2084
9 x Montant | Rez de chaussée | Epicéa C24 | 0.045 | 0.22 | 2.45 | 2.178 | 1.2985 | 1.3183 | 0.0243 | 0.0243 | 0.1019 | 0.1019 | 0 | MURS RDC | OB019 | 478
6 x Montant | Premier Etage | Epicéa C24 | 0.045 | 0.22 | 0.3836 | 2.178 | 0.2033 | 0.2231 | 0.0038 | 0.0038 | 0.016 | 0.016 | 0 | MURS ETAGE | OB18 | 315
Montant | Premier Etage | Epicéa C24 | 0.045 | 0.22 | 1.4101 | 2.178 | 0.742 | 0.7618 | 0.014 | 0.0138 | 0.0586 | 0.0581 | 0 | MURS ETAGE | OB126 | 543
Montant | Premier Etage | Epicéa C24 | 0.045 | 0.1037 | 0.4736 | 0.4835 | 0.1277 | 0.1371 | 0.0022 | 0.0018 | 0.0093 | 0.0076 | 0 | MURS ETAGE | OB19 | 333
Montant | Premier Etage | Epicéa C24 | 0.045 | 0.22 | 0.176 | 2.178 | 0.0933 | 0.1131 | 0.0017 | 0.0017 | 0.0073 | 0.0073 | 0 | MURS ETAGE | OB120 | 357
Chevron | Comble et couverture | NH II | 0.092 | 0.192 | 4.6437 | 3.3915 | 2.584 | 2.6194 | 0.082 | 0.0802 | 0 | 0 |  | Charpente | Chevrons | 2094
Lisse basse | Rez de chaussée | Epicéa C24 | 0.045 | 0.145 | 6.3432 | 0.9461 | 2.4104 | 2.4235 | 0.0414 | 0.0414 | 0.1738 | 0.1738 | 0 | MURS RDC | OB021 | 246
2 x Montant | Premier Etage | Epicéa C24 | 0.045 | 0.22 | 1.16 | 2.178 | 0.6148 | 0.6346 | 0.0115 | 0.0115 | 0.0482 | 0.0482 | 0 | MURS ETAGE | OB18 | 317
Lisse basse | Rez de chaussée | Epicéa C24 | 0.045 | 0.22 | 0.9386 | 2.178 | 0.4975 | 0.5173 | 0.0093 | 0.0093 | 0.039 | 0.039 | 0 | MURS RDC | OB05 | 200
latte chantier | Rez de chaussée | Epicéa C24 | 0.04 | 0.024 | 2.7105 | 0.023 | 0.3469 | 0.3489 | 0.0026 | 0.0026 | 0.0109 | 0.0109 | 0 | MURS RDC | F3 | 813
Montant | Rez de chaussée | Epicéa C24 | 0.045 | 0.145 | 6.3432 | 0.9461 | 2.4104 | 2.4235 | 0.0414 | 0.0414 | 0.1738 | 0.1738 | 0 | MURS RDC | OB021 | 246
2 x latte 27/40 | Rez de chaussée | Epicéa C24 | 0.04 | 0.024 | 1.247 | 0.023 | 0.1596 | 0.1615 | 0.0012 | 0.0012 | 0.005 | 0.005 | 0 | MURS RDC | OB017 | 751
2 x Lisse basse traitée | Dalle | Epicéa C24 Traité | 0.045 | 0.22 | 2.2539 | 2.178 | 1.1354 | 1.1552 | 0.0223 | 0.0212 | 0 | 0 | 0 | MURS RDC | Ossature RDC | 16
latte chantier | Rez de chaussée | Epicéa C24 | 0.04 | 0.024 | 2.6 | 0.023 | 0.3328 | 0.3347 | 0.0025 | 0.0025 | 0.0105 | 0.0105 | 0 | MURS RDC | OB03 | 804
2 x latte 27/40 | Premier Etage | Epicéa C24 | 0.04 | 0.024 | 2.7105 | 0.023 | 0.3469 | 0.3489 | 0.0026 | 0.0026 | 0.0109 | 0.0109 | 0 | MURS ETAGE | OB13 | 674
Montant | Premier Etage | Epicéa C24 | 0.045 | 0.22 | 2.0078 | 2.178 | 1.0588 | 1.0786 | 0.0199 | 0.0197 | 0.0835 | 0.0829 | 0 | MURS ETAGE | OB120 | 373
Lisse basse traitée | Dalle | Epicéa C24 Traité | 0.045 | 0.145 | 2.0408 | 0.9461 | 0.7755 | 0.7885 | 0.0133 | 0.0133 | 0 | 0 | 0 | MURS RDC | Ossature RDC | 2
2 x Chevetre | Comble et couverture | NH II | 0.07 | 0.192 | 1.39 | 2.5805 | 0.7284 | 0.7552 | 0.0188 | 0.0187 | 0 | 0 |  | Chevrons | Toiture mezzanine | 2057
latte 27/40 | Premier Etage | Epicéa C24 | 0.04 | 0.024 | 0.3517 | 0.023 | 0.045 | 0.0469 | 0.0003 | 0.0003 | 0.0014 | 0.0014 | 0 | MURS ETAGE | OB127 | 639
3 x Chevron | Comble et couverture | NH II | 0.07 | 0.192 | 4.6439 | 2.5805 | 2.3831 | 2.41 | 0.0624 | 0.061 | 0 | 0 |  | Charpente | Chevrons | 2087
latte chantier | Rez de chaussée | Epicéa C24 | 0.04 | 0.024 | 1.2078 | 0.023 | 0.1546 | 0.1565 | 0.0012 | 0.0012 | 0.0049 | 0.0049 | 0 | MURS RDC | D2 | 810
Montant | Rez de chaussée | Epicéa C24 | 0.045 | 0.145 | 2.4835 | 0.9461 | 0.9437 | 0.9568 | 0.0162 | 0.0162 | 0.0681 | 0.0681 | 0 | MURS RDC | OB025 | 203
3 x latte 27/40 | Rez de chaussée | Epicéa C24 | 0.04 | 0.024 | 2.67 | 0.023 | 0.3418 | 0.3437 | 0.0026 | 0.0026 | 0.0108 | 0.0108 | 0 | MURS RDC | OB010 | 704
Lisse basse traitée | Dalle | Epicéa C24 Traité | 0.045 | 0.145 | 2.4835 | 0.9461 | 0.9437 | 0.9568 | 0.0162 | 0.0162 | 0 | 0 | 0 | MURS RDC | Ossature RDC | 3
Montant | Premier Etage | Epicéa C24 | 0.045 | 0.22 | 2.0189 | 2.178 | 1.07 | 1.0898 | 0.02 | 0.02 | 0.0839 | 0.0839 | 0 | MURS ETAGE | OB122 | 451
Lisse basse traitée | Dalle | Epicéa C24 Traité | 0.045 | 0.22 | 3.3051 | 2.178 | 1.739 | 1.7588 | 0.0327 | 0.0325 | 0 | 0 | 0 | MURS RDC | Ossature RDC | 20
latte 27/40 | Premier Etage | Epicéa C24 | 0.04 | 0.024 | 1.0344 | 0.023 | 0.1324 | 0.1343 | 0.001 | 0.001 | 0.0042 | 0.0042 | 0 | MURS COMBLE | OB14 | 626
Montant | Premier Etage | Epicéa C24 | 0.045 | 0.22 | 2.4655 | 2.178 | 1.2998 | 1.3196 | 0.0244 | 0.0242 | 0.1025 | 0.1017 | 0 | MURS ETAGE | OB127 | 181
Montant | Rez de chaussée | Epicéa C24 | 0.045 | 0.145 | 0.09 | 0.9461 | 0.0342 | 0.0472 | 0.0006 | 0.0006 | 0.0025 | 0.0025 | 0 | MURS RDC | OB026 | 487
Montant | Rez de chaussée | Epicéa C24 | 0.045 | 0.22 | 6.5091 | 2.178 | 3.4498 | 3.4696 | 0.0644 | 0.0644 | 0.2707 | 0.2707 | 0 | MURS RDC | OB020 | 154
Chevetre | Comble et couverture | NH II | 0.07 | 0.192 | 1.39 | 2.5805 | 0.7284 | 0.7552 | 0.0188 | 0.0187 | 0 | 0 |  | Chevrons | Toiture mezzanine | 2117
latte 27/40 | Premier Etage | Epicéa C24 | 0.04 | 0.024 | 2.6705 | 0.023 | 0.3418 | 0.3437 | 0.0026 | 0.0026 | 0.0108 | 0.0108 | 0 | MURS ETAGE | OB13 | 673
Chevron | Comble et couverture | NH II | 0.092 | 0.192 | 4.6437 | 3.3915 | 2.584 | 2.6194 | 0.082 | 0.0802 | 0 | 0 |  | Charpente | Chevrons | 2092
Chevron | Comble et couverture | NH II | 0.07 | 0.192 | 5.1934 | 2.5805 | 2.63 | 2.6569 | 0.0698 | 0.067 | 0 | 0 |  | Charpente | Chevrons | 2029
4 x Montant | Rez de chaussée | Epicéa C24 | 0.045 | 0.145 | 1.0452 | 0.9461 | 0.3972 | 0.4102 | 0.0068 | 0.0068 | 0.0286 | 0.0286 | 0 | MURS RDC | OB021 | 243
4 x Montant | Rez de chaussée | Epicéa C24 | 0.045 | 0.22 | 2.45 | 2.178 | 1.2985 | 1.3183 | 0.0243 | 0.0243 | 0.1019 | 0.1019 | 0 | MURS RDC | OB07 | 294
Montant | Rez de chaussée | Epicéa C24 | 0.045 | 0.145 | 3.248 | 0.9461 | 1.2342 | 1.2473 | 0.0212 | 0.0212 | 0.089 | 0.089 | 0 | MURS RDC | OB023 | 126
Montant | Premier Etage | Epicéa C24 | 0.045 | 0.22 | 0.4057 | 2.178 | 0.2081 | 0.2279 | 0.004 | 0.0038 | 0.0169 | 0.0161 | 0 | MURS ETAGE | OB14 | 90
Lisse basse traitée | Dalle | Epicéa C24 Traité | 0.045 | 0.145 | 3.204 | 0.9461 | 1.2175 | 1.2306 | 0.0209 | 0.0209 | 0 | 0 | 0 | MURS RDC | Ossature RDC | 5
Montant | Rez de chaussée | Epicéa C24 | 0.045 | 0.1822 | 2.54 | 1.4945 | 1.0917 | 1.1081 | 0.0208 | 0.0187 | 0.0875 | 0.0784 | 0 | MURS RDC | OB07 | 287
Montant | Premier Etage | Epicéa C24 | 0.045 | 0.22 | 2.984 | 2.178 | 1.5815 | 1.6013 | 0.0295 | 0.0295 | 0.1241 | 0.1241 | 0 | MURS ETAGE | OB12 | 70
Montant | Premier Etage | Epicéa C24 | 0.045 | 0.22 | 0.6667 | 2.178 | 0.3496 | 0.3694 | 0.0066 | 0.0065 | 0.0277 | 0.0274 | 0 | MURS ETAGE | OB17 | 302
Montant | Premier Etage | Epicéa C24 | 0.045 | 0.145 | 2.5501 | 0.9461 | 0.9671 | 0.9802 | 0.0166 | 0.0166 | 0.0699 | 0.0697 | 0 | MURS ETAGE | OB128 | 131
Montant | Rez de chaussée | Epicéa C24 | 0.045 | 0.145 | 2.45 | 0.9461 | 0.931 | 0.9441 | 0.016 | 0.016 | 0.0671 | 0.0671 | 0 | MURS RDC | OB024 | 536
Lisse basse traitée | Dalle | Epicéa C24 Traité | 0.045 | 0.145 | 1.7186 | 0.9461 | 0.6367 | 0.6498 | 0.0112 | 0.0109 | 0 | 0 | 0 | MURS RDC | Ossature RDC | 1
2 x latte 27/40 | Premier Etage | Epicéa C24 | 0.04 | 0.024 | 1.1292 | 0.023 | 0.1445 | 0.1465 | 0.0011 | 0.0011 | 0.0046 | 0.0046 | 0 | MURS ETAGE | OB127 | 648
Solive | Premier Etage | NH II | 0.092 | 0.22 | 1.4307 | 4.4528 | 0.8928 | 0.9333 | 0.0301 | 0.029 | 0 | 0 |  | Plancher étage | Solivage_220 | 1050
Montant | Rez de chaussée | Epicéa C24 | 0.045 | 0.22 | 0.09 | 2.178 | 0.0477 | 0.0675 | 0.0009 | 0.0009 | 0.0037 | 0.0037 | 0 | MURS RDC | OB027 | 348
Montant | Rez de chaussée | Epicéa C24 | 0.045 | 0.22 | 2.665 | 2.178 | 1.3758 | 1.3956 | 0.0264 | 0.0254 | 0.1108 | 0.1067 | 0 | MURS RDC | OB013 | 439
Panne | Comble et couverture | NH II | 0.16 | 0.24 | 6.2385 | 9.216 | 4.9577 | 5.0345 | 0.2396 | 0.2361 | 0 | 0 |  | Charpente | Toiture garage | 1523
3 x latte chantier | Rez de chaussée | Epicéa C24 | 0.04 | 0.024 | 1.0036 | 0.023 | 0.1285 | 0.1304 | 0.001 | 0.001 | 0.004 | 0.004 | 0 | MURS RDC | H2 | 816
5 x Montant | Premier Etage | Epicéa C24 | 0.045 | 0.22 | 0.3808 | 2.178 | 0.1916 | 0.2114 | 0.0038 | 0.0035 | 0.0158 | 0.0148 | 0 | MURS ETAGE | OB121 | 420
Montant | Premier Etage | Epicéa C24 | 0.045 | 0.145 | 5.091 | 0.9461 | 1.9346 | 1.9476 | 0.0332 | 0.0332 | 0.1395 | 0.1395 | 0 | MURS ETAGE | OB131 | 514
2 x latte 27/40 | Premier Etage | Epicéa C24 | 0.04 | 0.024 | 0.4686 | 0.023 | 0.06 | 0.0619 | 0.0004 | 0.0004 | 0.0019 | 0.0019 | 0 | MURS ETAGE | OB18 | 695
Lisse basse traitée | Dalle | Epicéa C24 Traité | 0.045 | 0.145 | 2.6107 | 0.9461 | 0.992 | 1.0051 | 0.017 | 0.017 | 0 | 0 | 0 | MURS RDC | Ossature RDC | 4
3 x latte 27/40 | Rez de chaussée | Epicéa C24 | 0.04 | 0.024 | 1.047 | 0.023 | 0.134 | 0.1359 | 0.001 | 0.001 | 0.0042 | 0.0042 | 0 | MURS RDC | OB02 | 601
contre poutre | Premier Etage | NH II | 0.027 | 0.165 | 0.4854 | 0.7351 | 0.1864 | 0.1953 | 0.0022 | 0.0022 | 0 | 0 |  | Plancher étage
Montant | Premier Etage | Epicéa C24 | 0.045 | 0.145 | 0.2939 | 0.9461 | 0.1117 | 0.1247 | 0.0019 | 0.0019 | 0.0081 | 0.0081 | 0 | MURS ETAGE | OB130 | 215
2 x Montant | Premier Etage | Epicéa C24 | 0.045 | 0.22 | 1.4636 | 2.178 | 0.7757 | 0.7955 | 0.0145 | 0.0145 | 0.0609 | 0.0609 | 0 | MURS ETAGE | OB16 | 281
2 x Solive | Premier Etage | NH II | 0.092 | 0.192 | 3.17 | 3.3915 | 1.8006 | 1.8359 | 0.057 | 0.056 | 0 | 0 |  | Plancher étage | Solivage_192 | 1027
Poutre Lc | Premier Etage | NH II | 0.2 | 0.28 | 2.7998 | 15.68 | 2.677 | 2.789 | 0.1568 | 0.1553 | 0 | 0 |  | Plancher étage | Poutrage_plancher_etage | 1007
2 x Solive | Premier Etage | NH II | 0.07 | 0.192 | 6.424 | 2.5805 | 3.3662 | 3.3931 | 0.0871 | 0.0863 | 0 | 0 |  | Plancher étage | Solivage_192 | 1030
Solive | Premier Etage | NH II | 0.07 | 0.192 | 6.424 | 2.5805 | 3.3662 | 3.3931 | 0.0871 | 0.0863 | 0 | 0 |  | Plancher étage | Solivage_192 | 1031
Panne | Comble et couverture | NH II | 0.16 | 0.2 | 9.715 | 6.4 | 6.9925 | 7.0565 | 0.3109 | 0.3045 | 0 | 0 |  | Charpente | Toiture habitation | 1526
Chevron | Comble et couverture | NH II | 0.07 | 0.192 | 5.662 | 2.5805 | 2.8825 | 2.9094 | 0.0761 | 0.0735 | 0 | 0 |  | Charpente | Chevrons | 2034
Montant | Rez de chaussée | Epicéa C24 | 0.045 | 0.145 | 2.54 | 0.9461 | 0.9473 | 0.9603 | 0.0166 | 0.0164 | 0.0696 | 0.0687 | 0 | MURS RDC | OB024 | 537
3 x Montant | Premier Etage | Epicéa C24 | 0.045 | 0.22 | 0.4622 | 2.178 | 0.245 | 0.2648 | 0.0046 | 0.0046 | 0.0192 | 0.0192 | 0 | MURS ETAGE | OB12 | 58
Ceinture | Premier Etage | NH II | 0.07 | 0.192 | 1.1008 | 2.5805 | 0.5634 | 0.5903 | 0.0148 | 0.0143 | 0 | 0 |  | Plancher étage | Solivage_192 | 1009
Montant | Rez de chaussée | Epicéa C24 | 0.045 | 0.22 | 0.94 | 2.178 | 0.4982 | 0.518 | 0.0093 | 0.0093 | 0.0391 | 0.0391 | 0 | MURS RDC | OB09 | 327
2 x Couvre joint | Rez de chaussée | NH II | 0.027 | 0.105 | 4.0628 | 0.2977 | 1.0076 | 1.0133 | 0.0115 | 0.01 | 0 | 0 |  | Couvre-joint
Montant | Rez de chaussée | Epicéa C24 | 0.045 | 0.22 | 1.03 | 2.178 | 0.5459 | 0.5657 | 0.0102 | 0.0102 | 0.0428 | 0.0428 | 0 | MURS RDC | OB09 | 328
Solive | Premier Etage | NH II | 0.092 | 0.22 | 0.5345 | 4.4528 | 0.3335 | 0.374 | 0.011 | 0.0108 | 0 | 0 |  | Plancher étage | Solivage_220 | 1065
2 x Montant | Rez de chaussée | Epicéa C24 | 0.045 | 0.22 | 2.39 | 2.178 | 1.2667 | 1.2865 | 0.0237 | 0.0237 | 0.0994 | 0.0994 | 0 | MURS RDC | OB010 | 346
2 x latte chantier | Rez de chaussée | Epicéa C24 | 0.04 | 0.024 | 2.74 | 0.023 | 0.3507 | 0.3526 | 0.0026 | 0.0026 | 0.011 | 0.011 | 0 | MURS RDC | OB06 | 820
Lisse basse traitée | Dalle | Epicéa C24 Traité | 0.045 | 0.22 | 4.5357 | 2.178 | 2.3391 | 2.3589 | 0.0449 | 0.0436 | 0 | 0 | 0 | MURS RDC | Ossature RDC | 23
Montant | Premier Etage | Epicéa C24 | 0.045 | 0.22 | 1.7401 | 2.178 | 0.9153 | 0.9351 | 0.0172 | 0.017 | 0.0724 | 0.0716 | 0 | MURS ETAGE | OB127 | 175
Chevron | Comble et couverture | NH II | 0.07 | 0.192 | 4.6439 | 2.5805 | 2.3831 | 2.41 | 0.0624 | 0.061 | 0 | 0 |  | Charpente | Chevrons | 2085
Chevetre | Comble et couverture | NH II | 0.07 | 0.192 | 1.39 | 2.5805 | 0.7284 | 0.7552 | 0.0188 | 0.0187 | 0 | 0 |  | Chevrons | Toiture mezzanine | 2058
Lisse basse traitée | Dalle | Epicéa C24 Traité | 0.045 | 0.22 | 2.844 | 2.178 | 1.5073 | 1.5271 | 0.0282 | 0.0282 | 0 | 0 | 0 | MURS RDC | Ossature RDC | 19
Chevron | Comble et couverture | NH II | 0.07 | 0.192 | 4.6439 | 2.5805 | 2.3831 | 2.41 | 0.0624 | 0.061 | 0 | 0 |  | Charpente | Chevrons | 2086
Montant | Premier Etage | Epicéa C24 | 0.045 | 0.22 | 1.7024 | 2.178 | 0.9023 | 0.9221 | 0.0169 | 0.0169 | 0.0708 | 0.0708 | 0 | MURS ETAGE | OB127 | 182
Chevron | Comble et couverture | NH II | 0.092 | 0.192 | 4.6438 | 3.3915 | 2.5841 | 2.6194 | 0.082 | 0.0802 | 0 | 0 |  | Charpente | Chevrons | 2095
Montant | Rez de chaussée | Epicéa C24 | 0.045 | 0.0778 | 2.54 | 0.2726 | 0.5489 | 0.5559 | 0.0089 | 0.0058 | 0.0374 | 0.0245 | 0 | MURS RDC | OB09 | 320
Montant | Rez de chaussée | Epicéa C24 | 0.045 | 0.22 | 2.54 | 2.178 | 1.2835 | 1.3033 | 0.0251 | 0.023 | 0.1056 | 0.0965 | 0 | MURS RDC | OB07 | 295
Montant | Premier Etage | Epicéa C24 | 0.0276 | 0.145 | 2.5569 | 0.5813 | 0.8818 | 0.8898 | 0.0102 | 0.0102 | 0.043 | 0.043 | 0 | MURS ETAGE | OB128 | 127
Chevron | Comble et couverture | NH II | 0.07 | 0.192 | 3.3336 | 2.5805 | 1.6797 | 1.7066 | 0.0448 | 0.0428 | 0 | 0 |  | Charpente | Chevrons | 2073
3 x Cache moineau | Comble et couverture | NH II | 0.07 | 0.192 | 0.5813 | 2.5805 | 0.3046 | 0.3315 | 0.0078 | 0.0078 | 0 | 0 |  | Chevrons | Toiture mezzanine | 2050
Montant | Premier Etage | Epicéa C24 | 0.045 | 0.22 | 0.641 | 2.178 | 0.3327 | 0.3525 | 0.0063 | 0.0062 | 0.0267 | 0.0259 | 0 | MURS ETAGE | OB14 | 93
Chevron | Comble et couverture | NH II | 0.07 | 0.192 | 5.1617 | 2.5805 | 2.6192 | 2.6461 | 0.0694 | 0.0668 | 0 | 0 |  | Charpente | Chevrons | 2028
Montant | Rez de chaussée | Epicéa C24 | 0.045 | 0.1037 | 2.54 | 0.4835 | 0.6925 | 0.7018 | 0.0118 | 0.0097 | 0.0498 | 0.0407 | 0 | MURS RDC | OB07 | 284
Lisse basse traitée | Dalle | Epicéa C24 Traité | 0.045 | 0.145 | 3.8771 | 0.9461 | 1.457 | 1.47 | 0.0253 | 0.025 | 0 | 0 | 0 | MURS RDC | Ossature RDC | 6
latte chantier | Rez de chaussée | Epicéa C24 | 0.04 | 0.024 | 2.74 | 0.023 | 0.3507 | 0.3526 | 0.0026 | 0.0026 | 0.011 | 0.011 | 0 | MURS RDC | U2 | 841
Montant | Rez de chaussée | Epicéa C24 | 0.02 | 0.22 | 1.03 | 0.968 | 0.4944 | 0.5032 | 0.0045 | 0.0045 | 0.019 | 0.019 | 0 | MURS RDC | OB09 | 326
Montant | Premier Etage | Epicéa C24 | 0.045 | 0.22 | 0.4375 | 2.178 | 0.2249 | 0.2447 | 0.0043 | 0.0041 | 0.0182 | 0.0174 | 0 | MURS COMBLE | OB127 | 187
2 x latte chantier | Rez de chaussée | Epicéa C24 | 0.04 | 0.024 | 2.645 | 0.023 | 0.3386 | 0.3405 | 0.0025 | 0.0025 | 0.0107 | 0.0107 | 0 | MURS RDC | R1 | 832
latte 27/40 | Premier Etage | Epicéa C24 | 0.04 | 0.024 | 0.2741 | 0.023 | 0.0351 | 0.037 | 0.0003 | 0.0003 | 0.0011 | 0.0011 | 0 | MURS COMBLE | OB127 | 661
Montant | Premier Etage | Epicéa C24 | 0.045 | 0.22 | 1.218 | 2.178 | 0.6385 | 0.6583 | 0.0121 | 0.0119 | 0.0506 | 0.0499 | 0 | MURS COMBLE | OB127 | 193
Montant | Rez de chaussée | Epicéa C24 | 0.045 | 0.22 | 1.8389 | 2.178 | 0.9746 | 0.9944 | 0.0182 | 0.0182 | 0.0765 | 0.0765 | 0 | MURS RDC | OB012 | 409
Montant | Premier Etage | Epicéa C24 | 0.045 | 0.22 | 0.4325 | 2.178 | 0.2255 | 0.2453 | 0.0043 | 0.0042 | 0.018 | 0.0176 | 0 | MURS ETAGE | OB17 | 300
Montant | Rez de chaussée | Epicéa C24 | 0.045 | 0.22 | 0.552 | 2.178 | 0.2926 | 0.3124 | 0.0055 | 0.0055 | 0.023 | 0.023 | 0 | MURS RDC | OB014 | 460
Lisse basse | Premier Etage | Epicéa C24 | 0.045 | 0.145 | 4.1574 | 0.9461 | 1.5798 | 1.5929 | 0.0271 | 0.0271 | 0.1139 | 0.1139 | 0 | Plancher étage | ETA | 30
Montant | Rez de chaussée | Epicéa C24 | 0.045 | 0.1037 | 2.54 | 0.4835 | 0.6925 | 0.7018 | 0.0118 | 0.0097 | 0.0498 | 0.0407 | 0 | MURS RDC | OB09 | 321
Montant | Premier Etage | Epicéa C24 | 0.045 | 0.22 | 2.1165 | 2.178 | 1.1116 | 1.1314 | 0.021 | 0.0207 | 0.088 | 0.087 | 0 | MURS ETAGE | OB121 | 426
Montant | Premier Etage | Epicéa C24 | 0.045 | 0.145 | 2.2494 | 0.9461 | 0.8508 | 0.8639 | 0.0147 | 0.0146 | 0.0616 | 0.0613 | 0 | MURS ETAGE | OB131 | 507
Enrayure | Dalle | NH II | 0.2 | 0.5 | 7.0678 | 50 | 9.8243 | 10.0243 | 0.7068 | 0.6804 | 0 | 0 |  | Maçonnerie
Montant | Rez de chaussée | Epicéa C24 | 0.045 | 0.22 | 2.385 | 2.178 | 1.2641 | 1.2838 | 0.0236 | 0.0236 | 0.0992 | 0.0992 | 0 | MURS RDC | OB07 | 293
Montant | Premier Etage | Epicéa C24 | 0.045 | 0.145 | 1.5728 | 0.9461 | 0.594 | 0.6071 | 0.0103 | 0.0102 | 0.0431 | 0.0428 | 0 | MURS ETAGE | OB130 | 224
Montant | Premier Etage | Epicéa C24 | 0.045 | 0.178 | 1.0086 | 1.4263 | 0.4325 | 0.4485 | 0.0081 | 0.0076 | 0.0339 | 0.0319 | 0 | MURS ETAGE | OB16 | 277
Montant | Premier Etage | Epicéa C24 | 0.045 | 0.145 | 5.6245 | 0.9461 | 2.1373 | 2.1504 | 0.0367 | 0.0367 | 0.1541 | 0.1541 | 0 | MURS ETAGE | OB130 | 240
Noue | Comble et couverture | NH II | 0.12 | 0.24 | 4.8689 | 6.912 | 3.3033 | 3.3609 | 0.1402 | 0.1214 | 0 | 0 |  | Chevrons | Toiture mezzanine | 1541
Chevron | Comble et couverture | NH II | 0.07 | 0.192 | 3.9541 | 2.5805 | 1.985 | 2.0118 | 0.0531 | 0.0497 | 0 | 0 |  | Charpente | Chevrons | 2076
Montant | Rez de chaussée | Epicéa C24 | 0.039 | 0.22 | 1.54 | 1.8876 | 0.7977 | 0.8149 | 0.0132 | 0.0132 | 0.0555 | 0.0555 | 0 | MURS RDC | OB04 | 81
Noue | Comble et couverture | NH II | 0.12 | 0.24 | 6.3504 | 6.912 | 4.4636 | 4.5212 | 0.1829 | 0.1576 | 0 | 0 |  | Chevrons | Toiture mezzanine | 1542
Montant | Rez de chaussée | Epicéa C24 | 0.045 | 0.22 | 0.5366 | 2.178 | 0.2844 | 0.3042 | 0.0053 | 0.0053 | 0.0223 | 0.0223 | 0 | MURS RDC | OB014 | 459
Montant | Rez de chaussée | Epicéa C24 | 0.045 | 0.1122 | 2.665 | 0.5669 | 0.8014 | 0.8115 | 0.0135 | 0.0125 | 0.0565 | 0.0524 | 0 | MURS RDC | OB013 | 428
Montant | Premier Etage | Epicéa C24 | 0.045 | 0.22 | 1.4596 | 2.178 | 0.7579 | 0.7777 | 0.0145 | 0.014 | 0.0607 | 0.0588 | 0 | MURS ETAGE | OB14 | 100
Lisse basse | Premier Etage | Epicéa C24 | 0.045 | 0.145 | 5.091 | 0.9461 | 1.9346 | 1.9476 | 0.0332 | 0.0332 | 0.1395 | 0.1395 | 0 | Plancher étage | ETA | 32
2 x Montant | Rez de chaussée | Epicéa C24 | 0.045 | 0.22 | 1.223 | 2.178 | 0.6482 | 0.668 | 0.0121 | 0.0121 | 0.0509 | 0.0509 | 0 | MURS RDC | OB019 | 476
Montant | Rez de chaussée | Epicéa C24 | 0.045 | 0.22 | 0.376 | 2.178 | 0.1993 | 0.2191 | 0.0037 | 0.0037 | 0.0156 | 0.0156 | 0 | MURS RDC | OB014 | 458
Montant | Premier Etage | Epicéa C24 | 0.045 | 0.145 | 1.4307 | 0.9461 | 0.5437 | 0.5567 | 0.0093 | 0.0093 | 0.0392 | 0.0392 | 0 | MURS ETAGE | OB130 | 237
3 x latte 27/40 | Rez de chaussée | Epicéa C24 | 0.04 | 0.024 | 0.147 | 0.023 | 0.0188 | 0.0207 | 0.0001 | 0.0001 | 0.0006 | 0.0006 | 0 | MURS RDC | OB012 | 720
Montant | Rez de chaussée | Epicéa C24 | 0.045 | 0.22 | 0.3669 | 2.178 | 0.1945 | 0.2143 | 0.0036 | 0.0036 | 0.0153 | 0.0153 | 0 | MURS RDC | OB014 | 457
Montant | Premier Etage | Epicéa C24 | 0.045 | 0.145 | 1.6542 | 0.9461 | 0.6247 | 0.6377 | 0.0108 | 0.0107 | 0.0453 | 0.045 | 0 | MURS ETAGE | OB131 | 502
2 x poteau de balcon | Premier Etage | Sapin | 0.117 | 0.07 | 1.182 | 0.5733 | 0.4295 | 0.4459 | 0.0097 | 0.0089 | 0.0484 | 0.0447 |  | Balcon Etage | Balcon | 5000
Montant | Premier Etage | Epicéa C24 | 0.045 | 0.22 | 0.9713 | 2.178 | 0.5078 | 0.5276 | 0.0096 | 0.0094 | 0.0404 | 0.0396 | 0 | MURS COMBLE | OB14 | 109
3 x Montant | Premier Etage | Epicéa C24 | 0.045 | 0.22 | 0.5021 | 2.178 | 0.2661 | 0.2859 | 0.005 | 0.005 | 0.0209 | 0.0209 | 0 | MURS ETAGE | OB14 | 91
2 x Montant | Comble et couverture | Epicéa C24 | 0.045 | 0.145 | 6.3432 | 0.9461 | 2.4104 | 2.4235 | 0.0414 | 0.0414 | 0.1738 | 0.1738 | 0 | MURS COMBLE | OB129 | 258
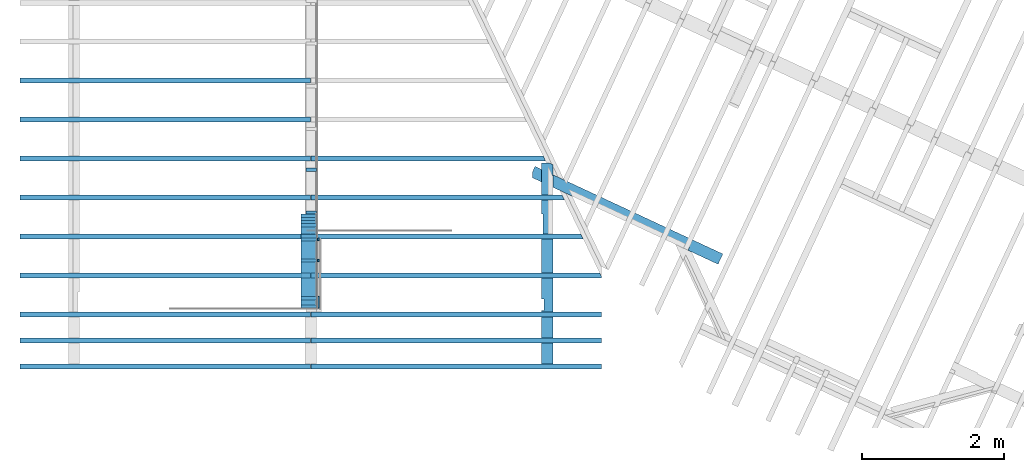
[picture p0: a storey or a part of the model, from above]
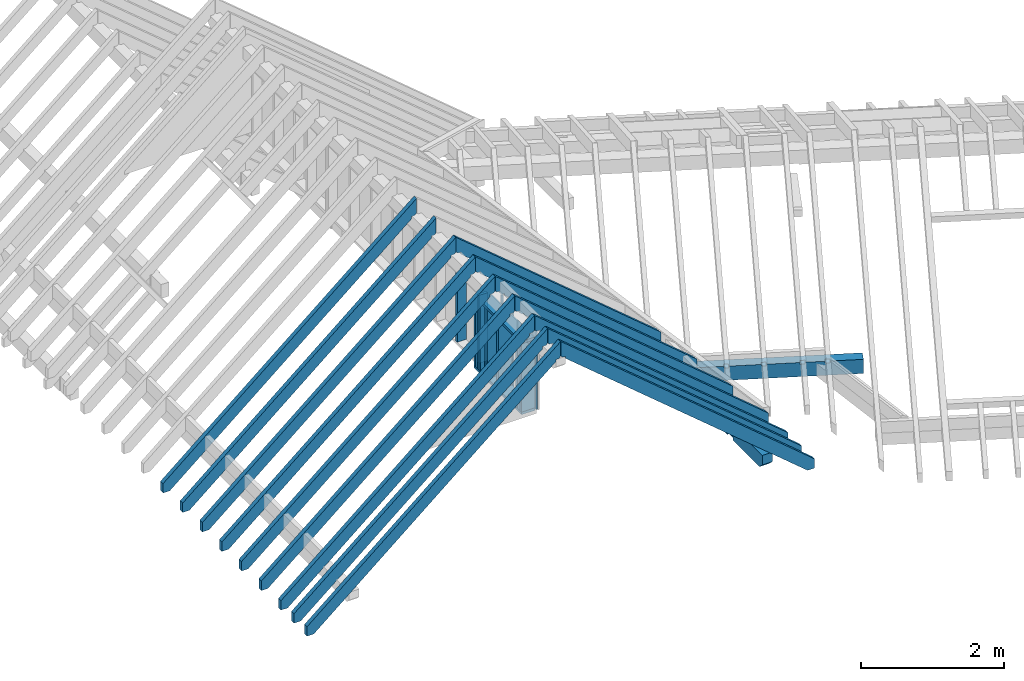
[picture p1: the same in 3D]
Properties of the parts of a building model (IFC2X3), part 3 of 4

# IfcMember (1988)
Name | In | Material | Width (m) | Height (m) | Length (m) | CrossSectionArea (m2) | OuterfaceArea (m2) | TotalSurfaceArea (m2) | GrossVolume (m3) | NetVolume (m3) | GrossWeight | NetWeight | SKU | Group | SubGroup | Prod_Nb
Montant | Premier Etage | Epicéa C24 | 0.045 | 0.22 | 1.4958 | 2.178 | 0.7928 | 0.8126 | 0.0148 | 0.0148 | 0.0622 | 0.0622 | 0 | MURS COMBLE | OB14 | 112
Chevron | Comble et couverture | NH II | 0.07 | 0.192 | 5.4355 | 2.5805 | 2.7808 | 2.8076 | 0.0731 | 0.0712 | 0 | 0 |  | Charpente | Chevrons | 2033
latte 27/40 | Premier Etage | Epicéa C24 | 0.04 | 0.024 | 1.1618 | 0.023 | 0.1487 | 0.1506 | 0.0011 | 0.0011 | 0.0047 | 0.0047 | 0 | MURS ETAGE | OB12 | 606
lisse 45x70 | Premier Etage | NH II | 0.035 | 0.07 | 3.308 | 0.1715 | 0.6922 | 0.6971 | 0.0081 | 0.0081 | 0 | 0 |  | Balcon Etage | balustrade | 5004
Montant | Rez de chaussée | Epicéa C24 | 0.045 | 0.22 | 0.5366 | 2.178 | 0.2844 | 0.3042 | 0.0053 | 0.0053 | 0.0223 | 0.0223 | 0 | MURS RDC | OB011 | 396
Montant | Premier Etage | Epicéa C24 | 0.045 | 0.22 | 1.8276 | 2.178 | 0.9686 | 0.9884 | 0.0181 | 0.0181 | 0.076 | 0.076 | 0 | MURS ETAGE | OB14 | 105
Ceinture | Premier Etage | NH II | 0.092 | 0.192 | 6.424 | 3.3915 | 3.6488 | 3.6842 | 0.1135 | 0.1135 | 0 | 0 |  | Plancher étage | Solivage_192 | 1016
2 x Chevron | Comble et couverture | NH II | 0.07 | 0.192 | 1.6699 | 2.5805 | 0.837 | 0.8639 | 0.0225 | 0.0213 | 0 | 0 |  | Charpente | Chevrons | 2013
latte chantier | Rez de chaussée | Epicéa C24 | 0.04 | 0.024 | 1.3669 | 0.023 | 0.175 | 0.1769 | 0.0013 | 0.0013 | 0.0055 | 0.0055 | 0 | MURS RDC | F5 | 814
Solive | Premier Etage | NH II | 0.07 | 0.192 | 2.05 | 2.5805 | 1.0742 | 1.1011 | 0.0277 | 0.0276 | 0 | 0 |  | Plancher étage | Solivage_192 | 1026
Montant | Premier Etage | Epicéa C24 | 0.045 | 0.22 | 1.596 | 2.178 | 0.8405 | 0.8603 | 0.0158 | 0.0157 | 0.0664 | 0.0658 | 0 | MURS ETAGE | OB120 | 367
latte 27/40 | Premier Etage | Epicéa C24 | 0.04 | 0.024 | 1.5379 | 0.023 | 0.1968 | 0.1988 | 0.0015 | 0.0015 | 0.0062 | 0.0062 | 0 | MURS COMBLE | OB14 | 627
latte 27/40 | Premier Etage | Epicéa C24 | 0.04 | 0.024 | 0.8552 | 0.023 | 0.1095 | 0.1114 | 0.0008 | 0.0008 | 0.0034 | 0.0034 | 0 | MURS ETAGE | OB127 | 645
Solive | Premier Etage | NH II | 0.092 | 0.22 | 6.0594 | 4.4528 | 3.7698 | 3.8102 | 0.1236 | 0.1222 | 0 | 0 |  | Plancher étage | Solivage_220 | 1055
2 x Montant | Rez de chaussée | Epicéa C24 | 0.045 | 0.22 | 0.552 | 2.178 | 0.2926 | 0.3124 | 0.0055 | 0.0055 | 0.023 | 0.023 | 0 | MURS RDC | OB011 | 397
Montant | Rez de chaussée | Epicéa C24 | 0.045 | 0.22 | 0.3825 | 2.178 | 0.2027 | 0.2225 | 0.0038 | 0.0038 | 0.0159 | 0.0159 | 0 | MURS RDC | OB011 | 395
Montant | Premier Etage | Epicéa C24 | 0.045 | 0.145 | 2.5236 | 0.9461 | 0.9553 | 0.9684 | 0.0165 | 0.0164 | 0.0692 | 0.0688 | 0 | MURS ETAGE | OB130 | 235
latte 27/40 | Premier Etage | Epicéa C24 | 0.04 | 0.024 | 0.7537 | 0.023 | 0.0965 | 0.0984 | 0.0007 | 0.0007 | 0.003 | 0.003 | 0 | MURS ETAGE | OB121 | 726
2 x latte chantier | Rez de chaussée | Epicéa C24 | 0.04 | 0.024 | 1.1761 | 0.023 | 0.1505 | 0.1525 | 0.0011 | 0.0011 | 0.0047 | 0.0047 | 0 | MURS RDC | T3 | 840
Montant | Rez de chaussée | Epicéa C24 | 0.045 | 0.22 | 0.552 | 2.178 | 0.2926 | 0.3124 | 0.0055 | 0.0055 | 0.023 | 0.023 | 0 | MURS RDC | OB011 | 392
latte 27/40 | Premier Etage | Epicéa C24 | 0.04 | 0.024 | 0.2632 | 0.023 | 0.0337 | 0.0356 | 0.0003 | 0.0003 | 0.0011 | 0.0011 | 0 | MURS ETAGE | OB12 | 603
Montant | Comble et couverture | Epicéa C24 | 0.07 | 0.22 | 1.16 | 3.388 | 0.6728 | 0.7036 | 0.0179 | 0.0179 | 0.075 | 0.075 | 0 | MURS COMBLE | OB13 | 256
Chevron | Comble et couverture | NH II | 0.07 | 0.192 | 1.8939 | 2.5805 | 0.9252 | 0.9521 | 0.0255 | 0.0234 | 0 | 0 |  | Charpente | Chevrons | 2068
2 x Montant | Rez de chaussée | Epicéa C24 | 0.045 | 0.22 | 1.16 | 2.178 | 0.6148 | 0.6346 | 0.0115 | 0.0115 | 0.0482 | 0.0482 | 0 | MURS RDC | OB020 | 147
2 x Montant | Rez de chaussée | Epicéa C24 | 0.045 | 0.145 | 2.21 | 0.9461 | 0.8398 | 0.8528 | 0.0144 | 0.0144 | 0.0606 | 0.0606 | 0 | MURS RDC | OB026 | 488
Montant | Rez de chaussée | Epicéa C24 | 0.039 | 0.22 | 1.07 | 1.8876 | 0.5543 | 0.5714 | 0.0092 | 0.0092 | 0.0386 | 0.0386 | 0 | MURS RDC | OB020 | 142
latte chantier | Rez de chaussée | Epicéa C24 | 0.04 | 0.024 | 1.24 | 0.023 | 0.1587 | 0.1606 | 0.0012 | 0.0012 | 0.005 | 0.005 | 0 | MURS RDC | A3 | 803
Montant | Premier Etage | Epicéa C24 | 0.045 | 0.1122 | 1.4453 | 0.5669 | 0.4343 | 0.4444 | 0.0073 | 0.0068 | 0.0307 | 0.0284 | 0 | MURS ETAGE | OB121 | 414
3 x Montant | Rez de chaussée | Epicéa C24 | 0.045 | 0.22 | 1.73 | 2.178 | 0.9169 | 0.9367 | 0.0171 | 0.0171 | 0.0719 | 0.0719 | 0 | MURS RDC | OB02 | 52
Montant | Rez de chaussée | Epicéa C24 | 0.045 | 0.1851 | 2.54 | 1.5417 | 1.0938 | 1.1104 | 0.0212 | 0.0181 | 0.0889 | 0.076 | 0 | MURS RDC | OB09 | 324
Montant | Rez de chaussée | Epicéa C24 | 0.045 | 0.22 | 0.0934 | 2.178 | 0.0495 | 0.0693 | 0.0009 | 0.0009 | 0.0039 | 0.0039 | 0 | MURS RDC | OB011 | 387
Montant | Rez de chaussée | Epicéa C24 | 0.012 | 0.22 | 2.21 | 0.5786 | 1.0252 | 1.0305 | 0.0058 | 0.0058 | 0.0244 | 0.0244 | 0 | MURS RDC | OB06 | 271
Montant | Rez de chaussée | Epicéa C24 | 0.045 | 0.22 | 0.147 | 2.178 | 0.0779 | 0.0977 | 0.0015 | 0.0015 | 0.0061 | 0.0061 | 0 | MURS RDC | OB06 | 272
Montant | Premier Etage | Epicéa C24 | 0.045 | 0.145 | 0.274 | 0.9461 | 0.1019 | 0.1149 | 0.0018 | 0.0018 | 0.0075 | 0.0074 | 0 | MURS ETAGE | OB131 | 495
Montant | Premier Etage | Epicéa C24 | 0.045 | 0.1037 | 0.4736 | 0.4835 | 0.1277 | 0.1371 | 0.0022 | 0.0018 | 0.0093 | 0.0076 | 0 | MURS ETAGE | OB17 | 296
2 x Montant | Rez de chaussée | Epicéa C24 | 0.045 | 0.145 | 2.16 | 0.9461 | 0.8208 | 0.8338 | 0.0141 | 0.0141 | 0.0592 | 0.0592 | 0 | MURS RDC | OB023 | 123
latte 27/40 | Premier Etage | Epicéa C24 | 0.04 | 0.024 | 0.5611 | 0.023 | 0.0718 | 0.0737 | 0.0005 | 0.0005 | 0.0023 | 0.0023 | 0 | MURS ETAGE | OB19 | 701
Montant | Premier Etage | Epicéa C24 | 0.045 | 0.1414 | 0.4736 | 0.8999 | 0.1635 | 0.1762 | 0.003 | 0.0026 | 0.0127 | 0.011 | 0 | MURS ETAGE | OB17 | 297
Solive | Premier Etage | NH II | 0.092 | 0.22 | 1.2957 | 4.4528 | 0.8085 | 0.849 | 0.0262 | 0.0262 | 0 | 0 |  | Plancher étage | Solivage_220 | 1049
latte 27/40 | Premier Etage | Epicéa C24 | 0.04 | 0.024 | 0.5423 | 0.023 | 0.0694 | 0.0713 | 0.0005 | 0.0005 | 0.0022 | 0.0022 | 0 | MURS ETAGE | OB127 | 642
Montant | Premier Etage | Epicéa C24 | 0.045 | 0.22 | 1.6755 | 2.178 | 0.8827 | 0.9025 | 0.0166 | 0.0165 | 0.0697 | 0.0691 | 0 | MURS ETAGE | OB120 | 368
3 x latte chantier | Rez de chaussée | Epicéa C24 | 0.04 | 0.024 | 2.67 | 0.023 | 0.3418 | 0.3437 | 0.0026 | 0.0026 | 0.0108 | 0.0108 | 0 | MURS RDC | OB04 | 815
Chevron | Comble et couverture | NH II | 0.07 | 0.192 | 5.2167 | 2.5805 | 2.6662 | 2.6931 | 0.0701 | 0.0682 | 0 | 0 |  | Charpente | Chevrons | 2090
Montant | Premier Etage | Epicéa C24 | 0.045 | 0.103 | 1.1411 | 0.4777 | 0.3182 | 0.3275 | 0.0053 | 0.0048 | 0.0222 | 0.02 | 0 | MURS ETAGE | OB123 | 479
Chevron | Comble et couverture | NH II | 0.07 | 0.192 | 0.9961 | 2.5805 | 0.4548 | 0.4817 | 0.0134 | 0.0114 | 0 | 0 |  | Charpente | Chevrons | 2061
latte chantier | Rez de chaussée | Epicéa C24 | 0.04 | 0.024 | 1.1811 | 0.023 | 0.1512 | 0.1531 | 0.0011 | 0.0011 | 0.0048 | 0.0048 | 0 | MURS RDC | D2 | 809
Cache moineau | Comble et couverture | NH II | 0.0008 | 0.2013 | 0.0756 | 0.034 | 0.0003 | 0.0007 | 0 | 0 | 0 | 0 |  | Chevrons | Toiture mezzanine | 2052
Montant | Premier Etage | Epicéa C24 | 0.045 | 0.145 | 1.9865 | 0.9461 | 0.7509 | 0.764 | 0.013 | 0.0129 | 0.0544 | 0.0541 | 0 | MURS ETAGE | OB131 | 504
Panne | Comble et couverture | NH II | 0.16 | 0.2 | 1.603 | 6.4 | 1.0198 | 1.0838 | 0.0513 | 0.0441 | 0 | 0 |  | Charpente | Toiture mezzanine | 1531
latte 27/40 | Premier Etage | Epicéa C24 | 0.04 | 0.024 | 1.0048 | 0.023 | 0.1286 | 0.1305 | 0.001 | 0.001 | 0.0041 | 0.0041 | 0 | MURS ETAGE | OB127 | 647
latte 27/40 | Premier Etage | Epicéa C24 | 0.04 | 0.024 | 0.5013 | 0.023 | 0.0642 | 0.0661 | 0.0005 | 0.0005 | 0.002 | 0.002 | 0 | MURS ETAGE | OB127 | 641
Montant | Premier Etage | Epicéa C24 | 0.045 | 0.124 | 1.1411 | 0.6921 | 0.3661 | 0.3773 | 0.0064 | 0.0058 | 0.0267 | 0.0245 | 0 | MURS ETAGE | OB123 | 480
Panne | Comble et couverture | NH II | 0.16 | 0.24 | 5.4705 | 9.216 | 4.3491 | 4.4259 | 0.2101 | 0.2054 | 0 | 0 |  | Charpente | Toiture Salon | 1539
Montant | Premier Etage | Epicéa C24 | 0.045 | 0.145 | 1.1411 | 0.9461 | 0.414 | 0.4271 | 0.0074 | 0.0069 | 0.0313 | 0.029 | 0 | MURS ETAGE | OB123 | 481
Montant | Rez de chaussée | Epicéa C24 | 0.02 | 0.22 | 1.03 | 0.968 | 0.4944 | 0.5032 | 0.0045 | 0.0045 | 0.019 | 0.019 | 0 | MURS RDC | OB07 | 289
Montant | Premier Etage | Epicéa C24 | 0.045 | 0.22 | 0.4325 | 2.178 | 0.2255 | 0.2453 | 0.0043 | 0.0042 | 0.018 | 0.0176 | 0 | MURS ETAGE | OB19 | 337
Montant | Rez de chaussée | Epicéa C24 | 0.045 | 0.1286 | 2.665 | 0.7445 | 0.8887 | 0.9003 | 0.0154 | 0.0144 | 0.0648 | 0.0607 | 0 | MURS RDC | OB012 | 403
Montant | Rez de chaussée | Epicéa C24 | 0.017 | 0.22 | 0.94 | 0.8228 | 0.4456 | 0.453 | 0.0035 | 0.0035 | 0.0148 | 0.0148 | 0 | MURS RDC | OB07 | 288
Lisse basse | Premier Etage | Epicéa C24 | 0.045 | 0.22 | 1.4915 | 2.178 | 0.7438 | 0.7636 | 0.0148 | 0.0139 | 0.062 | 0.0582 | 0 | Plancher étage | ETA | 37
latte 27/40 | Premier Etage | Epicéa C24 | 0.04 | 0.024 | 0.7522 | 0.023 | 0.0963 | 0.0982 | 0.0007 | 0.0007 | 0.003 | 0.003 | 0 | MURS ETAGE | OB19 | 702
3 x latte 27/40 | Premier Etage | Epicéa C24 | 0.04 | 0.024 | 0.4371 | 0.023 | 0.0559 | 0.0579 | 0.0004 | 0.0004 | 0.0018 | 0.0018 | 0 | MURS ETAGE | OB122 | 733
Ceinture | Premier Etage | NH II | 0.092 | 0.22 | 1.3271 | 4.4528 | 0.8167 | 0.8572 | 0.0269 | 0.0265 | 0 | 0 |  | Plancher étage | Solivage_220 | 1036
Montant | Rez de chaussée | Epicéa C24 | 0.045 | 0.22 | 2.575 | 2.178 | 1.3648 | 1.3846 | 0.0255 | 0.0255 | 0.1071 | 0.1071 | 0 | MURS RDC | OB013 | 438
Montant | Premier Etage | Epicéa C24 | 0.045 | 0.22 | 2.1165 | 2.178 | 1.1116 | 1.1314 | 0.021 | 0.0207 | 0.088 | 0.087 | 0 | MURS ETAGE | OB122 | 452
Montant | Rez de chaussée | Epicéa C24 | 0.045 | 0.22 | 0.5962 | 2.178 | 0.316 | 0.3358 | 0.0059 | 0.0059 | 0.0248 | 0.0248 | 0 | MURS RDC | OB016 | 491
Cheminée | Rez de chaussée | NH II | 0.15 | 0.15 | 4.0556 | 2.5312 | 1.8894 | 1.9231 | 0.0717 | 0.0684 | 0 | 0 |  | Maçonnerie
Montant | Premier Etage | Epicéa C24 | 0.045 | 0.22 | 1.8288 | 2.178 | 0.9693 | 0.9891 | 0.0181 | 0.0181 | 0.076 | 0.076 | 0 | MURS COMBLE | OB12 | 79
Ceinture | Premier Etage | NH II | 0.092 | 0.22 | 1.4797 | 4.4528 | 0.9031 | 0.9436 | 0.0299 | 0.029 | 0 | 0 |  | Plancher étage | Solivage_220 | 1038
2 x Montant | Rez de chaussée | Epicéa C24 | 0.045 | 0.22 | 2.67 | 2.178 | 1.4151 | 1.4349 | 0.0264 | 0.0264 | 0.111 | 0.111 | 0 | MURS RDC | OB018 | 533
latte 27/40 | Premier Etage | Epicéa C24 | 0.04 | 0.024 | 0.3301 | 0.023 | 0.0423 | 0.0442 | 0.0003 | 0.0003 | 0.0013 | 0.0013 | 0 | MURS COMBLE | OB12 | 610
Montant | Premier Etage | Epicéa C24 | 0.045 | 0.22 | 0.9204 | 2.178 | 0.4808 | 0.5006 | 0.0091 | 0.0089 | 0.0383 | 0.0375 | 0 | MURS COMBLE | OB127 | 189
2 x Montant | Premier Etage | Epicéa C24 | 0.045 | 0.22 | 2.2961 | 2.178 | 1.203 | 1.2228 | 0.0227 | 0.0224 | 0.0955 | 0.0939 | 0 | MURS ETAGE | OB12 | 68
Montant | Premier Etage | Epicéa C24 | 0.045 | 0.22 | 1.4215 | 2.178 | 0.7464 | 0.7662 | 0.0141 | 0.0139 | 0.0591 | 0.0583 | 0 | MURS COMBLE | OB127 | 194
latte 27/40 | Premier Etage | Epicéa C24 | 0.04 | 0.024 | 1.281 | 0.023 | 0.164 | 0.1659 | 0.0012 | 0.0012 | 0.0052 | 0.0052 | 0 | MURS COMBLE | OB127 | 665
Montant | Rez de chaussée | Epicéa C24 | 0.045 | 0.22 | 2.665 | 2.178 | 1.3758 | 1.3956 | 0.0264 | 0.0254 | 0.1108 | 0.1067 | 0 | MURS RDC | OB012 | 413
latte 27/40 | Premier Etage | Epicéa C24 | 0.04 | 0.024 | 1.4846 | 0.023 | 0.19 | 0.1919 | 0.0014 | 0.0014 | 0.006 | 0.006 | 0 | MURS COMBLE | OB127 | 666
Montant | Premier Etage | Epicéa C24 | 0.045 | 0.22 | 1.8674 | 2.178 | 0.9844 | 1.0042 | 0.0185 | 0.0184 | 0.0776 | 0.0771 | 0 | MURS ETAGE | OB120 | 371
Montant | Premier Etage | Epicéa C24 | 0.045 | 0.22 | 2.3618 | 2.178 | 1.2361 | 1.2559 | 0.0234 | 0.0229 | 0.0982 | 0.0963 | 0 | MURS COMBLE | OB127 | 198
Lisse basse | Rez de chaussée | Epicéa C24 | 0.045 | 0.22 | 2.0189 | 2.178 | 1.07 | 1.0898 | 0.02 | 0.02 | 0.0839 | 0.0839 | 0 | MURS RDC | OB013 | 436
Montant | Premier Etage | Epicéa C24 | 0.045 | 0.22 | 2.3616 | 2.178 | 1.236 | 1.2558 | 0.0234 | 0.0229 | 0.0982 | 0.0963 | 0 | MURS COMBLE | OB127 | 197
latte chantier | Rez de chaussée | Epicéa C24 | 0.04 | 0.024 | 0.5086 | 0.023 | 0.0651 | 0.067 | 0.0005 | 0.0005 | 0.0021 | 0.0021 | 0 | MURS RDC | J2 | 818
Lisse basse | Premier Etage | Epicéa C24 | 0.045 | 0.22 | 2.2088 | 2.178 | 1.1248 | 1.1446 | 0.0219 | 0.021 | 0.0918 | 0.0881 | 0 | Plancher étage | ETA | 40
latte 27/40 | Premier Etage | Epicéa C24 | 0.04 | 0.024 | 0.5086 | 0.023 | 0.0651 | 0.067 | 0.0005 | 0.0005 | 0.0021 | 0.0021 | 0 | MURS ETAGE | OB19 | 700
Montant | Premier Etage | Epicéa C24 | 0.045 | 0.0778 | 0.9244 | 0.2726 | 0.1982 | 0.2052 | 0.0032 | 0.0021 | 0.0136 | 0.0089 | 0 | MURS ETAGE | OB19 | 332
Montant | Premier Etage | Epicéa C24 | 0.045 | 0.22 | 0.4638 | 2.178 | 0.2458 | 0.2656 | 0.0046 | 0.0046 | 0.0193 | 0.0193 | 0 | MURS ETAGE | OB19 | 341
latte chantier | Rez de chaussée | Epicéa C24 | 0.04 | 0.024 | 0.1832 | 0.023 | 0.0235 | 0.0254 | 0.0002 | 0.0002 | 0.0007 | 0.0007 | 0 | MURS RDC | D1 | 806
Montant | Premier Etage | Epicéa C24 | 0.045 | 0.145 | 2.5393 | 0.9461 | 0.9527 | 0.9658 | 0.0166 | 0.0162 | 0.0696 | 0.0682 | 0 | MURS ETAGE | OB131 | 509
3 x Montant | Premier Etage | Epicéa C24 | 0.045 | 0.22 | 2.5593 | 2.178 | 1.3564 | 1.3762 | 0.0253 | 0.0253 | 0.1064 | 0.1064 | 0 | MURS ETAGE | OB120 | 377
Poutre Lc | Premier Etage | NH II | 0.1 | 0.2 | 2.05 | 4 | 1.23 | 1.27 | 0.0421 | 0.041 | 0 | 0 |  | Plancher étage | Poutrage_plancher_etage | 1001
Montant | Rez de chaussée | Epicéa C24 | 0.045 | 0.124 | 2.935 | 0.6921 | 0.9432 | 0.9544 | 0.0164 | 0.015 | 0.0688 | 0.063 | 0 | MURS RDC | OB010 | 385
Montant | Rez de chaussée | Epicéa C24 | 0.045 | 0.103 | 2.935 | 0.4777 | 0.8201 | 0.8293 | 0.0136 | 0.0122 | 0.0572 | 0.0513 | 0 | MURS RDC | OB010 | 384
3 x Montant | Rez de chaussée | Epicéa C24 | 0.045 | 0.145 | 0.465 | 0.9461 | 0.1767 | 0.1897 | 0.003 | 0.003 | 0.0127 | 0.0127 | 0 | MURS RDC | OB023 | 120
Montant | Rez de chaussée | Epicéa C24 | 0.045 | 0.22 | 0.5962 | 2.178 | 0.316 | 0.3358 | 0.0059 | 0.0059 | 0.0248 | 0.0248 | 0 | MURS RDC | OB018 | 532
2 x Montant | Premier Etage | Epicéa C24 | 0.045 | 0.145 | 2.166 | 0.9461 | 0.8231 | 0.8361 | 0.0141 | 0.0141 | 0.0594 | 0.0594 | 0 | MURS ETAGE | OB131 | 506
Montant | Premier Etage | Epicéa C24 | 0.045 | 0.145 | 2.67 | 0.9461 | 1.0146 | 1.0276 | 0.0174 | 0.0174 | 0.0732 | 0.0732 | 0 | MURS ETAGE | OB131 | 512
Montant | Comble et couverture | Epicéa C24 | 0.045 | 0.145 | 1.7027 | 0.9461 | 0.6353 | 0.6483 | 0.0111 | 0.0108 | 0.0467 | 0.0454 | 0 | MURS COMBLE | OB128 | 141
Chevetre | Comble et couverture | NH II | 0.07 | 0.192 | 0.476 | 2.5805 | 0.2494 | 0.2763 | 0.0065 | 0.0064 | 0 | 0 |  | Chevrons | Toiture mezzanine | 2056
Montant | Premier Etage | Epicéa C24 | 0.045 | 0.22 | 0.1685 | 2.178 | 0.0845 | 0.1043 | 0.0017 | 0.0016 | 0.007 | 0.0066 | 0 | MURS ETAGE | OB12 | 56
Lisse basse traitée | Dalle | Epicéa C24 Traité | 0.045 | 0.22 | 5.3482 | 2.178 | 2.8084 | 2.8282 | 0.0529 | 0.0524 | 0 | 0 | 0 | MURS RDC | Ossature RDC | 26
Montant | Premier Etage | Epicéa C24 | 0.045 | 0.145 | 1.8006 | 0.9461 | 0.6806 | 0.6937 | 0.0117 | 0.0117 | 0.0493 | 0.049 | 0 | MURS ETAGE | OB130 | 226
4 x latte 27/40 | Rez de chaussée | Epicéa C24 | 0.04 | 0.024 | 2.67 | 0.023 | 0.3418 | 0.3437 | 0.0026 | 0.0026 | 0.0108 | 0.0108 | 0 | MURS RDC | OB019 | 744
Montant | Premier Etage | Epicéa C24 | 0.045 | 0.22 | 0.1623 | 2.178 | 0.086 | 0.1058 | 0.0016 | 0.0016 | 0.0067 | 0.0067 | 0 | MURS ETAGE | OB127 | 158
2 x Montant | Rez de chaussée | Epicéa C24 | 0.045 | 0.22 | 0.73 | 2.178 | 0.3869 | 0.4067 | 0.0072 | 0.0072 | 0.0304 | 0.0304 | 0 | MURS RDC | OB019 | 474
Chevron | Comble et couverture | NH II | 0.07 | 0.192 | 4.471 | 2.5805 | 2.2571 | 2.284 | 0.0601 | 0.0576 | 0 | 0 |  | Charpente | Chevrons | 2025
Montant | Premier Etage | Epicéa C24 | 0.045 | 0.145 | 2.1146 | 0.9461 | 0.7999 | 0.813 | 0.0138 | 0.0137 | 0.0579 | 0.0576 | 0 | MURS ETAGE | OB130 | 228
Chevron | Comble et couverture | NH II | 0.07 | 0.192 | 4.1257 | 2.5805 | 2.0761 | 2.103 | 0.0554 | 0.0529 | 0 | 0 |  | Charpente | Chevrons | 2024
Montant | Premier Etage | Epicéa C24 | 0.045 | 0.145 | 2.1879 | 0.9461 | 0.8278 | 0.8408 | 0.0143 | 0.0142 | 0.06 | 0.0596 | 0 | MURS ETAGE | OB130 | 230
Montant | Premier Etage | Epicéa C24 | 0.045 | 0.145 | 2.4285 | 0.9461 | 0.9192 | 0.9323 | 0.0158 | 0.0158 | 0.0666 | 0.0662 | 0 | MURS ETAGE | OB130 | 231
Chevron | Comble et couverture | NH II | 0.07 | 0.192 | 3.0896 | 2.5805 | 1.5332 | 1.5601 | 0.0415 | 0.039 | 0 | 0 |  | Charpente | Chevrons | 2019
Montant | Premier Etage | Epicéa C24 | 0.045 | 0.145 | 2.7725 | 0.9461 | 1.0423 | 1.0553 | 0.0181 | 0.0178 | 0.076 | 0.0747 | 0 | MURS ETAGE | OB130 | 238
Montant | Premier Etage | Epicéa C24 | 0.045 | 0.145 | 3.0435 | 0.9461 | 1.1441 | 1.1572 | 0.0199 | 0.0195 | 0.0834 | 0.0819 | 0 | MURS ETAGE | OB130 | 239
2 x latte 27/40 | Premier Etage | Epicéa C24 | 0.04 | 0.024 | 0.5495 | 0.023 | 0.0703 | 0.0723 | 0.0005 | 0.0005 | 0.0022 | 0.0022 | 0 | MURS ETAGE | OB127 | 643
2 x Cache moineau | Comble et couverture | NH II | 0.07 | 0.192 | 0.4064 | 2.5805 | 0.213 | 0.2398 | 0.0055 | 0.0055 | 0 | 0 |  | Chevrons | Toiture mezzanine | 2041
Montant | Premier Etage | Epicéa C24 | 0.045 | 0.22 | 1.8288 | 2.178 | 0.9693 | 0.9891 | 0.0181 | 0.0181 | 0.076 | 0.076 | 0 | MURS ETAGE | OB12 | 70
2 x Montant | Rez de chaussée | Epicéa C24 | 0.045 | 0.22 | 2.67 | 2.178 | 1.4151 | 1.4349 | 0.0264 | 0.0264 | 0.111 | 0.111 | 0 | MURS RDC | OB016 | 492
Montant | Premier Etage | Epicéa C24 | 0.012 | 0.22 | 0.5021 | 0.5808 | 0.233 | 0.2382 | 0.0013 | 0.0013 | 0.0056 | 0.0056 | 0 | MURS ETAGE | OB14 | 87
Cache moineau | Comble et couverture | NH II | 0.07 | 0.192 | 0.4682 | 2.5805 | 0.2453 | 0.2722 | 0.0063 | 0.0063 | 0 | 0 |  | Chevrons | Toiture mezzanine | 2046
Montant | Rez de chaussée | Epicéa C24 | 0.045 | 0.22 | 1.3069 | 2.178 | 0.6927 | 0.7125 | 0.0129 | 0.0129 | 0.0543 | 0.0543 | 0 | MURS RDC | OB07 | 292
2 x latte 27/40 | Rez de chaussée | Epicéa C24 | 0.04 | 0.024 | 0.547 | 0.023 | 0.07 | 0.0719 | 0.0005 | 0.0005 | 0.0022 | 0.0022 | 0 | MURS RDC | OB011 | 717
Montant | Premier Etage | Epicéa C24 | 0.045 | 0.22 | 1.0919 | 2.178 | 0.5733 | 0.5931 | 0.0108 | 0.0107 | 0.0454 | 0.0449 | 0 | MURS ETAGE | OB126 | 542
Chevron | Comble et couverture | NH II | 0.07 | 0.192 | 2.0759 | 2.5805 | 1.0008 | 1.0277 | 0.0279 | 0.0245 | 0 | 0 |  | Charpente | Chevrons | 2069
2 x Chevron | Comble et couverture | NH II | 0.07 | 0.192 | 1.2157 | 2.5805 | 0.6141 | 0.641 | 0.0164 | 0.0158 | 0 | 0 |  | Charpente | Chevrons | 2062
Chevron | Comble et couverture | NH II | 0.07 | 0.192 | 0.5473 | 2.5805 | 0.2196 | 0.2465 | 0.0074 | 0.0053 | 0 | 0 |  | Charpente | Chevrons | 2059
Chevron | Comble et couverture | NH II | 0.07 | 0.1919 | 3.6502 | 2.5791 | 1.845 | 1.8719 | 0.049 | 0.0471 | 0 | 0 |  | Charpente | Chevrons | 2074
Panne | Comble et couverture | NH II | 0.16 | 0.24 | 2.8983 | 9.216 | 2.2992 | 2.376 | 0.1113 | 0.1062 | 0 | 0 |  | Charpente | Toiture habitation | 1528
Lisse basse | Premier Etage | Epicéa C24 | 0.045 | 0.22 | 3.3051 | 2.178 | 1.7401 | 1.7599 | 0.0327 | 0.0325 | 0.1374 | 0.1365 | 0 | Plancher étage | ETA | 43
Montant | Premier Etage | Epicéa C24 | 0.045 | 0.22 | 2.3976 | 2.178 | 1.2707 | 1.2905 | 0.0237 | 0.0237 | 0.0997 | 0.0997 | 0 | MURS ETAGE | OB18 | 318
Montant | Premier Etage | Epicéa C24 | 0.0291 | 0.22 | 0.3186 | 1.4075 | 0.1587 | 0.1715 | 0.002 | 0.002 | 0.0086 | 0.0086 | 0 | MURS COMBLE | OB14 | 106
Montant | Premier Etage | Epicéa C24 | 0.045 | 0.22 | 0.27 | 2.178 | 0.1387 | 0.1585 | 0.0027 | 0.0026 | 0.0112 | 0.0108 | 0 | MURS ETAGE | OB121 | 418
Cache moineau | Comble et couverture | NH II | 0.07 | 0.22 | 0.6244 | 3.388 | 0.2854 | 0.3162 | 0.0096 | 0.0072 | 0 | 0 |  | Chevrons | Toiture mezzanine | 2051
2 x latte chantier | Rez de chaussée | Epicéa C24 | 0.04 | 0.024 | 2.67 | 0.023 | 0.3418 | 0.3437 | 0.0026 | 0.0026 | 0.0108 | 0.0108 | 0 | MURS RDC | OB05 | 817
Montant | Rez de chaussée | Epicéa C24 | 0.045 | 0.22 | 4.2015 | 2.178 | 2.2268 | 2.2466 | 0.0416 | 0.0416 | 0.1747 | 0.1747 | 0 | MURS RDC | OB011 | 401
Montant | Premier Etage | Epicéa C24 | 0.045 | 0.145 | 2.079 | 0.9461 | 0.7861 | 0.7992 | 0.0136 | 0.0135 | 0.057 | 0.0566 | 0 | MURS ETAGE | OB131 | 505
latte 27/40 | Premier Etage | Epicéa C24 | 0.04 | 0.024 | 0.9433 | 0.023 | 0.1207 | 0.1227 | 0.0009 | 0.0009 | 0.0038 | 0.0038 | 0 | MURS ETAGE | OB19 | 703
latte 27/40 | Premier Etage | Epicéa C24 | 0.04 | 0.024 | 0.6161 | 0.023 | 0.0789 | 0.0808 | 0.0006 | 0.0006 | 0.0025 | 0.0025 | 0 | MURS ETAGE | OB127 | 644
latte 27/40 | Premier Etage | Epicéa C24 | 0.04 | 0.024 | 1.2043 | 0.023 | 0.1541 | 0.1561 | 0.0012 | 0.0012 | 0.0049 | 0.0049 | 0 | MURS ETAGE | OB124 | 748
2 x Chevron | Comble et couverture | NH II | 0.07 | 0.192 | 1.8555 | 2.5805 | 0.9463 | 0.9731 | 0.025 | 0.0243 | 0 | 0 |  | Charpente | Chevrons | 2014
latte 27/40 | Premier Etage | Epicéa C24 | 0.04 | 0.024 | 1.5211 | 0.023 | 0.1947 | 0.1966 | 0.0015 | 0.0015 | 0.0061 | 0.0061 | 0 | MURS ETAGE | OB124 | 749
Ceinture | Premier Etage | NH II | 0.092 | 0.22 | 1.5687 | 4.4528 | 0.9166 | 0.9571 | 0.0318 | 0.029 | 0 | 0 |  | Plancher étage | Solivage_220 | 1039
2 x Montant | Premier Etage | Epicéa C24 | 0.045 | 0.22 | 1.16 | 2.178 | 0.6148 | 0.6346 | 0.0115 | 0.0115 | 0.0482 | 0.0482 | 0 | MURS COMBLE | OB127 | 192
Montant | Premier Etage | Epicéa C24 | 0.045 | 0.22 | 1.761 | 2.178 | 0.9333 | 0.9531 | 0.0174 | 0.0174 | 0.0732 | 0.0732 | 0 | MURS ETAGE | OB14 | 104
Poutre Lc | Premier Etage | NH II | 0.2 | 0.24 | 3.284 | 11.52 | 2.8723 | 2.9683 | 0.1576 | 0.1559 | 0 | 0 |  | Plancher étage | Poutrage_plancher_etage | 1005
Montant | Premier Etage | Epicéa C24 | 0.045 | 0.22 | 1.0919 | 2.178 | 0.5733 | 0.5931 | 0.0108 | 0.0107 | 0.0454 | 0.0449 | 0 | MURS ETAGE | OB124 | 519
2 x latte 27/40 | Rez de chaussée | Epicéa C24 | 0.04 | 0.024 | 0.485 | 0.023 | 0.0621 | 0.064 | 0.0005 | 0.0005 | 0.002 | 0.002 | 0 | MURS RDC | OB017 | 750
Chevron | Comble et couverture | NH II | 0.07 | 0.192 | 1.4297 | 2.5805 | 0.6736 | 0.7005 | 0.0192 | 0.0167 | 0 | 0 |  | Charpente | Chevrons | 2105
Cache moineau | Comble et couverture | NH II | 0.0008 | 0.1866 | 0.0703 | 0.0292 | 0.0003 | 0.0006 | 0 | 0 | 0 | 0 |  | Chevrons | Toiture mezzanine | 2052
Lisse basse | Rez de chaussée | Epicéa C24 | 0.045 | 0.22 | 0.5962 | 2.178 | 0.316 | 0.3358 | 0.0059 | 0.0059 | 0.0248 | 0.0248 | 0 | MURS RDC | OB018 | 532
Poutre Lc | Premier Etage | NH II | 0.1 | 0.2 | 1.1706 | 4 | 0.657 | 0.697 | 0.0238 | 0.0212 | 0 | 0 |  | Plancher étage | Poutrage_plancher_etage | 1000
Montant | Premier Etage | Epicéa C24 | 0.045 | 0.22 | 2.2189 | 2.178 | 1.1658 | 1.1856 | 0.022 | 0.0217 | 0.0923 | 0.0912 | 0 | MURS ETAGE | OB121 | 427
3 x latte 27/40 | Rez de chaussée | Epicéa C24 | 0.04 | 0.024 | 0.147 | 0.023 | 0.0188 | 0.0207 | 0.0001 | 0.0001 | 0.0006 | 0.0006 | 0 | MURS RDC | OB013 | 729
Montant | Rez de chaussée | Epicéa C24 | 0.045 | 0.22 | 3.284 | 2.178 | 1.7405 | 1.7603 | 0.0325 | 0.0325 | 0.1365 | 0.1365 | 0 | MURS RDC | OB017 | 526
Lisse basse | Rez de chaussée | Epicéa C24 | 0.045 | 0.22 | 3.284 | 2.178 | 1.7405 | 1.7603 | 0.0325 | 0.0325 | 0.1365 | 0.1365 | 0 | MURS RDC | OB017 | 526
Montant | Premier Etage | Epicéa C24 | 0.045 | 0.1286 | 1.4453 | 0.7445 | 0.4816 | 0.4932 | 0.0084 | 0.0078 | 0.0351 | 0.0329 | 0 | MURS ETAGE | OB121 | 415
latte chantier | Rez de chaussée | Epicéa C24 | 0.04 | 0.024 | 2.74 | 0.023 | 0.3507 | 0.3526 | 0.0026 | 0.0026 | 0.011 | 0.011 | 0 | MURS RDC | W1 | 843
Montant | Premier Etage | Epicéa C24 | 0.045 | 0.22 | 1.7806 | 2.178 | 0.9383 | 0.9581 | 0.0176 | 0.0175 | 0.074 | 0.0735 | 0 | MURS ETAGE | OB120 | 369
latte 27/40 | Premier Etage | Epicéa C24 | 0.04 | 0.024 | 1.9145 | 0.023 | 0.2451 | 0.247 | 0.0018 | 0.0018 | 0.0077 | 0.0077 | 0 | MURS ETAGE | OB127 | 658
Montant | Premier Etage | Epicéa C24 | 0.045 | 0.145 | 1.7468 | 0.9461 | 0.6598 | 0.6729 | 0.0114 | 0.0113 | 0.0479 | 0.0475 | 0 | MURS ETAGE | OB131 | 503
Montant | Premier Etage | Epicéa C24 | 0.045 | 0.145 | 2.5958 | 0.9461 | 0.9825 | 0.9955 | 0.0169 | 0.0169 | 0.0711 | 0.0708 | 0 | MURS ETAGE | OB131 | 511
Ceinture | Premier Etage | NH II | 0.092 | 0.22 | 1.3658 | 4.4528 | 0.7877 | 0.8282 | 0.0276 | 0.0247 | 0 | 0 |  | Plancher étage | Solivage_220 | 1037
Montant | Premier Etage | Epicéa C24 | 0.045 | 0.145 | 2.7244 | 0.9461 | 1.023 | 1.0361 | 0.0178 | 0.0174 | 0.0747 | 0.0732 | 0 | MURS ETAGE | OB131 | 513
latte 27/40 | Premier Etage | Epicéa C24 | 0.04 | 0.024 | 1.8103 | 0.023 | 0.2317 | 0.2336 | 0.0017 | 0.0017 | 0.0073 | 0.0073 | 0 | MURS ETAGE | OB14 | 622
Cache moineau | Comble et couverture | NH II | 0.07 | 0.192 | 0.3948 | 2.5805 | 0.2069 | 0.2338 | 0.0053 | 0.0053 | 0 | 0 |  | Chevrons | Toiture mezzanine | 2040
2 x Cache moineau | Comble et couverture | NH II | 0.07 | 0.192 | 0.476 | 2.5805 | 0.2494 | 0.2763 | 0.0064 | 0.0064 | 0 | 0 |  | Chevrons | Toiture mezzanine | 2045
2 x Montant | Premier Etage | Epicéa C24 | 0.045 | 0.145 | 2.166 | 0.9461 | 0.8231 | 0.8361 | 0.0141 | 0.0141 | 0.0594 | 0.0594 | 0 | MURS ETAGE | OB130 | 229
Cache moineau | Comble et couverture | NH II | 0.07 | 0.192 | 0.503 | 2.5805 | 0.2636 | 0.2905 | 0.0068 | 0.0068 | 0 | 0 |  | Chevrons | Toiture mezzanine | 2114
2 x latte chantier | Rez de chaussée | Epicéa C24 | 0.04 | 0.024 | 2.97 | 0.023 | 0.3802 | 0.3821 | 0.0029 | 0.0029 | 0.012 | 0.012 | 0 | MURS RDC | S1 | 836
Montant | Premier Etage | Epicéa C24 | 0.045 | 0.22 | 1.0961 | 2.178 | 0.5809 | 0.6007 | 0.0109 | 0.0109 | 0.0456 | 0.0456 | 0 | MURS ETAGE | OB123 | 484
Montant | Premier Etage | Epicéa C24 | 0.045 | 0.22 | 1.8089 | 2.178 | 0.9587 | 0.9785 | 0.0179 | 0.0179 | 0.0752 | 0.0752 | 0 | MURS ETAGE | OB16 | 282
Montant | Premier Etage | Epicéa C24 | 0.045 | 0.22 | 1.8539 | 2.178 | 0.9825 | 1.0023 | 0.0184 | 0.0184 | 0.0771 | 0.0771 | 0 | MURS ETAGE | OB16 | 283
Montant | Premier Etage | Epicéa C24 | 0.045 | 0.145 | 1.4263 | 0.9461 | 0.5381 | 0.5511 | 0.0093 | 0.0092 | 0.0391 | 0.0387 | 0 | MURS ETAGE | OB131 | 501
contre poutre | Premier Etage | NH II | 0.027 | 0.165 | 0.9178 | 0.7351 | 0.3524 | 0.3614 | 0.0041 | 0.0041 | 0 | 0 |  | Plancher étage
Montant | Premier Etage | Epicéa C24 | 0.045 | 0.145 | 1.3338 | 0.9461 | 0.5029 | 0.516 | 0.0087 | 0.0086 | 0.0366 | 0.0362 | 0 | MURS ETAGE | OB131 | 500
2 x Cache moineau | Comble et couverture | NH II | 0.07 | 0.192 | 0.455 | 2.5805 | 0.2384 | 0.2653 | 0.0061 | 0.0061 | 0 | 0 |  | Chevrons | Toiture mezzanine | 2047
Montant | Premier Etage | Epicéa C24 | 0.045 | 0.22 | 1.3069 | 2.178 | 0.6927 | 0.7125 | 0.0129 | 0.0129 | 0.0543 | 0.0543 | 0 | MURS ETAGE | OB17 | 306
latte 27/40 | Premier Etage | Epicéa C24 | 0.04 | 0.024 | 0.7785 | 0.023 | 0.0997 | 0.1016 | 0.0007 | 0.0007 | 0.0031 | 0.0031 | 0 | MURS ETAGE | OB17 | 690
Montant | Premier Etage | Epicéa C24 | 0.045 | 0.22 | 0.9154 | 2.178 | 0.4852 | 0.505 | 0.0091 | 0.0091 | 0.0381 | 0.0381 | 0 | MURS ETAGE | OB17 | 305
latte 27/40 | Premier Etage | Epicéa C24 | 0.04 | 0.024 | 0.996 | 0.023 | 0.1275 | 0.1294 | 0.001 | 0.001 | 0.004 | 0.004 | 0 | MURS ETAGE | OB17 | 691
Lisse basse | Premier Etage | Epicéa C24 | 0.045 | 0.22 | 2.4876 | 2.178 | 1.2773 | 1.2971 | 0.0246 | 0.0238 | 0.1034 | 0.1001 | 0 | Plancher étage | ETA | 41
Solive | Premier Etage | NH II | 0.092 | 0.22 | 4.2964 | 4.4528 | 2.635 | 2.6755 | 0.087 | 0.0847 | 0 | 0 |  | Plancher étage | Solivage_220 | 1052
Montant | Premier Etage | Epicéa C24 | 0.045 | 0.22 | 0.4286 | 2.178 | 0.2272 | 0.247 | 0.0042 | 0.0042 | 0.0178 | 0.0178 | 0 | MURS ETAGE | OB17 | 305
Montant | Premier Etage | Epicéa C24 | 0.045 | 0.22 | 1.1633 | 2.178 | 0.609 | 0.6288 | 0.0115 | 0.0114 | 0.0484 | 0.0477 | 0 | MURS ETAGE | OB19 | 342
latte 27/40 | Premier Etage | Epicéa C24 | 0.04 | 0.024 | 0.5086 | 0.023 | 0.0651 | 0.067 | 0.0005 | 0.0005 | 0.0021 | 0.0021 | 0 | MURS ETAGE | OB17 | 688
Lisse basse | Premier Etage | Epicéa C24 | 0.045 | 0.22 | 0.8875 | 2.178 | 0.4442 | 0.464 | 0.0088 | 0.0083 | 0.0369 | 0.0348 | 0 | Plancher étage | ETA | 36
latte 27/40 | Premier Etage | Epicéa C24 | 0.04 | 0.024 | 1.8755 | 0.023 | 0.2401 | 0.242 | 0.0018 | 0.0018 | 0.0076 | 0.0076 | 0 | MURS ETAGE | OB127 | 656
Lisse basse traitée | Dalle | Epicéa C24 Traité | 0.045 | 0.22 | 2.4876 | 2.178 | 1.2773 | 1.2971 | 0.0246 | 0.0238 | 0 | 0 | 0 | MURS RDC | Ossature RDC | 17
Montant | Rez de chaussée | Epicéa C24 | 0.045 | 0.22 | 2.4876 | 2.178 | 1.3184 | 1.3382 | 0.0246 | 0.0246 | 0.1034 | 0.1034 | 0 | MURS RDC | OB08 | 313
Arbalétrier | Premier Etage | NH II | 0.16 | 0.2 | 4.0292 | 6.4 | 2.7998 | 2.8638 | 0.1303 | 0.1236 | 0 | 0 |  | Charpente | F01 | 1502
Montant | Premier Etage | Epicéa C24 | 0.045 | 0.22 | 0.4492 | 2.178 | 0.2343 | 0.2541 | 0.0044 | 0.0044 | 0.0187 | 0.0183 | 0 | MURS ETAGE | OB19 | 338
Montant | Premier Etage | Epicéa C24 | 0.045 | 0.22 | 2.2211 | 2.178 | 1.1718 | 1.1916 | 0.022 | 0.0219 | 0.0924 | 0.0918 | 0 | MURS ETAGE | OB120 | 374
Montant | Premier Etage | Epicéa C24 | 0.045 | 0.22 | 1.165 | 2.178 | 0.6174 | 0.6372 | 0.0115 | 0.0115 | 0.0484 | 0.0484 | 0 | MURS ETAGE | OB19 | 343
Solive | Premier Etage | NH II | 0.092 | 0.22 | 0.39 | 4.4528 | 0.2434 | 0.2838 | 0.0081 | 0.0079 | 0 | 0 |  | Plancher étage | Solivage_220 | 1047
latte 27/40 | Premier Etage | Epicéa C24 | 0.04 | 0.024 | 1.7879 | 0.023 | 0.2289 | 0.2308 | 0.0017 | 0.0017 | 0.0072 | 0.0072 | 0 | MURS ETAGE | OB120 | 715
2 x Montant | Premier Etage | Epicéa C24 | 0.045 | 0.22 | 1.0086 | 2.178 | 0.5346 | 0.5544 | 0.01 | 0.01 | 0.0419 | 0.0419 | 0 | MURS ETAGE | OB120 | 364
Lisse basse | Rez de chaussée | Epicéa C24 | 0.045 | 0.22 | 2.4876 | 2.178 | 1.3184 | 1.3382 | 0.0246 | 0.0246 | 0.1034 | 0.1034 | 0 | MURS RDC | OB08 | 313
Montant | Premier Etage | Epicéa C24 | 0.045 | 0.22 | 0.5532 | 2.178 | 0.2862 | 0.306 | 0.0055 | 0.0053 | 0.023 | 0.0222 | 0 | MURS ETAGE | OB14 | 92
Montant | Premier Etage | Epicéa C24 | 0.045 | 0.22 | 0.8627 | 2.178 | 0.4572 | 0.477 | 0.0085 | 0.0085 | 0.0359 | 0.0359 | 0 | MURS ETAGE | OB19 | 341
Ceinture | Premier Etage | NH II | 0.092 | 0.192 | 0.7186 | 3.3915 | 0.4082 | 0.4435 | 0.0127 | 0.0127 | 0 | 0 |  | Plancher étage | Solivage_192 | 1012
Montant | Premier Etage | Epicéa C24 | 0.045 | 0.22 | 1.73 | 2.178 | 0.9169 | 0.9367 | 0.0171 | 0.0171 | 0.0719 | 0.0719 | 0 | MURS ETAGE | OB12 | 64
Lisse basse | Rez de chaussée | Epicéa C24 | 0.045 | 0.22 | 4.2015 | 2.178 | 2.2268 | 2.2466 | 0.0416 | 0.0416 | 0.1747 | 0.1747 | 0 | MURS RDC | OB011 | 401
Chevron | Comble et couverture | NH II | 0.07 | 0.165 | 4.2825 | 1.9057 | 1.9637 | 1.9868 | 0.0495 | 0.0481 | 0 | 0 |  | Charpente | Chevrons | 2001
Ceinture | Premier Etage | NH II | 0.092 | 0.192 | 3.208 | 3.3915 | 1.8133 | 1.8486 | 0.0567 | 0.055 | 0 | 0 |  | Plancher étage | Solivage_192 | 1015
Cache moineau | Comble et couverture | NH II | 0.07 | 0.192 | 0.455 | 2.5805 | 0.2384 | 0.2653 | 0.0061 | 0.0061 | 0 | 0 |  | Chevrons | Toiture mezzanine | 2044
Montant | Rez de chaussée | Epicéa C24 | 0.045 | 0.199 | 2.54 | 1.7823 | 1.1972 | 1.2151 | 0.0227 | 0.0215 | 0.0955 | 0.0905 | 0 | MURS RDC | OB06 | 270
Montant | Rez de chaussée | Epicéa C24 | 0.045 | 0.22 | 2.0189 | 2.178 | 1.07 | 1.0898 | 0.02 | 0.02 | 0.0839 | 0.0839 | 0 | MURS RDC | OB012 | 410
2 x Cache moineau | Comble et couverture | NH II | 0.07 | 0.192 | 0.3557 | 2.5805 | 0.1864 | 0.2133 | 0.0048 | 0.0048 | 0 | 0 |  | Chevrons | Toiture mezzanine | 2048
Solive | Premier Etage | NH II | 0.092 | 0.22 | 0.8319 | 4.4528 | 0.5191 | 0.5596 | 0.017 | 0.0168 | 0 | 0 |  | Plancher étage | Solivage_220 | 1066
4 x Montant | Rez de chaussée | Epicéa C24 | 0.045 | 0.22 | 2.845 | 2.178 | 1.5078 | 1.5276 | 0.0282 | 0.0282 | 0.1183 | 0.1183 | 0 | MURS RDC | OB014 | 462
Ceinture | Premier Etage | NH II | 0.07 | 0.192 | 3.24 | 2.5805 | 1.6843 | 1.7112 | 0.0435 | 0.0431 | 0 | 0 |  | Plancher étage | Solivage_192 | 1010
lisse 45x70 | Premier Etage | NH II | 0.035 | 0.07 | 1.1488 | 0.1715 | 0.2388 | 0.2437 | 0.0028 | 0.0028 | 0 | 0 |  | Balcon Etage | balustrade | 5003
Solive | Premier Etage | NH II | 0.092 | 0.22 | 2.8026 | 4.4528 | 1.7375 | 1.778 | 0.0577 | 0.0563 | 0 | 0 |  | Plancher étage | Solivage_220 | 1068
Ceinture | Premier Etage | NH II | 0.092 | 0.192 | 1.0638 | 3.3915 | 0.5866 | 0.6219 | 0.0188 | 0.018 | 0 | 0 |  | Plancher étage | Solivage_192 | 1013
Montant | Rez de chaussée | Epicéa C24 | 0.045 | 0.145 | 2.665 | 0.9461 | 0.976 | 0.9891 | 0.0174 | 0.0164 | 0.073 | 0.0689 | 0 | MURS RDC | OB012 | 405
Montant | Rez de chaussée | Epicéa C24 | 0.045 | 0.22 | 2.0189 | 2.178 | 1.07 | 1.0898 | 0.02 | 0.02 | 0.0839 | 0.0839 | 0 | MURS RDC | OB013 | 436
Panne | Comble et couverture | NH II | 0.16 | 0.2 | 3.5717 | 6.4 | 2.5495 | 2.6135 | 0.1143 | 0.1131 | 0 | 0 |  | Charpente | Toiture mezzanine | 1533
Cache moineau | Comble et couverture | NH II | 0.07 | 0.192 | 0.1201 | 2.5805 | 0.0581 | 0.085 | 0.0016 | 0.0015 | 0 | 0 |  | Chevrons | Toiture mezzanine | 2037
Montant | Rez de chaussée | Epicéa C24 | 0.045 | 0.2036 | 2.665 | 1.8658 | 1.2885 | 1.3068 | 0.0244 | 0.0234 | 0.1026 | 0.0984 | 0 | MURS RDC | OB013 | 432
latte 27/40 | Premier Etage | Epicéa C24 | 0.04 | 0.024 | 1.7618 | 0.023 | 0.2255 | 0.2274 | 0.0017 | 0.0017 | 0.0071 | 0.0071 | 0 | MURS ETAGE | OB127 | 654
Montant | Rez de chaussée | Epicéa C24 | 0.045 | 0.145 | 1.07 | 0.9461 | 0.4066 | 0.4196 | 0.007 | 0.007 | 0.0293 | 0.0293 | 0 | MURS RDC | OB022 | 116
Lisse basse | Rez de chaussée | Epicéa C24 | 0.045 | 0.22 | 2.2142 | 2.178 | 1.1735 | 1.1933 | 0.0219 | 0.0219 | 0.0921 | 0.0921 | 0 | MURS RDC | OB014 | 461
latte 27/40 | Premier Etage | Epicéa C24 | 0.04 | 0.024 | 2.2789 | 0.023 | 0.2917 | 0.2936 | 0.0022 | 0.0022 | 0.0092 | 0.0092 | 0 | MURS ETAGE | OB14 | 623
Lisse basse traitée | Dalle | Epicéa C24 Traité | 0.045 | 0.22 | 5.2582 | 2.178 | 2.7869 | 2.8067 | 0.0521 | 0.0521 | 0 | 0 | 0 | MURS RDC | Ossature RDC | 25
Lisse basse traitée | Dalle | Epicéa C24 Traité | 0.045 | 0.22 | 2.593 | 2.178 | 1.323 | 1.3428 | 0.0257 | 0.0247 | 0 | 0 | 0 | MURS RDC | Ossature RDC | 18
Lisse basse | Premier Etage | Epicéa C24 | 0.045 | 0.22 | 4.3791 | 2.178 | 2.3072 | 2.327 | 0.0434 | 0.0431 | 0.1821 | 0.181 | 0 | Plancher étage | ETA | 46
latte 27/40 | Premier Etage | Epicéa C24 | 0.04 | 0.024 | 1.1678 | 0.023 | 0.1495 | 0.1514 | 0.0011 | 0.0011 | 0.0047 | 0.0047 | 0 | MURS ETAGE | OB15 | 670
Montant | Rez de chaussée | Epicéa C24 | 0.045 | 0.145 | 0.6421 | 0.9461 | 0.244 | 0.2571 | 0.0042 | 0.0042 | 0.0176 | 0.0176 | 0 | MURS RDC | OB023 | 121
Panne | Comble et couverture | NH II | 0.16 | 0.2 | 3.5332 | 6.4 | 2.4936 | 2.5576 | 0.1131 | 0.1099 | 0 | 0 |  | Charpente | Toiture Salon | 1537
Chevron | Comble et couverture | NH II | 0.07 | 0.192 | 2.233 | 2.5805 | 1.0882 | 1.115 | 0.03 | 0.027 | 0 | 0 |  | Charpente | Chevrons | 2107
2 x latte chantier | Rez de chaussée | Epicéa C24 | 0.04 | 0.024 | 1.1361 | 0.023 | 0.1454 | 0.1473 | 0.0011 | 0.0011 | 0.0046 | 0.0046 | 0 | MURS RDC | T3 | 839
Montant | Rez de chaussée | Epicéa C24 | 0.045 | 0.22 | 1.03 | 2.178 | 0.5459 | 0.5657 | 0.0102 | 0.0102 | 0.0428 | 0.0428 | 0 | MURS RDC | OB07 | 291
Montant | Premier Etage | Epicéa C24 | 0.045 | 0.22 | 2.084 | 2.178 | 1.0976 | 1.1174 | 0.0206 | 0.0204 | 0.0867 | 0.0859 | 0 | MURS ETAGE | OB127 | 178
latte 27/40 | Premier Etage | Epicéa C24 | 0.04 | 0.024 | 1.1811 | 0.023 | 0.1512 | 0.1531 | 0.0011 | 0.0011 | 0.0048 | 0.0048 | 0 | MURS ETAGE | OB127 | 649
Montant | Premier Etage | Epicéa C24 | 0.041 | 0.22 | 2.5593 | 1.9844 | 1.336 | 1.354 | 0.0231 | 0.0231 | 0.097 | 0.097 | 0 | MURS ETAGE | OB120 | 354
latte chantier | Rez de chaussée | Epicéa C24 | 0.04 | 0.024 | 0.265 | 0.023 | 0.0339 | 0.0358 | 0.0003 | 0.0003 | 0.0011 | 0.0011 | 0 | MURS RDC | P2 | 830
Montant | Premier Etage | Epicéa C24 | 0.045 | 0.145 | 1.4453 | 0.9461 | 0.529 | 0.542 | 0.0094 | 0.0089 | 0.0396 | 0.0374 | 0 | MURS ETAGE | OB121 | 416
Ceinture | Premier Etage | NH II | 0.092 | 0.192 | 6.516 | 3.3915 | 3.6834 | 3.7188 | 0.1151 | 0.1143 | 0 | 0 |  | Plancher étage | Solivage_192 | 1017
Montant | Rez de chaussée | Epicéa C24 | 0.045 | 0.22 | 1.73 | 2.178 | 0.9169 | 0.9367 | 0.0171 | 0.0171 | 0.0719 | 0.0719 | 0 | MURS RDC | OB08 | 311
Ceinture | Premier Etage | NH II | 0.092 | 0.22 | 1.2867 | 4.4528 | 0.7916 | 0.8321 | 0.026 | 0.0256 | 0 | 0 |  | Plancher étage | Solivage_220 | 1035
Montant | Premier Etage | Epicéa C24 | 0.045 | 0.145 | 1.4453 | 0.9461 | 0.529 | 0.542 | 0.0094 | 0.0089 | 0.0396 | 0.0374 | 0 | MURS ETAGE | OB122 | 442
latte chantier | Rez de chaussée | Epicéa C24 | 0.04 | 0.024 | 1.4403 | 0.023 | 0.1844 | 0.1863 | 0.0014 | 0.0014 | 0.0058 | 0.0058 | 0 | MURS RDC | R2 | 834
Lisse basse | Rez de chaussée | Epicéa C24 | 0.045 | 0.22 | 1.3901 | 2.178 | 0.7368 | 0.7566 | 0.0138 | 0.0138 | 0.0578 | 0.0578 | 0 | MURS RDC | OB019 | 477
Lisse basse traitée | Dalle | Epicéa C24 Traité | 0.045 | 0.22 | 1.3151 | 2.178 | 0.6843 | 0.7041 | 0.013 | 0.0128 | 0 | 0 | 0 | MURS RDC | Ossature RDC | 11
Ceinture | Premier Etage | NH II | 0.092 | 0.192 | 3.204 | 3.3915 | 1.8022 | 1.8375 | 0.0566 | 0.0558 | 0 | 0 |  | Plancher étage | Solivage_192 | 1014
Lisse basse traitée | Dalle | Epicéa C24 Traité | 0.045 | 0.22 | 2.2088 | 2.178 | 1.1248 | 1.1446 | 0.0219 | 0.021 | 0 | 0 | 0 | MURS RDC | Ossature RDC | 15
Montant | Comble et couverture | Epicéa C24 | 0.045 | 0.145 | 0.3845 | 0.9461 | 0.1409 | 0.154 | 0.0025 | 0.0024 | 0.0105 | 0.01 | 0 | MURS COMBLE | OB128 | 136
Ceinture | Premier Etage | NH II | 0.07 | 0.192 | 0.8466 | 2.5805 | 0.4302 | 0.4571 | 0.0114 | 0.0109 | 0 | 0 |  | Plancher étage | Solivage_192 | 1008
Ceinture | Premier Etage | NH II | 0.092 | 0.192 | 7.884 | 3.3915 | 4.4428 | 4.4781 | 0.1393 | 0.1376 | 0 | 0 |  | Plancher étage | Solivage_192 | 1018
latte 27/40 | Premier Etage | Epicéa C24 | 0.04 | 0.024 | 0.6805 | 0.023 | 0.0871 | 0.089 | 0.0007 | 0.0007 | 0.0027 | 0.0027 | 0 | MURS ETAGE | OB121 | 725
Montant | Rez de chaussée | Epicéa C24 | 0.045 | 0.22 | 1.8539 | 2.178 | 0.9825 | 1.0023 | 0.0184 | 0.0184 | 0.0771 | 0.0771 | 0 | MURS RDC | OB06 | 273
Montant | Premier Etage | Epicéa C24 | 0.045 | 0.22 | 2.5675 | 2.178 | 1.3554 | 1.3752 | 0.0254 | 0.0253 | 0.1068 | 0.1062 | 0 | MURS ETAGE | OB120 | 378
Lisse basse traitée | Dalle | Epicéa C24 Traité | 0.045 | 0.22 | 1.6294 | 2.178 | 0.8224 | 0.8422 | 0.0161 | 0.0153 | 0 | 0 | 0 | MURS RDC | Ossature RDC | 13
Montant | Premier Etage | Epicéa C24 | 0.045 | 0.22 | 1.9378 | 2.178 | 1.02 | 1.0398 | 0.0192 | 0.019 | 0.0806 | 0.0798 | 0 | MURS ETAGE | OB12 | 66
Montant | Premier Etage | Epicéa C24 | 0.045 | 0.22 | 1.2958 | 2.178 | 0.6798 | 0.6996 | 0.0128 | 0.0126 | 0.0539 | 0.0531 | 0 | MURS ETAGE | OB14 | 99
Montant | Premier Etage | Epicéa C24 | 0.045 | 0.145 | 2.5559 | 0.9461 | 0.9676 | 0.9806 | 0.0167 | 0.0166 | 0.07 | 0.0697 | 0 | MURS ETAGE | OB130 | 236
Ceinture | Premier Etage | NH II | 0.092 | 0.22 | 4.7758 | 4.4528 | 2.9599 | 3.0003 | 0.0967 | 0.0957 | 0 | 0 |  | Plancher étage | Solivage_220 | 1044
latte 27/40 | Premier Etage | Epicéa C24 | 0.04 | 0.024 | 1.7514 | 0.023 | 0.2242 | 0.2261 | 0.0017 | 0.0017 | 0.0071 | 0.0071 | 0 | MURS ETAGE | OB121 | 728
Montant | Premier Etage | Epicéa C24 | 0.045 | 0.22 | 1.0086 | 2.178 | 0.5172 | 0.537 | 0.01 | 0.0095 | 0.0419 | 0.0399 | 0 | MURS ETAGE | OB16 | 280
Lisse basse | Rez de chaussée | Epicéa C24 | 0.045 | 0.22 | 1.165 | 2.178 | 0.6174 | 0.6373 | 0.0115 | 0.0115 | 0.0484 | 0.0484 | 0 | MURS RDC | OB09 | 329
latte 27/40 | Premier Etage | Epicéa C24 | 0.04 | 0.024 | 1.893 | 0.023 | 0.2423 | 0.2442 | 0.0018 | 0.0018 | 0.0076 | 0.0076 | 0 | MURS ETAGE | OB120 | 716
Montant | Premier Etage | Epicéa C24 | 0.045 | 0.22 | 2.1331 | 2.178 | 1.1236 | 1.1434 | 0.0211 | 0.0209 | 0.0887 | 0.0879 | 0 | MURS ETAGE | OB14 | 102
Montant | Rez de chaussée | Epicéa C24 | 0.045 | 0.1414 | 2.54 | 0.8999 | 0.8843 | 0.897 | 0.0162 | 0.014 | 0.0679 | 0.0588 | 0 | MURS RDC | OB09 | 323
2 x latte chantier | Rez de chaussée | Epicéa C24 | 0.04 | 0.024 | 2.67 | 0.023 | 0.3418 | 0.3437 | 0.0026 | 0.0026 | 0.0108 | 0.0108 | 0 | MURS RDC | OB07 | 822
Montant | Rez de chaussée | Epicéa C24 | 0.045 | 0.22 | 1.4236 | 2.178 | 0.7545 | 0.7743 | 0.0141 | 0.0141 | 0.0592 | 0.0592 | 0 | MURS RDC | OB010 | 345
Ceinture | Premier Etage | NH II | 0.092 | 0.22 | 4.6838 | 4.4528 | 2.9227 | 2.9632 | 0.0948 | 0.0948 | 0 | 0 |  | Plancher étage | Solivage_220 | 1043
Montant | Premier Etage | Epicéa C24 | 0.045 | 0.199 | 1.0086 | 1.7823 | 0.4748 | 0.4927 | 0.009 | 0.0086 | 0.0379 | 0.0359 | 0 | MURS ETAGE | OB16 | 278
latte 27/40 | Premier Etage | Epicéa C24 | 0.04 | 0.024 | 0.649 | 0.023 | 0.0831 | 0.085 | 0.0006 | 0.0006 | 0.0026 | 0.0026 | 0 | MURS ETAGE | OB14 | 619
latte 27/40 | Premier Etage | Epicéa C24 | 0.04 | 0.024 | 1.2588 | 0.023 | 0.1611 | 0.163 | 0.0012 | 0.0012 | 0.0051 | 0.0051 | 0 | MURS ETAGE | OB120 | 713
contre poutre | Premier Etage | NH II | 0.027 | 0.165 | 0.6801 | 0.7351 | 0.2612 | 0.2701 | 0.003 | 0.003 | 0 | 0 |  | Plancher étage
contre poutre | Premier Etage | NH II | 0.027 | 0.165 | 1.7064 | 0.7351 | 0.6552 | 0.6642 | 0.0076 | 0.0076 | 0 | 0 |  | Plancher étage
contre poutre | Premier Etage | NH II | 0.027 | 0.165 | 1.3521 | 0.7351 | 0.5192 | 0.5281 | 0.006 | 0.006 | 0 | 0 |  | Plancher étage
Montant | Premier Etage | Epicéa C24 | 0.045 | 0.22 | 2.1124 | 2.178 | 1.1126 | 1.1324 | 0.0209 | 0.0207 | 0.0878 | 0.087 | 0 | MURS ETAGE | OB127 | 179
2 x Bras de force | Rez de chaussée | NH II | 0.16 | 0.16 | 1.4865 | 4.096 | 0.8462 | 0.8974 | 0.0387 | 0.0318 | 0 | 0 |  | Charpente | Ferme Garage | 1515
Montant | Premier Etage | Epicéa C24 | 0.045 | 0.1822 | 1.0086 | 1.4945 | 0.4325 | 0.4489 | 0.0083 | 0.0074 | 0.0347 | 0.0311 | 0 | MURS ETAGE | OB17 | 299
Montant | Rez de chaussée | Epicéa C24 | 0.045 | 0.145 | 1.07 | 0.9461 | 0.4066 | 0.4196 | 0.007 | 0.007 | 0.0293 | 0.0293 | 0 | MURS RDC | OB023 | 122
2 x Montant | Rez de chaussée | Epicéa C24 | 0.045 | 0.22 | 0.135 | 2.178 | 0.0715 | 0.0913 | 0.0013 | 0.0013 | 0.0056 | 0.0056 | 0 | MURS RDC | OB020 | 143
Chevron | Comble et couverture | NH II | 0.07 | 0.192 | 2.6679 | 2.5805 | 1.3224 | 1.3493 | 0.0359 | 0.0333 | 0 | 0 |  | Charpente | Chevrons | 2109
Chevron | Comble et couverture | NH II | 0.07 | 0.192 | 0.7636 | 2.5805 | 0.3223 | 0.3492 | 0.0103 | 0.0076 | 0 | 0 |  | Charpente | Chevrons | 2104
latte 27/40 | Rez de chaussée | Epicéa C24 | 0.04 | 0.024 | 2.5203 | 0.023 | 0.3226 | 0.3245 | 0.0024 | 0.0024 | 0.0102 | 0.0102 | 0 | MURS RDC | OB020 | 634
Montant | Premier Etage | Epicéa C24 | 0.045 | 0.1445 | 1.0086 | 0.9394 | 0.3563 | 0.3693 | 0.0066 | 0.0057 | 0.0275 | 0.0239 | 0 | MURS ETAGE | OB17 | 298
Chevron | Comble et couverture | NH II | 0.07 | 0.1919 | 4.042 | 2.5791 | 2.0503 | 2.0772 | 0.0543 | 0.0524 | 0 | 0 |  | Charpente | Chevrons | 2077
latte 27/40 | Rez de chaussée | Epicéa C24 | 0.04 | 0.024 | 2.2605 | 0.023 | 0.2893 | 0.2913 | 0.0022 | 0.0022 | 0.0091 | 0.0091 | 0 | MURS RDC | OB020 | 632
latte chantier | Rez de chaussée | Epicéa C24 | 0.04 | 0.024 | 2.2227 | 0.023 | 0.2845 | 0.2864 | 0.0021 | 0.0021 | 0.009 | 0.009 | 0 | MURS RDC | D1 | 807
Poutre Lc | Premier Etage | NH II | 0.1 | 0.2 | 3.1585 | 4 | 1.8938 | 1.9338 | 0.0637 | 0.0631 | 0 | 0 |  | Plancher étage | Poutrage_plancher_etage | 1002
Chevron | Comble et couverture | NH II | 0.092 | 0.192 | 5.4036 | 3.3915 | 3.0156 | 3.051 | 0.0954 | 0.0936 | 0 | 0 |  | Charpente | Chevrons | 2096
Montant | Premier Etage | Epicéa C24 | 0.045 | 0.22 | 1.0086 | 2.178 | 0.5087 | 0.5285 | 0.01 | 0.0091 | 0.0419 | 0.0383 | 0 | MURS ETAGE | OB17 | 304
Chevron | Comble et couverture | NH II | 0.07 | 0.192 | 4.7095 | 2.5805 | 2.3764 | 2.4033 | 0.0633 | 0.0605 | 0 | 0 |  | Charpente | Chevrons | 2026
Montant | Rez de chaussée | Epicéa C24 | 0.045 | 0.22 | 2.54 | 2.178 | 1.3038 | 1.3236 | 0.0251 | 0.0239 | 0.1056 | 0.1006 | 0 | MURS RDC | OB06 | 276
Poutre Lc | Premier Etage | NH II | 0.1 | 0.2 | 3.1585 | 4 | 1.8938 | 1.9338 | 0.0637 | 0.0631 | 0 | 0 |  | Plancher étage | Poutrage_plancher_etage | 1003
Chevron | Comble et couverture | NH II | 0.07 | 0.192 | 2.3376 | 2.5805 | 1.1336 | 1.1605 | 0.0314 | 0.0287 | 0 | 0 |  | Charpente | Chevrons | 2015
Montant | Premier Etage | Epicéa C24 | 0.045 | 0.22 | 0.1582 | 2.178 | 0.0839 | 0.1037 | 0.0016 | 0.0016 | 0.0066 | 0.0066 | 0 | MURS ETAGE | OB120 | 356
Chevron | Comble et couverture | NH II | 0.092 | 0.192 | 5.4354 | 3.3915 | 3.0191 | 3.0545 | 0.096 | 0.0937 | 0 | 0 |  | Charpente | Chevrons | 2036
Chevron | Comble et couverture | NH II | 0.07 | 0.192 | 2.3869 | 2.5805 | 1.165 | 1.1919 | 0.0321 | 0.0296 | 0 | 0 |  | Charpente | Chevrons | 2016
Montant | Premier Etage | Epicéa C24 | 0.045 | 0.145 | 0.87 | 0.9461 | 0.3306 | 0.3436 | 0.0057 | 0.0057 | 0.0238 | 0.0238 | 0 | MURS ETAGE | OB128 | 129
contre poutre | Premier Etage | NH II | 0.027 | 0.165 | 3.384 | 0.7351 | 1.2995 | 1.3084 | 0.0151 | 0.0151 | 0 | 0 |  | Plancher étage
Chevron | Comble et couverture | NH II | 0.07 | 0.192 | 3.4843 | 2.5805 | 1.7344 | 1.7613 | 0.0468 | 0.0441 | 0 | 0 |  | Charpente | Chevrons | 2021
Chevron | Comble et couverture | NH II | 0.092 | 0.192 | 5.4354 | 3.3915 | 3.0191 | 3.0545 | 0.096 | 0.0937 | 0 | 0 |  | Charpente | Chevrons | 2035
2 x Montant | Premier Etage | Epicéa C24 | 0.045 | 0.22 | 0.5 | 2.178 | 0.265 | 0.2848 | 0.0049 | 0.005 | 0.0208 | 0.0208 | 0 | MURS ETAGE | OB123 | 482
2 x latte 27/40 | Premier Etage | Epicéa C24 | 0.04 | 0.024 | 0.153 | 0.023 | 0.0196 | 0.0215 | 0.0001 | 0.0001 | 0.0006 | 0.0006 | 0 | MURS ETAGE | OB14 | 617
Montant | Rez de chaussée | Epicéa C24 | 0.02 | 0.22 | 0.73 | 0.968 | 0.3504 | 0.3592 | 0.0032 | 0.0032 | 0.0135 | 0.0135 | 0 | MURS RDC | OB015 | 464
contre poutre | Premier Etage | NH II | 0.027 | 0.165 | 3.077 | 0.7351 | 1.1816 | 1.1905 | 0.0137 | 0.0137 | 0 | 0 |  | Plancher étage
latte 27/40 | Rez de chaussée | Epicéa C24 | 0.04 | 0.024 | 2.6714 | 0.023 | 0.3419 | 0.3439 | 0.0026 | 0.0026 | 0.0108 | 0.0108 | 0 | MURS RDC | OB020 | 635
Lisse basse | Rez de chaussée | Epicéa C24 | 0.045 | 0.22 | 1.3947 | 2.178 | 0.7392 | 0.759 | 0.0138 | 0.0138 | 0.058 | 0.058 | 0 | MURS RDC | OB027 | 349
Montant | Rez de chaussée | Epicéa C24 | 0.045 | 0.22 | 1.3947 | 2.178 | 0.7392 | 0.759 | 0.0138 | 0.0138 | 0.058 | 0.058 | 0 | MURS RDC | OB027 | 349
Montant | Rez de chaussée | Epicéa C24 | 0.045 | 0.22 | 0.1701 | 2.178 | 0.0902 | 0.11 | 0.0017 | 0.0017 | 0.0071 | 0.0071 | 0 | MURS RDC | OB020 | 144
latte 27/40 | Premier Etage | Epicéa C24 | 0.04 | 0.024 | 1.1793 | 0.023 | 0.1509 | 0.1529 | 0.0011 | 0.0011 | 0.0048 | 0.0048 | 0 | MURS ETAGE | OB120 | 710
Montant | Premier Etage | Epicéa C24 | 0.045 | 0.1851 | 0.9244 | 1.5417 | 0.3965 | 0.4132 | 0.0077 | 0.0066 | 0.0323 | 0.0277 | 0 | MURS ETAGE | OB19 | 336
2 x Montant | Rez de chaussée | Epicéa C24 | 0.045 | 0.145 | 2.16 | 0.9461 | 0.8208 | 0.8338 | 0.0141 | 0.0141 | 0.0592 | 0.0592 | 0 | MURS RDC | OB022 | 117
contre poutre | Premier Etage | NH II | 0.027 | 0.165 | 1.066 | 0.7351 | 0.4093 | 0.4182 | 0.0047 | 0.0047 | 0 | 0 |  | Plancher étage
Panne | Comble et couverture | NH II | 0.16 | 0.24 | 6.2385 | 9.216 | 4.9768 | 5.0536 | 0.2396 | 0.2354 | 0 | 0 |  | Charpente | Toiture garage | 1521
2 x Chevron | Comble et couverture | NH II | 0.07 | 0.192 | 1.1193 | 2.5805 | 0.5637 | 0.5905 | 0.0151 | 0.0145 | 0 | 0 |  | Charpente | Chevrons | 2070
Panne | Comble et couverture | NH II | 0.16 | 0.24 | 6.2385 | 9.216 | 4.9577 | 5.0345 | 0.2396 | 0.2365 | 0 | 0 |  | Charpente | Toiture garage | 1522
Montant | Rez de chaussée | Epicéa C24 | 0.045 | 0.22 | 1.8389 | 2.178 | 0.9746 | 0.9944 | 0.0182 | 0.0182 | 0.0765 | 0.0765 | 0 | MURS RDC | OB013 | 435
Chevron | Comble et couverture | NH II | 0.07 | 0.192 | 1.5955 | 2.5805 | 0.8132 | 0.8401 | 0.0215 | 0.0209 | 0 | 0 |  | Charpente | Chevrons | 2067
Montant | Premier Etage | Epicéa C24 | 0.045 | 0.22 | 0.8147 | 2.178 | 0.428 | 0.4478 | 0.0081 | 0.008 | 0.0339 | 0.0335 | 0 | MURS ETAGE | OB19 | 340
Poutre Lc | Premier Etage | NH II | 0.2 | 0.24 | 2.8354 | 11.52 | 2.484 | 2.58 | 0.1361 | 0.1348 | 0 | 0 |  | Plancher étage | Poutrage_plancher_etage | 1004
latte 27/40 | Premier Etage | Epicéa C24 | 0.04 | 0.024 | 1.508 | 0.023 | 0.193 | 0.1949 | 0.0014 | 0.0014 | 0.0061 | 0.0061 | 0 | MURS ETAGE | OB120 | 714
Solive | Premier Etage | NH II | 0.092 | 0.22 | 6.896 | 4.4528 | 4.2918 | 4.3323 | 0.1406 | 0.1391 | 0 | 0 |  | Plancher étage | Solivage_220 | 1056
Montant | Premier Etage | Epicéa C24 | 0.045 | 0.22 | 1.4475 | 2.178 | 0.7618 | 0.7816 | 0.0143 | 0.0142 | 0.0602 | 0.0596 | 0 | MURS ETAGE | OB120 | 381
Montant | Premier Etage | Epicéa C24 | 0.045 | 0.22 | 1.4216 | 2.178 | 0.7481 | 0.7679 | 0.0141 | 0.0139 | 0.0591 | 0.0586 | 0 | MURS ETAGE | OB120 | 366
3 x Montant | Rez de chaussée | Epicéa C24 | 0.045 | 0.22 | 2.43 | 2.178 | 1.2879 | 1.3077 | 0.0241 | 0.0241 | 0.101 | 0.101 | 0 | MURS RDC | OB020 | 152
Montant | Premier Etage | Epicéa C24 | 0.045 | 0.1315 | 0.9244 | 0.7778 | 0.2974 | 0.3092 | 0.0055 | 0.0044 | 0.023 | 0.0183 | 0 | MURS ETAGE | OB19 | 334
Chevron | Comble et couverture | NH II | 0.07 | 0.192 | 1.5955 | 2.5805 | 0.8132 | 0.84 | 0.0215 | 0.0209 | 0 | 0 |  | Charpente | Chevrons | 2067
Montant | Rez de chaussée | Epicéa C24 | 0.045 | 0.178 | 2.54 | 1.4263 | 1.0906 | 1.1066 | 0.0203 | 0.0191 | 0.0855 | 0.0804 | 0 | MURS RDC | OB06 | 269
Poutre Lc | Premier Etage | NH II | 0.2 | 0.24 | 5.8445 | 11.52 | 5.1447 | 5.2407 | 0.2805 | 0.2799 | 0 | 0 |  | Plancher étage | Poutrage_plancher_etage | 1006
Panne | Comble et couverture | NH II | 0.16 | 0.24 | 1.5303 | 9.216 | 1.2034 | 1.2802 | 0.0588 | 0.057 | 0 | 0 |  | Charpente | Toiture mezzanine | 1543
Panne | Comble et couverture | NH II | 0.16 | 0.24 | 2.9139 | 9.216 | 2.3199 | 2.3967 | 0.1119 | 0.1096 | 0 | 0 |  | Charpente | Toiture mezzanine | 1535
Montant | Premier Etage | Epicéa C24 | 0.045 | 0.22 | 1.8414 | 2.178 | 0.9706 | 0.9904 | 0.0182 | 0.0181 | 0.0766 | 0.076 | 0 | MURS ETAGE | OB120 | 370
Montant | Premier Etage | Epicéa C24 | 0.045 | 0.22 | 0.6367 | 2.178 | 0.3324 | 0.3522 | 0.0063 | 0.0062 | 0.0265 | 0.026 | 0 | MURS ETAGE | OB121 | 421
Montant | Premier Etage | Epicéa C24 | 0.045 | 0.22 | 2.8075 | 2.178 | 1.4718 | 1.4916 | 0.0278 | 0.0273 | 0.1167 | 0.1146 | 0 | MURS ETAGE | OB120 | 382
latte 27/40 | Premier Etage | Epicéa C24 | 0.04 | 0.024 | 1.5603 | 0.023 | 0.1997 | 0.2016 | 0.0015 | 0.0015 | 0.0063 | 0.0063 | 0 | MURS COMBLE | OB127 | 667
Main courante | Premier Etage | NH II | 0.045 | 0.14 | 1.2838 | 0.882 | 0.4687 | 0.4813 | 0.0081 | 0.0076 | 0 | 0 |  | Balcon Etage | balustrade | 5005
Montant | Premier Etage | Epicéa C24 | 0.045 | 0.145 | 0.0912 | 0.9461 | 0.031 | 0.0441 | 0.0006 | 0.0005 | 0.0025 | 0.0022 | 0 | MURS ETAGE | OB130 | 210
Montant | Premier Etage | Epicéa C24 | 0.045 | 0.22 | 0.135 | 2.178 | 0.0715 | 0.0913 | 0.0013 | 0.0013 | 0.0056 | 0.0056 | 0 | MURS COMBLE | OB127 | 184
Montant | Premier Etage | Epicéa C24 | 0.045 | 0.22 | 1.2518 | 2.178 | 0.6495 | 0.6693 | 0.0124 | 0.012 | 0.052 | 0.0505 | 0 | MURS ETAGE | OB14 | 98
latte 27/40 | Premier Etage | Epicéa C24 | 0.04 | 0.024 | 0.8276 | 0.023 | 0.1059 | 0.1078 | 0.0008 | 0.0008 | 0.0033 | 0.0033 | 0 | MURS ETAGE | OB120 | 707
latte 27/40 | Premier Etage | Epicéa C24 | 0.04 | 0.024 | 0.7951 | 0.023 | 0.1018 | 0.1037 | 0.0008 | 0.0008 | 0.0032 | 0.0032 | 0 | MURS ETAGE | OB120 | 706
latte 27/40 | Premier Etage | Epicéa C24 | 0.04 | 0.024 | 1.2263 | 0.023 | 0.157 | 0.1589 | 0.0012 | 0.0012 | 0.0049 | 0.0049 | 0 | MURS ETAGE | OB120 | 712
latte 27/40 | Premier Etage | Epicéa C24 | 0.04 | 0.024 | 1.0637 | 0.023 | 0.1361 | 0.1381 | 0.001 | 0.001 | 0.0043 | 0.0043 | 0 | MURS ETAGE | OB120 | 709
Montant | Premier Etage | Epicéa C24 | 0.045 | 0.2036 | 0.27 | 1.8658 | 0.1299 | 0.1482 | 0.0025 | 0.0024 | 0.0104 | 0.01 | 0 | MURS ETAGE | OB122 | 443
latte 27/40 | Premier Etage | Epicéa C24 | 0.04 | 0.024 | 0.86 | 0.023 | 0.1101 | 0.112 | 0.0008 | 0.0008 | 0.0035 | 0.0035 | 0 | MURS ETAGE | OB120 | 708
Montant | Premier Etage | Epicéa C24 | 0.045 | 0.22 | 1.8747 | 2.178 | 0.9882 | 1.008 | 0.0186 | 0.0184 | 0.078 | 0.0774 | 0 | MURS ETAGE | OB120 | 372
Montant | Premier Etage | Epicéa C24 | 0.045 | 0.22 | 2.7006 | 2.178 | 1.4259 | 1.4457 | 0.0267 | 0.0266 | 0.1123 | 0.1117 | 0 | MURS ETAGE | OB120 | 379
Chevron | Comble et couverture | NH II | 0.092 | 0.192 | 5.4036 | 3.3915 | 3.0156 | 3.051 | 0.0954 | 0.0936 | 0 | 0 |  | Charpente | Chevrons | 2097
Montant | Premier Etage | Epicéa C24 | 0.045 | 0.145 | 2.3286 | 0.9461 | 0.8809 | 0.894 | 0.0152 | 0.0151 | 0.0638 | 0.0635 | 0 | MURS ETAGE | OB131 | 508
Panne | Comble et couverture | NH II | 0.16 | 0.2 | 1.6573 | 6.4 | 1.0394 | 1.1034 | 0.053 | 0.0444 | 0 | 0 |  | Charpente | Toiture mezzanine | 1532
Chevetre | Comble et couverture | NH II | 0.07 | 0.192 | 1.39 | 2.5805 | 0.7284 | 0.7552 | 0.0188 | 0.0187 | 0 | 0 |  | Chevrons | Toiture mezzanine | 2116
Chevetre | Comble et couverture | NH II | 0.07 | 0.192 | 1.39 | 2.5805 | 0.7284 | 0.7552 | 0.0188 | 0.0187 | 0 | 0 |  | Chevrons | Toiture mezzanine | 2115
Cache moineau | Comble et couverture | NH II | 0.07 | 0.22 | 0.914 | 3.388 | 0.4505 | 0.4813 | 0.0141 | 0.0117 | 0 | 0 |  | Chevrons | Toiture mezzanine | 2053
Montant | Premier Etage | Epicéa C24 | 0.045 | 0.22 | 1.6537 | 2.178 | 0.8695 | 0.8893 | 0.0164 | 0.0162 | 0.0688 | 0.068 | 0 | MURS ETAGE | OB127 | 173
Lisse basse traitée | Dalle | Epicéa C24 Traité | 0.045 | 0.145 | 4.1574 | 0.9461 | 1.5798 | 1.5929 | 0.0271 | 0.0271 | 0 | 0 | 0 | MURS RDC | Ossature RDC | 7
Montant | Rez de chaussée | Epicéa C24 | 0.045 | 0.103 | 2.54 | 0.4777 | 0.7096 | 0.7188 | 0.0118 | 0.0106 | 0.0495 | 0.0444 | 0 | MURS RDC | OB019 | 470
Montant | Premier Etage | Epicéa C24 | 0.045 | 0.22 | 0.2818 | 2.178 | 0.1493 | 0.1691 | 0.0028 | 0.0028 | 0.0117 | 0.0117 | 0 | MURS COMBLE | OB12 | 73
Montant | Premier Etage | Epicéa C24 | 0.0279 | 0.22 | 0.2818 | 1.3513 | 0.1397 | 0.152 | 0.0017 | 0.0017 | 0.0073 | 0.0073 | 0 | MURS COMBLE | OB12 | 71
Montant | Rez de chaussée | Epicéa C24 | 0.02 | 0.22 | 0.73 | 0.968 | 0.3504 | 0.3592 | 0.0032 | 0.0032 | 0.0135 | 0.0135 | 0 | MURS RDC | OB019 | 473
Lisse basse | Premier Etage | Epicéa C24 | 0.045 | 0.145 | 4.6807 | 0.9461 | 1.7787 | 1.7917 | 0.0305 | 0.0305 | 0.1283 | 0.1283 | 0 | Plancher étage | ETA | 31
Montant | Rez de chaussée | Epicéa C24 | 0.045 | 0.2036 | 2.665 | 1.8658 | 1.2885 | 1.3068 | 0.0244 | 0.0234 | 0.1026 | 0.0984 | 0 | MURS RDC | OB012 | 406
Montant | Premier Etage | Epicéa C24 | 0.045 | 0.22 | 1.71 | 2.178 | 0.9063 | 0.9261 | 0.0169 | 0.0169 | 0.0711 | 0.0711 | 0 | MURS ETAGE | OB121 | 424
Montant | Rez de chaussée | Epicéa C24 | 0.045 | 0.22 | 2.935 | 2.178 | 1.5067 | 1.5265 | 0.0291 | 0.0277 | 0.122 | 0.1162 | 0 | MURS RDC | OB014 | 463
Montant | Premier Etage | Epicéa C24 | 0.045 | 0.22 | 0.6403 | 2.178 | 0.3356 | 0.3554 | 0.0063 | 0.0063 | 0.0266 | 0.0263 | 0 | MURS ETAGE | OB19 | 339
Montant | Premier Etage | Epicéa C24 | 0.045 | 0.22 | 0.6463 | 2.178 | 0.3356 | 0.3554 | 0.0064 | 0.0062 | 0.0269 | 0.0261 | 0 | MURS COMBLE | OB12 | 74
latte 27/40 | Premier Etage | Epicéa C24 | 0.04 | 0.024 | 1.7514 | 0.023 | 0.2242 | 0.2261 | 0.0017 | 0.0017 | 0.0071 | 0.0071 | 0 | MURS ETAGE | OB122 | 737
Montant | Premier Etage | Epicéa C24 | 0.045 | 0.1286 | 1.4453 | 0.7445 | 0.4816 | 0.4932 | 0.0084 | 0.0078 | 0.0351 | 0.0329 | 0 | MURS ETAGE | OB122 | 441
Montant | Premier Etage | Epicéa C24 | 0.045 | 0.22 | 1.7114 | 2.178 | 0.907 | 0.9268 | 0.0169 | 0.0169 | 0.0712 | 0.0712 | 0 | MURS ETAGE | OB122 | 450
Montant | Premier Etage | Epicéa C24 | 0.045 | 0.1122 | 1.4453 | 0.5669 | 0.4343 | 0.4444 | 0.0073 | 0.0068 | 0.0307 | 0.0284 | 0 | MURS ETAGE | OB122 | 440
Montant | Premier Etage | Epicéa C24 | 0.045 | 0.22 | 0.27 | 2.178 | 0.1387 | 0.1585 | 0.0027 | 0.0026 | 0.0112 | 0.0108 | 0 | MURS ETAGE | OB122 | 444
Montant | Premier Etage | Epicéa C24 | 0.045 | 0.22 | 0.7144 | 2.178 | 0.3679 | 0.3877 | 0.0071 | 0.0068 | 0.0297 | 0.0286 | 0 | MURS ETAGE | OB126 | 541
Montant | Premier Etage | Epicéa C24 | 0.045 | 0.22 | 0.6123 | 2.178 | 0.3245 | 0.3443 | 0.0061 | 0.0061 | 0.0255 | 0.0255 | 0 | MURS ETAGE | OB122 | 450
latte 27/40 | Premier Etage | Epicéa C24 | 0.04 | 0.024 | 0.6805 | 0.023 | 0.0871 | 0.089 | 0.0007 | 0.0007 | 0.0027 | 0.0027 | 0 | MURS ETAGE | OB122 | 734
Montant | Premier Etage | Epicéa C24 | 0.045 | 0.22 | 1.7401 | 2.178 | 0.9153 | 0.9351 | 0.0172 | 0.017 | 0.0724 | 0.0716 | 0 | MURS ETAGE | OB12 | 65
Montant | Premier Etage | Epicéa C24 | 0.045 | 0.22 | 0.6635 | 2.178 | 0.3517 | 0.3715 | 0.0066 | 0.0066 | 0.0276 | 0.0276 | 0 | MURS ETAGE | OB121 | 424
latte 27/40 | Premier Etage | Epicéa C24 | 0.04 | 0.024 | 1.5606 | 0.023 | 0.1998 | 0.2017 | 0.0015 | 0.0015 | 0.0063 | 0.0063 | 0 | MURS ETAGE | OB127 | 653
Solive | Premier Etage | NH II | 0.092 | 0.22 | 3.1095 | 4.4528 | 1.8944 | 1.9349 | 0.0629 | 0.0607 | 0 | 0 |  | Plancher étage | Solivage_220 | 1051
Montant | Premier Etage | Epicéa C24 | 0.045 | 0.22 | 1.8057 | 2.178 | 0.9413 | 0.9611 | 0.0179 | 0.0174 | 0.0751 | 0.0732 | 0 | MURS ETAGE | OB127 | 176
Montant | Premier Etage | Epicéa C24 | 0.045 | 0.22 | 3.8884 | 2.178 | 2.0608 | 2.0806 | 0.0385 | 0.0385 | 0.1617 | 0.1617 | 0 | MURS ETAGE | OB127 | 183
Montant | Premier Etage | Epicéa C24 | 0.045 | 0.22 | 1.4594 | 2.178 | 0.7578 | 0.7776 | 0.0144 | 0.014 | 0.0607 | 0.0588 | 0 | MURS ETAGE | OB127 | 172
Chevetre | Comble et couverture | NH II | 0.07 | 0.15 | 0.476 | 1.575 | 0.2094 | 0.2304 | 0.0051 | 0.005 | 0 | 0 |  | Chevrons | Toiture mezzanine | 2055
Solive | Premier Etage | NH II | 0.092 | 0.22 | 7.0989 | 4.4528 | 4.4184 | 4.4589 | 0.1447 | 0.1432 | 0 | 0 |  | Plancher étage | Solivage_220 | 1057
Solive | Premier Etage | NH II | 0.092 | 0.22 | 7.3939 | 4.4528 | 4.5822 | 4.6227 | 0.1501 | 0.1483 | 0 | 0 |  | Plancher étage | Solivage_220 | 1058
Solive | Premier Etage | NH II | 0.092 | 0.22 | 7.4288 | 4.4528 | 4.6243 | 4.6648 | 0.1513 | 0.1499 | 0 | 0 |  | Plancher étage | Solivage_220 | 1059
Solive | Premier Etage | NH II | 0.092 | 0.22 | 5.6472 | 4.4528 | 3.5126 | 3.5531 | 0.1153 | 0.1139 | 0 | 0 |  | Plancher étage | Solivage_220 | 1053
Solive | Premier Etage | NH II | 0.092 | 0.22 | 7.6318 | 4.4528 | 4.7509 | 4.7914 | 0.1555 | 0.154 | 0 | 0 |  | Plancher étage | Solivage_220 | 1060
Solive | Premier Etage | NH II | 0.092 | 0.22 | 8.0377 | 4.4528 | 5.0042 | 5.0447 | 0.1637 | 0.1622 | 0 | 0 |  | Plancher étage | Solivage_220 | 1062
Solive | Premier Etage | NH II | 0.092 | 0.22 | 4.7413 | 4.4528 | 2.9586 | 2.9991 | 0.0965 | 0.096 | 0 | 0 |  | Plancher étage | Solivage_220 | 1063

# IfcPlate (224)
Name | In | Material | Width (m) | Height (m) | Length (m) | CrossSectionArea (m2) | OuterfaceArea (m2) | TotalSurfaceArea (m2) | GrossVolume (m3) | NetVolume (m3) | GrossWeight | NetWeight | SKU | Group | SubGroup
Panneau de contreventement MFP | Rez de chaussée | OSB | 0.86 | 0.012 | 0.503 | 0.1238 | 0.8772 | 0.8979 | 0.0052 | 0.0052 | 0.0415 | 0.0415 | 0 | MURS RDC | OB04
Panneau de contreventement MFP | Rez de chaussée | OSB | 1.196 | 0.012 | 2.758 | 0.1722 | 4.9805 | 5.0093 | 0.0396 | 0.0294 | 0.3167 | 0.2354 | 0 | MURS RDC | OB04
Panneau de contreventement MFP | Rez de chaussée | OSB | 1.196 | 0.012 | 2.758 | 0.1722 | 4.7373 | 4.766 | 0.0396 | 0.0279 | 0.3167 | 0.2236 | 0 | MURS RDC | OB01
Panneau de contreventement MFP | Premier Etage | OSB | 1.196 | 0.012 | 2.6248 | 0.1722 | 5.5874 | 5.6161 | 0.0377 | 0.0332 | 0.3014 | 0.2654 | 0 | MURS ETAGE | OB130
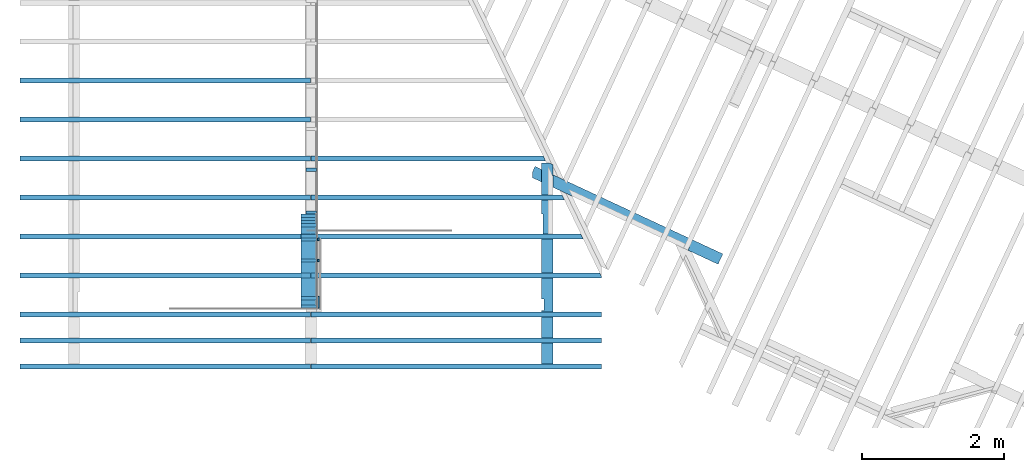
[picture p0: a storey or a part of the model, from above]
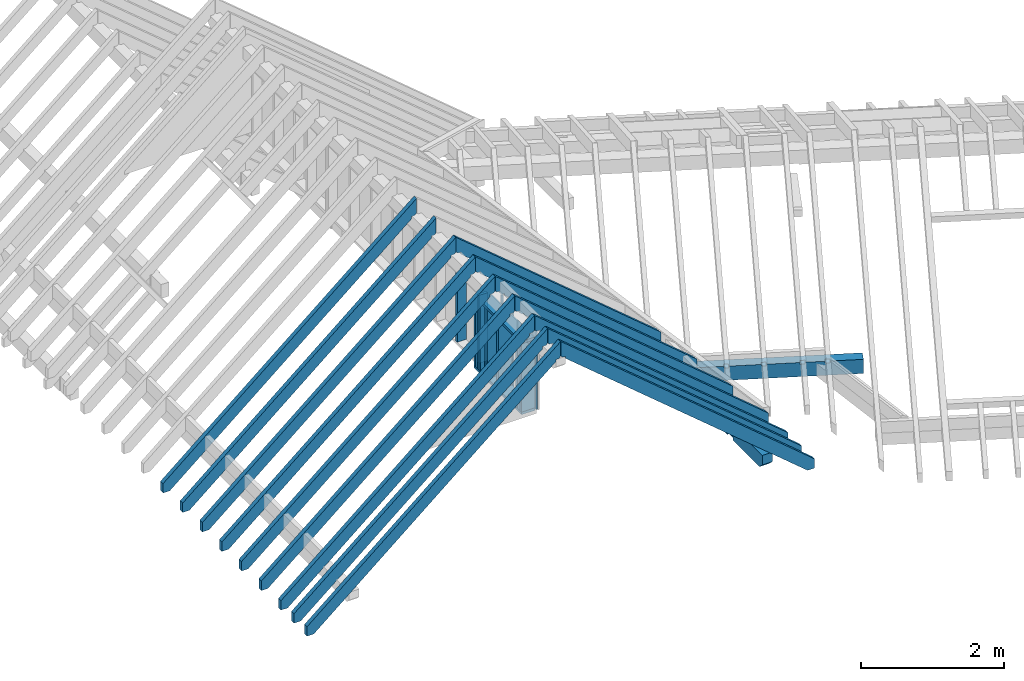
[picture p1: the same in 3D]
Properties of the parts of a building model (IFC2X3), part 4 of 4

# IfcPlate (224)
Name | In | Material | Width (m) | Height (m) | Length (m) | CrossSectionArea (m2) | OuterfaceArea (m2) | TotalSurfaceArea (m2) | GrossVolume (m3) | NetVolume (m3) | GrossWeight | NetWeight | SKU | Group | SubGroup
5 x Panneau de contreventement MFP | Premier Etage | OSB | 1.196 | 0.012 | 1.2128 | 0.1722 | 2.9302 | 2.9589 | 0.0174 | 0.0174 | 0.1393 | 0.1393 | 0 | MURS ETAGE | OB11
Panneau de contreventement MFP | Rez de chaussée | OSB | 0.86 | 0.012 | 0.124 | 0.1238 | 0.2163 | 0.2369 | 0.0013 | 0.0013 | 0.0102 | 0.0102 | 0 | MURS RDC | OB04
Panneau de contreventement MFP | Premier Etage | OSB | 0.7029 | 0.012 | 2.8 | 0.1012 | 3.9914 | 4.0083 | 0.0236 | 0.0235 | 0.1889 | 0.1884 | 0 | MURS ETAGE | OB125
Bardage | Rez de chaussée | Mélèze | 1.1871 | 0.021 | 2.765 | 0.5235 | 5.46 | 5.5099 | 0.0689 | 0.0554 | 0.507 | 0.4073 |  | MURS RDC | OB019
Panneau de contreventement MFP | Rez de chaussée | OSB | 1.196 | 0.012 | 2.758 | 0.1722 | 5.6871 | 5.7158 | 0.0396 | 0.0337 | 0.3167 | 0.2695 | 0 | MURS RDC | OB020
Panneau de contreventement MFP | Rez de chaussée | OSB | 1.196 | 0.012 | 2.758 | 0.1722 | 4.7396 | 4.7683 | 0.0396 | 0.0279 | 0.3167 | 0.2234 | 0 | MURS RDC | OB020
Panneau de contreventement MFP | Rez de chaussée | OSB | 1.196 | 0.012 | 2.73 | 0.1722 | 5.345 | 5.3737 | 0.0392 | 0.0314 | 0.3134 | 0.2515 | 0 | MURS RDC | OB019
Bardage | Rez de chaussée | Mélèze | 7.924 | 0.021 | 2.793 | 3.4945 | 38.1179 | 38.4507 | 0.4648 | 0.3959 | 3.4184 | 2.9118 |  | MURS RDC | OB01
Panneau de contreventement MFP | Rez de chaussée | OSB | 0.7411 | 0.012 | 2.758 | 0.1067 | 2.6431 | 2.6609 | 0.0245 | 0.0154 | 0.1962 | 0.123 | 0 | MURS RDC | OB020
Panneau de contreventement MFP | Rez de chaussée | OSB | 1.196 | 0.012 | 2.705 | 0.1722 | 2.6535 | 2.6822 | 0.0388 | 0.0154 | 0.3106 | 0.1232 | 0 | MURS RDC | OB012
5 x Panneau de contreventement MFP | Comble et couverture | OSB | 1.196 | 0.012 | 1.245 | 0.1722 | 3.0079 | 3.0366 | 0.0179 | 0.0179 | 0.1429 | 0.1429 | 0 | MURS COMBLE | OB129
Panneau de contreventement MFP | Rez de chaussée | OSB | 1.196 | 0.012 | 2.758 | 0.1722 | 3.1219 | 3.1506 | 0.0396 | 0.0182 | 0.3167 | 0.1457 | 0 | MURS RDC | OB020
Panneau de contreventement MFP | Rez de chaussée | OSB | 0.9225 | 0.012 | 2.8 | 0.1328 | 5.233 | 5.2552 | 0.031 | 0.031 | 0.248 | 0.248 | 0 | MURS RDC | OB011
Panneau de contreventement MFP | Premier Etage | OSB | 1.196 | 0.012 | 1.5959 | 0.1722 | 3.2374 | 3.2661 | 0.0229 | 0.0192 | 0.1832 | 0.1535 | 0 | MURS COMBLE | OB127
Panneau de contreventement MFP | Premier Etage | OSB | 1.196 | 0.012 | 2.7705 | 0.1722 | 6.6858 | 6.7145 | 0.0398 | 0.0397 | 0.3181 | 0.3177 | 0 | MURS ETAGE | OB13
Panneau de contreventement MFP | Premier Etage | OSB | 1.196 | 0.012 | 1.2962 | 0.1722 | 1.9236 | 1.9523 | 0.0186 | 0.0114 | 0.1488 | 0.0912 | 0 | MURS COMBLE | OB127
Panneau de contreventement MFP | Rez de chaussée | OSB | 1.0539 | 0.012 | 2.705 | 0.1518 | 2.4804 | 2.5057 | 0.0342 | 0.0144 | 0.2737 | 0.115 | 0 | MURS RDC | OB013
Panneau de contreventement MFP | Rez de chaussée | OSB | 0.8162 | 0.012 | 2.8 | 0.1175 | 4.638 | 4.6576 | 0.0274 | 0.0274 | 0.2194 | 0.2194 | 0 | MURS RDC | OB016
2 x Panneau de contreventement MFP | Premier Etage | OSB | 1.196 | 0.012 | 2.7705 | 0.1722 | 6.6935 | 6.7222 | 0.0398 | 0.0398 | 0.3181 | 0.3181 | 0 | MURS ETAGE | OB129
Panneau de contreventement MFP | Premier Etage | OSB | 1.19 | 0.012 | 0.9986 | 0.1714 | 1.2047 | 1.2332 | 0.0143 | 0.0071 | 0.1141 | 0.057 | 0 | MURS COMBLE | OB127
Panneau de contreventement MFP | Rez de chaussée | OSB | 0.0876 | 0.012 | 2.8 | 0.0126 | 0.558 | 0.5601 | 0.0029 | 0.0029 | 0.0236 | 0.0236 | 0 | MURS RDC | OB08
Bardage | Rez de chaussée | Mélèze | 6.7211 | 0.021 | 2.793 | 2.964 | 29.1145 | 29.3968 | 0.3942 | 0.3017 | 2.8994 | 2.2189 |  | MURS RDC | OB020
Panneau de contreventement MFP | Rez de chaussée | OSB | 1.196 | 0.012 | 2.758 | 0.1722 | 5.4237 | 5.4524 | 0.0396 | 0.0321 | 0.3167 | 0.2567 | 0 | MURS RDC | OB04
Panneau de contreventement MFP | Comble et couverture | OSB | 0.3432 | 0.012 | 1.245 | 0.0494 | 0.8844 | 0.8926 | 0.0051 | 0.0051 | 0.041 | 0.041 | 0 | MURS COMBLE | OB129
Panneau de contreventement MFP | Rez de chaussée | OSB | 1.196 | 0.012 | 2.758 | 0.1722 | 4.5334 | 4.5621 | 0.0396 | 0.0265 | 0.3167 | 0.2117 | 0 | MURS RDC | OB01
Panneau de contreventement MFP | Rez de chaussée | OSB | 1.196 | 0.012 | 2.758 | 0.1722 | 5.7195 | 5.7482 | 0.0396 | 0.0339 | 0.3167 | 0.271 | 0 | MURS RDC | OB01
Panneau de contreventement MFP | Premier Etage | OSB | 1.196 | 0.012 | 2.2018 | 0.1722 | 4.4878 | 4.5165 | 0.0316 | 0.0266 | 0.2528 | 0.2132 | 0 | MURS ETAGE | OB131
Panneau de contreventement MFP | Rez de chaussée | OSB | 1.196 | 0.012 | 2.758 | 0.1722 | 5.2185 | 5.2472 | 0.0396 | 0.0309 | 0.3167 | 0.2468 | 0 | MURS RDC | OB01
2 x Panneau de contreventement MFP | Rez de chaussée | OSB | 1.196 | 0.012 | 2.758 | 0.1722 | 6.6633 | 6.692 | 0.0396 | 0.0396 | 0.3167 | 0.3167 | 0 | MURS RDC | OB01
Panneau de contreventement MFP | Rez de chaussée | OSB | 0.684 | 0.012 | 2.758 | 0.0985 | 3.8391 | 3.8556 | 0.0226 | 0.0226 | 0.1811 | 0.1811 | 0 | MURS RDC | OB01
Bardage | Premier Etage | Mélèze | 0.8112 | 0.021 | 1.5442 | 0.3577 | 2.151 | 2.185 | 0.0263 | 0.0219 | 0.1935 | 0.1614 |  | MURS ETAGE | OB126
Panneau de contreventement MFP | Rez de chaussée | OSB | 0.1208 | 0.012 | 2.568 | 0.0174 | 0.6822 | 0.6851 | 0.0037 | 0.0037 | 0.0298 | 0.0298 | 0 | MURS RDC | OB03
Bardage | Premier Etage | Mélèze | 0.8112 | 0.021 | 1.5442 | 0.3577 | 2.151 | 2.185 | 0.0263 | 0.0219 | 0.1935 | 0.1614 |  | MURS ETAGE | OB124
Panneau de contreventement MFP | Rez de chaussée | OSB | 0.659 | 0.012 | 2.8 | 0.0949 | 3.7576 | 3.7734 | 0.0221 | 0.0221 | 0.1771 | 0.1771 | 0 | MURS RDC | OB022
Bardage | Premier Etage | Mélèze | 3.308 | 0.021 | 0.6979 | 1.4588 | 4.6465 | 4.7854 | 0.0485 | 0.0485 | 0.3566 | 0.3566 |  | MURS ETAGE | OB125
Panneau de contreventement MFP | Rez de chaussée | OSB | 1.196 | 0.012 | 2.58 | 0.1722 | 6.2333 | 6.262 | 0.037 | 0.037 | 0.2962 | 0.2962 | 0 | MURS RDC | OB026
Bardage | Premier Etage | Mélèze | 1.4615 | 0.021 | 1.0222 | 0.6445 | 2.2269 | 2.2883 | 0.0314 | 0.023 | 0.2308 | 0.1693 |  | MURS ETAGE | OB19
Panneau de contreventement MFP | Rez de chaussée | OSB | 1.196 | 0.012 | 2.8 | 0.1722 | 2.4185 | 2.4472 | 0.0402 | 0.0138 | 0.3215 | 0.1103 | 0 | MURS RDC | OB023
Panneau de contreventement MFP | Rez de chaussée | OSB | 1.196 | 0.012 | 2.8 | 0.1722 | 6.7648 | 6.7935 | 0.0402 | 0.0402 | 0.3215 | 0.3215 | 0 | MURS RDC | OB011
Panneau de contreventement MFP | Rez de chaussée | OSB | 0.8055 | 0.012 | 2.73 | 0.116 | 4.4635 | 4.4829 | 0.0264 | 0.0264 | 0.2111 | 0.2111 | 0 | MURS RDC | OB06
Panneau de contreventement MFP | Rez de chaussée | OSB | 0.345 | 0.012 | 2.73 | 0.0497 | 1.6617 | 1.67 | 0.0113 | 0.0096 | 0.0904 | 0.0765 | 0 | MURS RDC | OB07
Panneau de contreventement MFP | Premier Etage | OSB | 0.8634 | 0.012 | 0.7245 | 0.1243 | 0.6374 | 0.6582 | 0.0075 | 0.0038 | 0.0601 | 0.03 | 0 | MURS COMBLE | OB12
Panneau de contreventement MFP | Rez de chaussée | OSB | 0.2915 | 0.012 | 2.73 | 0.042 | 1.5884 | 1.5953 | 0.0095 | 0.0091 | 0.0764 | 0.0731 | 0 | MURS RDC | OB09
Bardage | Premier Etage | Mélèze | 6.7211 | 0.021 | 2.7705 | 2.964 | 17.8197 | 18.102 | 0.391 | 0.1845 | 2.8761 | 1.3572 |  | MURS ETAGE | OB127
Panneau de contreventement MFP | Rez de chaussée | OSB | 1.196 | 0.012 | 2.608 | 0.1722 | 4.4318 | 4.4605 | 0.0374 | 0.0262 | 0.2994 | 0.2097 | 0 | MURS RDC | OB021
Bardage | Premier Etage | Mélèze | 3.448 | 0.021 | 2.7705 | 1.5206 | 13.7271 | 13.872 | 0.2006 | 0.1417 | 1.4754 | 1.042 |  | MURS ETAGE | OB12
Panneau de contreventement MFP | Rez de chaussée | OSB | 1.196 | 0.012 | 0.503 | 0.1722 | 1.2152 | 1.244 | 0.0072 | 0.0072 | 0.0578 | 0.0578 | 0 | MURS RDC | OB02
Bardage | Premier Etage | Mélèze | 3.9387 | 0.021 | 1.5959 | 1.737 | 6.4455 | 6.6109 | 0.132 | 0.0673 | 0.9709 | 0.4947 |  | MURS COMBLE | OB127
Panneau de contreventement MFP | Rez de chaussée | OSB | 1.196 | 0.012 | 2.73 | 0.1722 | 6.5309 | 6.5596 | 0.0392 | 0.0388 | 0.3134 | 0.3103 | 0 | MURS RDC | OB015
Panneau de contreventement MFP | Rez de chaussée | OSB | 1.196 | 0.012 | 2.73 | 0.1722 | 5.376 | 5.4047 | 0.0392 | 0.0318 | 0.3134 | 0.2542 | 0 | MURS RDC | OB015
2 x Panneau de contreventement MFP | Rez de chaussée | OSB | 1.196 | 0.012 | 2.73 | 0.1722 | 6.5957 | 6.6244 | 0.0392 | 0.0392 | 0.3134 | 0.3134 | 0 | MURS RDC | OB015
Bardage | Rez de chaussée | Mélèze | 3.448 | 0.021 | 2.793 | 1.5206 | 15.5352 | 15.68 | 0.2022 | 0.1606 | 1.4874 | 1.1814 |  | MURS RDC | OB02
Panneau de contreventement MFP | Premier Etage | OSB | 1.1811 | 0.012 | 2.8 | 0.1701 | 6.6691 | 6.6975 | 0.0397 | 0.0396 | 0.3175 | 0.3169 | 0 | MURS ETAGE | OB123
Panneau de contreventement MFP | Premier Etage | OSB | 1.196 | 0.012 | 2.8 | 0.1722 | 5.3389 | 5.3676 | 0.0402 | 0.0316 | 0.3215 | 0.2531 | 0 | MURS ETAGE | OB131
Panneau de contreventement MFP | Premier Etage | OSB | 1.196 | 0.012 | 2.8 | 0.1722 | 3.0762 | 3.1049 | 0.0402 | 0.0177 | 0.3215 | 0.1419 | 0 | MURS ETAGE | OB130
Bardage | Premier Etage | Mélèze | 0.6304 | 0.021 | 1.1678 | 0.278 | 1.5214 | 1.5479 | 0.0155 | 0.0155 | 0.1137 | 0.1137 |  | MURS ETAGE | OB15
Panneau de contreventement MFP | Comble et couverture | OSB | 1.196 | 0.012 | 1.5262 | 0.1722 | 2.7681 | 2.7968 | 0.0219 | 0.0164 | 0.1752 | 0.1314 | 0 | MURS COMBLE | OB128
Panneau de contreventement MFP | Premier Etage | OSB | 0.684 | 0.012 | 1.2128 | 0.0985 | 1.6762 | 1.6927 | 0.01 | 0.0099 | 0.0796 | 0.0791 | 0 | MURS ETAGE | OB11
Panneau de contreventement MFP | Premier Etage | OSB | 1.196 | 0.012 | 1.2128 | 0.1722 | 2.9182 | 2.9469 | 0.0174 | 0.0173 | 0.1393 | 0.1387 | 0 | MURS ETAGE | OB11
Bardage | Rez de chaussée | Mélèze | 0.6304 | 0.021 | 2.793 | 0.278 | 3.6352 | 3.6616 | 0.037 | 0.0369 | 0.2719 | 0.2717 |  | MURS RDC | OB05
Panneau de contreventement MFP | Premier Etage | OSB | 0.86 | 0.012 | 2.3352 | 0.1238 | 3.3717 | 3.3924 | 0.0241 | 0.0199 | 0.1928 | 0.1593 | 0 | MURS ETAGE | OB14
Bardage | Rez de chaussée | Mélèze | 4.6498 | 0.021 | 2.765 | 2.0506 | 24.6085 | 24.8038 | 0.27 | 0.2564 | 1.9858 | 1.8861 |  | MURS RDC | OB015
Bardage | Premier Etage | Mélèze | 0.021 | 3.2575 | 2.7705 | 222.837 | 11.649 | 11.7858 | 0.1895 | 0.1191 | 1.3939 | 0.8759 |  | MURS ETAGE | OB14
Panneau de contreventement MFP | Premier Etage | OSB | 1.196 | 0.012 | 2.8 | 0.1722 | 3.5161 | 3.5448 | 0.0402 | 0.0207 | 0.3215 | 0.1658 | 0 | MURS ETAGE | OB131
Panneau de contreventement MFP | Premier Etage | OSB | 1.196 | 0.012 | 2.7705 | 0.1722 | 6.6857 | 6.7144 | 0.0398 | 0.0397 | 0.3181 | 0.3177 | 0 | MURS ETAGE | OB127
Panneau de contreventement MFP | Rez de chaussée | OSB | 1.196 | 0.012 | 1.047 | 0.1722 | 2.5296 | 2.5583 | 0.015 | 0.015 | 0.1202 | 0.1202 | 0 | MURS RDC | OB02
Panneau de contreventement MFP | Rez de chaussée | OSB | 0.4186 | 0.012 | 2.58 | 0.0603 | 2.222 | 2.232 | 0.013 | 0.013 | 0.1037 | 0.1037 | 0 | MURS RDC | OB024
Panneau de contreventement MFP | Premier Etage | OSB | 1.1728 | 0.012 | 0.9366 | 0.1689 | 2.1437 | 2.1719 | 0.0132 | 0.0127 | 0.1055 | 0.1017 | 0 | MURS ETAGE | OB15
Panneau de contreventement MFP | Rez de chaussée | OSB | 0.4267 | 0.012 | 2.73 | 0.0614 | 2.3388 | 2.349 | 0.014 | 0.0136 | 0.1118 | 0.1091 | 0 | MURS RDC | OB027
Bardage | Rez de chaussée | Mélèze | 1.0038 | 0.021 | 2.793 | 0.4427 | 5.6776 | 5.7198 | 0.0589 | 0.0584 | 0.433 | 0.4294 |  | MURS RDC | OB03
Panneau de contreventement MFP | Premier Etage | OSB | 1.196 | 0.012 | 2.1093 | 0.1722 | 4.2642 | 4.2929 | 0.0303 | 0.0253 | 0.2422 | 0.2025 | 0 | MURS ETAGE | OB131
Bardage | Premier Etage | Mélèze | 4.6498 | 0.021 | 1.1761 | 2.0506 | 10.9862 | 11.1815 | 0.1148 | 0.1148 | 0.8446 | 0.8446 |  | MURS ETAGE | OB123
Bardage | Premier Etage | Mélèze | 7.924 | 0.021 | 1.2078 | 3.4945 | 19.1922 | 19.525 | 0.201 | 0.201 | 1.4782 | 1.4782 |  | MURS ETAGE | OB11
Panneau de contreventement MFP | Premier Etage | OSB | 0.703 | 0.012 | 2.6893 | 0.1012 | 1.086 | 1.1029 | 0.0227 | 0.0061 | 0.1815 | 0.049 | 0 | MURS ETAGE | OB128
Panneau de contreventement MFP | Premier Etage | OSB | 1.196 | 0.012 | 2.7705 | 0.1722 | 5.4242 | 5.453 | 0.0398 | 0.032 | 0.3181 | 0.2557 | 0 | MURS ETAGE | OB127
Panneau de contreventement MFP | Premier Etage | OSB | 1.196 | 0.012 | 2.7705 | 0.1722 | 6.6352 | 6.6639 | 0.0398 | 0.0394 | 0.3181 | 0.3149 | 0 | MURS ETAGE | OB127
Panneau de contreventement MFP | Rez de chaussée | OSB | 1.196 | 0.012 | 2.8 | 0.1722 | 6.7648 | 6.7935 | 0.0402 | 0.0402 | 0.3215 | 0.3215 | 0 | MURS RDC | OB023
Panneau de contreventement MFP | Premier Etage | OSB | 0.3447 | 0.012 | 0.2892 | 0.0496 | 0.1044 | 0.1127 | 0.0012 | 0.0006 | 0.0096 | 0.0048 | 0 | MURS COMBLE | OB127
Panneau de contreventement MFP | Rez de chaussée | OSB | 1.196 | 0.012 | 2.8 | 0.1722 | 3.1432 | 3.1719 | 0.0402 | 0.0183 | 0.3215 | 0.1467 | 0 | MURS RDC | OB08
Panneau de contreventement MFP | Rez de chaussée | OSB | 1.196 | 0.012 | 2.8 | 0.1722 | 3.5283 | 3.557 | 0.0402 | 0.0207 | 0.3215 | 0.1652 | 0 | MURS RDC | OB08
Bardage | Rez de chaussée | Mélèze | 1.4933 | 0.021 | 2.765 | 0.6585 | 4.5388 | 4.6015 | 0.0867 | 0.0451 | 0.6377 | 0.3317 |  | MURS RDC | OB07
Panneau de contreventement MFP | Rez de chaussée | OSB | 0.1651 | 0.012 | 2.8 | 0.0238 | 0.9919 | 0.9959 | 0.0055 | 0.0055 | 0.0444 | 0.0444 | 0 | MURS RDC | OB023
Panneau de contreventement MFP | Premier Etage | OSB | 1.196 | 0.012 | 1.8531 | 0.1722 | 1.837 | 1.8657 | 0.0266 | 0.0106 | 0.2128 | 0.0848 | 0 | MURS ETAGE | OB122
Panneau de contreventement MFP | Premier Etage | OSB | 0.7802 | 0.012 | 1.9975 | 0.1123 | 2.7699 | 2.7886 | 0.0187 | 0.0163 | 0.1496 | 0.1308 | 0 | MURS ETAGE | OB120
Panneau de contreventement MFP | Rez de chaussée | OSB | 0.0835 | 0.012 | 2.56 | 0.012 | 0.4891 | 0.4911 | 0.0026 | 0.0026 | 0.0205 | 0.0205 | 0 | MURS RDC | OB025
Panneau de contreventement MFP | Premier Etage | OSB | 0.7029 | 0.012 | 0.504 | 0.1012 | 0.7086 | 0.7255 | 0.0043 | 0.0042 | 0.034 | 0.0334 | 0 | MURS ETAGE | OB125
Panneau de contreventement MFP | Rez de chaussée | OSB | 0.9225 | 0.012 | 0.171 | 0.1328 | 0.3196 | 0.3417 | 0.0019 | 0.0019 | 0.0151 | 0.0151 | 0 | MURS RDC | OB011
Panneau de contreventement MFP | Premier Etage | OSB | 1.196 | 0.012 | 2.6173 | 0.1722 | 4.7023 | 4.731 | 0.0376 | 0.0278 | 0.3005 | 0.2227 | 0 | MURS ETAGE | OB12
Panneau de contreventement MFP | Rez de chaussée | OSB | 1.196 | 0.012 | 2.758 | 0.1722 | 6.5885 | 6.6172 | 0.0396 | 0.0391 | 0.3167 | 0.3131 | 0 | MURS RDC | OB03
surf_placo | Rez de chaussée | NH II | 0 | 1.9838 | 2.8 | 0 | 4.4615 | 4.4615 | 0 | 0.0045 | 0 | 0 |  | MURS RDC
Panneau de contreventement MFP | Premier Etage | OSB | 0.8162 | 0.012 | 1.5471 | 0.1175 | 2.1404 | 2.16 | 0.0152 | 0.0126 | 0.1212 | 0.1011 | 0 | MURS ETAGE | OB124
Panneau de contreventement MFP | Rez de chaussée | OSB | 0.1958 | 0.012 | 2.73 | 0.0282 | 1.1346 | 1.1393 | 0.0064 | 0.0064 | 0.0513 | 0.0513 | 0 | MURS RDC | OB015
Panneau de contreventement MFP | Premier Etage | OSB | 0.8162 | 0.012 | 1.5471 | 0.1175 | 2.1404 | 2.16 | 0.0152 | 0.0126 | 0.1212 | 0.1011 | 0 | MURS ETAGE | OB126
Panneau de contreventement MFP | Rez de chaussée | OSB | 0.9386 | 0.012 | 2.758 | 0.1352 | 5.1583 | 5.1809 | 0.0311 | 0.0306 | 0.2485 | 0.2444 | 0 | MURS RDC | OB05
Bardage | Rez de chaussée | Mélèze | 0.021 | 3.2575 | 2.793 | 222.837 | 11.8326 | 11.9694 | 0.1911 | 0.1213 | 1.4053 | 0.8923 |  | MURS RDC | OB04
Panneau de contreventement MFP | Rez de chaussée | OSB | 0.2107 | 0.012 | 2.58 | 0.0303 | 1.1489 | 1.154 | 0.0065 | 0.0065 | 0.0522 | 0.0522 | 0 | MURS RDC | OB026
Bardage | Premier Etage | Mélèze | 5.5652 | 0.021 | 2.9293 | 2.4543 | 12.8109 | 13.0446 | 0.3423 | 0.1334 | 2.5179 | 0.9811 |  | MURS ETAGE | OB120
Panneau de contreventement MFP | Premier Etage | OSB | 0.291 | 0.012 | 2.3722 | 0.0419 | 1.3872 | 1.3942 | 0.0083 | 0.008 | 0.0663 | 0.0639 | 0 | MURS ETAGE | OB131
Bardage | Rez de chaussée | Mélèze | 0.8095 | 0.021 | 2.765 | 0.357 | 4.5927 | 4.6267 | 0.047 | 0.047 | 0.3457 | 0.3457 |  | MURS RDC | OB010
Panneau de contreventement MFP | Premier Etage | OSB | 1.048 | 0.012 | 2.7705 | 0.1509 | 5.349 | 5.3742 | 0.0348 | 0.0317 | 0.2787 | 0.2533 | 0 | MURS ETAGE | OB12
Panneau de contreventement MFP | Premier Etage | OSB | 1.196 | 0.012 | 0.653 | 0.1722 | 1.5776 | 1.6064 | 0.0094 | 0.0094 | 0.075 | 0.075 | 0 | MURS ETAGE | OB12
Bardage | Premier Etage | Mélèze | 1.0038 | 0.021 | 2.7705 | 0.4427 | 5.6785 | 5.7207 | 0.0584 | 0.0584 | 0.4296 | 0.4296 |  | MURS ETAGE | OB13
3 x Panneau de contreventement MFP | Rez de chaussée | OSB | 1.196 | 0.012 | 0.171 | 0.1722 | 0.4131 | 0.4418 | 0.0025 | 0.0025 | 0.0196 | 0.0196 | 0 | MURS RDC | OB011
Panneau de contreventement MFP | Premier Etage | OSB | 1.196 | 0.012 | 2.7705 | 0.1722 | 5.3149 | 5.3436 | 0.0398 | 0.0315 | 0.3181 | 0.2519 | 0 | MURS ETAGE | OB129
Panneau de contreventement MFP | Premier Etage | OSB | 1.196 | 0.012 | 2.7611 | 0.1722 | 6.5714 | 6.6001 | 0.0396 | 0.039 | 0.317 | 0.3117 | 0 | MURS ETAGE | OB120
Bardage | Rez de chaussée | Mélèze | 1.4615 | 0.021 | 2.765 | 0.6445 | 4.3632 | 4.4246 | 0.0849 | 0.0433 | 0.6242 | 0.3181 |  | MURS RDC | OB09
Panneau de contreventement MFP | Premier Etage | OSB | 0.3947 | 0.012 | 0.1642 | 0.0568 | 0.1141 | 0.1236 | 0.0008 | 0.0007 | 0.0062 | 0.0053 | 0 | MURS ETAGE | OB120
Panneau de contreventement MFP | Premier Etage | OSB | 0.8245 | 0.012 | 1.9236 | 0.1187 | 2.858 | 2.8778 | 0.019 | 0.0169 | 0.1523 | 0.1352 | 0 | MURS ETAGE | OB130
Panneau de contreventement MFP | Rez de chaussée | OSB | 0.171 | 0.012 | 2.5416 | 0.0246 | 0.9302 | 0.9343 | 0.0052 | 0.0052 | 0.0417 | 0.0417 | 0 | MURS RDC | OB014
Panneau de contreventement MFP | Rez de chaussée | OSB | 1.196 | 0.012 | 2.8 | 0.1722 | 4.4349 | 4.4636 | 0.0402 | 0.026 | 0.3215 | 0.2083 | 0 | MURS RDC | OB017
Panneau de contreventement MFP | Premier Etage | OSB | 0.6753 | 0.012 | 0.5666 | 0.0972 | 0.3919 | 0.4081 | 0.0046 | 0.0023 | 0.0367 | 0.0184 | 0 | MURS COMBLE | OB14
Bardage | Premier Etage | Mélèze | 0.021 | 1.8728 | 1.5715 | 73.6539 | 2.988 | 3.0667 | 0.0618 | 0.0309 | 0.4546 | 0.2273 |  | MURS COMBLE | OB14
Panneau de contreventement MFP | Premier Etage | OSB | 1.0486 | 0.012 | 2.0055 | 0.151 | 4.2302 | 4.2554 | 0.0252 | 0.0251 | 0.2019 | 0.2007 | 0 | MURS ETAGE | OB16
Panneau de contreventement MFP | Comble et couverture | OSB | 1.196 | 0.012 | 1.245 | 0.1722 | 3.0079 | 3.0366 | 0.0179 | 0.0179 | 0.1429 | 0.1429 | 0 | MURS COMBLE | OB13
Bardage | Comble et couverture | Mélèze | 1.0038 | 0.021 | 1.3669 | 0.4427 | 2.8017 | 2.8438 | 0.0288 | 0.0288 | 0.2119 | 0.2119 |  | MURS COMBLE | OB13
Panneau de contreventement MFP | Premier Etage | OSB | 1.0539 | 0.012 | 1.8531 | 0.1518 | 1.6914 | 1.7167 | 0.0234 | 0.0097 | 0.1875 | 0.078 | 0 | MURS ETAGE | OB121
2 x surf_placo | Rez de chaussée | NH II | 0 | 0.4966 | 2.8 | 0 | 1.3906 | 1.3906 | 0 | 0.0014 | 0 | 0 |  | MURS RDC
2 x surf_placo | Rez de chaussée | NH II | 0 | 0.6579 | 2.8 | 0 | 1.8422 | 1.8422 | 0 | 0.0018 | 0 | 0 |  | MURS RDC
Bardage | Premier Etage | Mélèze | 2.0634 | 0.021 | 1.5368 | 0.91 | 3.4772 | 3.5639 | 0.0666 | 0.036 | 0.4898 | 0.2651 |  | MURS COMBLE | OB12
Panneau de contreventement MFP | Premier Etage | OSB | 1.196 | 0.012 | 2.1306 | 0.1722 | 4.2552 | 4.2839 | 0.0306 | 0.0252 | 0.2446 | 0.202 | 0 | MURS ETAGE | OB120
Panneau de contreventement MFP | Premier Etage | OSB | 1.196 | 0.012 | 1.5368 | 0.1722 | 2.8325 | 2.8612 | 0.0221 | 0.0168 | 0.1764 | 0.1345 | 0 | MURS COMBLE | OB12
3 x Panneau de contreventement MFP | Rez de chaussée | OSB | 1.196 | 0.012 | 2.608 | 0.1722 | 6.3009 | 6.3296 | 0.0374 | 0.0374 | 0.2994 | 0.2994 | 0 | MURS RDC | OB021
Panneau de contreventement MFP | Rez de chaussée | OSB | 0.3432 | 0.012 | 2.608 | 0.0494 | 1.8526 | 1.8608 | 0.0107 | 0.0107 | 0.0859 | 0.0859 | 0 | MURS RDC | OB021
Panneau de contreventement MFP | Rez de chaussée | OSB | 1.196 | 0.012 | 2.608 | 0.1722 | 3.644 | 3.6727 | 0.0374 | 0.0215 | 0.2994 | 0.1719 | 0 | MURS RDC | OB021
2 x Panneau de contreventement MFP | Rez de chaussée | OSB | 1.196 | 0.012 | 2.56 | 0.1722 | 6.185 | 6.2137 | 0.0367 | 0.0367 | 0.2939 | 0.2939 | 0 | MURS RDC | OB025
Panneau de contreventement MFP | Rez de chaussée | OSB | 1.196 | 0.012 | 2.758 | 0.1722 | 5.9649 | 5.9936 | 0.0396 | 0.0353 | 0.3167 | 0.2828 | 0 | MURS RDC | OB02
Panneau de contreventement MFP | Rez de chaussée | OSB | 1.048 | 0.012 | 2.758 | 0.1509 | 5.4329 | 5.4581 | 0.0347 | 0.0322 | 0.2775 | 0.2574 | 0 | MURS RDC | OB02
Bardage | Premier Etage | Mélèze | 5.3815 | 0.021 | 2.2578 | 2.3732 | 12.0308 | 12.2568 | 0.2552 | 0.1255 | 1.8767 | 0.9227 |  | MURS ETAGE | OB127
Bardage | Premier Etage | Mélèze | 2.2408 | 0.021 | 1.846 | 0.9882 | 3.0244 | 3.1185 | 0.0869 | 0.0299 | 0.6389 | 0.2202 |  | MURS ETAGE | OB121
Panneau de contreventement MFP | Premier Etage | OSB | 0.4998 | 0.012 | 0.1642 | 0.072 | 0.12 | 0.132 | 0.001 | 0.0007 | 0.0079 | 0.0056 | 0 | MURS ETAGE | OB120
Panneau de contreventement MFP | Rez de chaussée | OSB | 1.196 | 0.012 | 2.8 | 0.1722 | 6.4625 | 6.4912 | 0.0402 | 0.0384 | 0.3215 | 0.307 | 0 | MURS RDC | OB023
Panneau de contreventement MFP | Premier Etage | OSB | 1.0331 | 0.012 | 1.4915 | 0.1488 | 2.2859 | 2.3107 | 0.0185 | 0.0135 | 0.1479 | 0.1083 | 0 | MURS ETAGE | OB19
Panneau de contreventement MFP | Premier Etage | OSB | 0.7411 | 0.012 | 2.2356 | 0.1067 | 2.8611 | 2.8789 | 0.0199 | 0.0169 | 0.1591 | 0.1349 | 0 | MURS ETAGE | OB127
surf_placo | Rez de chaussée | NH II | 0 | 1.9838 | 2.8 | 0 | 5.5546 | 5.5546 | 0 | 0.0056 | 0 | 0 |  | MURS RDC
Panneau de contreventement MFP | Premier Etage | OSB | 1.196 | 0.012 | 2.5893 | 0.1722 | 4.9452 | 4.9739 | 0.0372 | 0.0293 | 0.2973 | 0.2346 | 0 | MURS ETAGE | OB127
Panneau de contreventement MFP | Premier Etage | OSB | 1.196 | 0.012 | 2.6893 | 0.1722 | 6.4825 | 6.5112 | 0.0386 | 0.0385 | 0.3088 | 0.3081 | 0 | MURS ETAGE | OB128
Panneau de contreventement MFP | Premier Etage | OSB | 1.196 | 0.012 | 2.7705 | 0.1722 | 5.7223 | 5.751 | 0.0398 | 0.0337 | 0.3181 | 0.2695 | 0 | MURS ETAGE | OB127
Panneau de contreventement MFP | Premier Etage | OSB | 0.1188 | 0.012 | 2.7305 | 0.0171 | 0.7144 | 0.7173 | 0.0039 | 0.0039 | 0.0311 | 0.0311 | 0 | MURS ETAGE | OB13
surf_placo | Rez de chaussée | NH II | 0 | 0.108 | 2.8 | 0 | 0.3024 | 0.3024 | 0 | 0.0003 | 0 | 0 |  | MURS RDC
Bardage | Rez de chaussée | Mélèze | 3.308 | 0.021 | 2.835 | 1.4588 | 16.0752 | 16.2141 | 0.1969 | 0.1665 | 1.4485 | 1.2243 |  | MURS RDC | OB017
Panneau de contreventement MFP | Rez de chaussée | OSB | 1.196 | 0.012 | 2.58 | 0.1722 | 6.2333 | 6.262 | 0.037 | 0.037 | 0.2962 | 0.2962 | 0 | MURS RDC | OB024
Panneau de contreventement MFP | Rez de chaussée | OSB | 1.196 | 0.012 | 2.58 | 0.1722 | 6.1685 | 6.1972 | 0.037 | 0.0366 | 0.2962 | 0.2931 | 0 | MURS RDC | OB026
Panneau de contreventement MFP | Premier Etage | OSB | 1.196 | 0.012 | 2.7705 | 0.1722 | 4.5679 | 4.5966 | 0.0398 | 0.027 | 0.3181 | 0.216 | 0 | MURS ETAGE | OB129
Bardage | Premier Etage | Mélèze | 2.4626 | 0.021 | 0.5086 | 1.086 | 2.5266 | 2.63 | 0.0263 | 0.0263 | 0.1935 | 0.1935 |  | MURS ETAGE | OB18
Panneau de contreventement MFP | Premier Etage | OSB | 0.3432 | 0.012 | 2.7705 | 0.0494 | 1.968 | 1.9762 | 0.0114 | 0.0114 | 0.0913 | 0.0913 | 0 | MURS ETAGE | OB129
Panneau de contreventement MFP | Premier Etage | OSB | 1.196 | 0.012 | 2.7705 | 0.1722 | 3.2359 | 3.2646 | 0.0398 | 0.0187 | 0.3181 | 0.1495 | 0 | MURS ETAGE | OB129
Panneau de contreventement MFP | Rez de chaussée | OSB | 1.196 | 0.012 | 2.8 | 0.1722 | 3.4144 | 3.4431 | 0.0402 | 0.0199 | 0.3215 | 0.1595 | 0 | MURS RDC | OB011
Panneau de contreventement MFP | Comble et couverture | OSB | 0.3247 | 0.012 | 0.6478 | 0.0468 | 0.331 | 0.3388 | 0.0025 | 0.0019 | 0.0202 | 0.0152 | 0 | MURS COMBLE | OB128
2 x Panneau de contreventement MFP | Premier Etage | OSB | 1.1811 | 0.012 | 2.8 | 0.1701 | 6.6645 | 6.6928 | 0.0397 | 0.0396 | 0.3175 | 0.3166 | 0 | MURS ETAGE | OB123
Panneau de contreventement MFP | Premier Etage | OSB | 1.196 | 0.012 | 1.3452 | 0.1722 | 2.0142 | 2.0429 | 0.0193 | 0.0119 | 0.1545 | 0.0956 | 0 | MURS ETAGE | OB12
Panneau de contreventement MFP | Premier Etage | OSB | 1.196 | 0.012 | 2.5515 | 0.1722 | 5.4103 | 5.439 | 0.0366 | 0.0321 | 0.293 | 0.257 | 0 | MURS ETAGE | OB130
Panneau de contreventement MFP | Premier Etage | OSB | 1.196 | 0.012 | 1.9969 | 0.1722 | 4.0704 | 4.0991 | 0.0287 | 0.0242 | 0.2293 | 0.1934 | 0 | MURS ETAGE | OB130
Bardage | Rez de chaussée | Mélèze | 0.021 | 0.8112 | 2.835 | 13.8196 | 4.7187 | 4.7527 | 0.0483 | 0.0483 | 0.3552 | 0.3552 |  | MURS RDC | OB016
Panneau de contreventement MFP | Rez de chaussée | OSB | 0.908 | 0.012 | 2.8 | 0.1308 | 5.152 | 5.1738 | 0.0305 | 0.0305 | 0.2441 | 0.2441 | 0 | MURS RDC | OB017
Bardage | Rez de chaussée | Mélèze | 0.8112 | 0.021 | 2.835 | 0.3577 | 4.7187 | 4.7527 | 0.0483 | 0.0483 | 0.3552 | 0.3552 |  | MURS RDC | OB018
Panneau de contreventement MFP | Premier Etage | OSB | 1.0486 | 0.012 | 1.545 | 0.151 | 2.402 | 2.4272 | 0.0194 | 0.0142 | 0.1555 | 0.1138 | 0 | MURS ETAGE | OB17
Panneau de contreventement MFP | Rez de chaussée | OSB | 0.8162 | 0.012 | 2.8 | 0.1175 | 4.638 | 4.6576 | 0.0274 | 0.0274 | 0.2194 | 0.2194 | 0 | MURS RDC | OB018
Panneau de contreventement MFP | Premier Etage | OSB | 1.196 | 0.012 | 2.6893 | 0.1722 | 5.7635 | 5.7922 | 0.0386 | 0.0342 | 0.3088 | 0.2736 | 0 | MURS ETAGE | OB128
Panneau de contreventement MFP | Premier Etage | OSB | 1.196 | 0.012 | 2.7705 | 0.1722 | 4.8368 | 4.8655 | 0.0398 | 0.0285 | 0.3181 | 0.2276 | 0 | MURS ETAGE | OB14
Bardage | Premier Etage | Mélèze | 1.8362 | 0.021 | 1.0436 | 0.8098 | 3.8765 | 3.9536 | 0.0402 | 0.0402 | 0.296 | 0.296 |  | MURS ETAGE | OB16
surf_placo | Rez de chaussée | NH II | 0 | 2.4724 | 1.052 | 0 | 2.6009 | 2.6009 | 0 | 0.0026 | 0 | 0 |  | MURS RDC
surf_placo | Rez de chaussée | NH II | 0 | 1.0324 | 1.748 | 0 | 1.8046 | 1.8046 | 0 | 0.0018 | 0 | 0 |  | MURS RDC
surf_placo | Rez de chaussée | NH II | 0 | 1.44 | 0.322 | 0 | 0.4637 | 0.4637 | 0 | 0.0005 | 0 | 0 |  | MURS RDC
Bardage | Premier Etage | Mélèze | 1.4933 | 0.021 | 1.0322 | 0.6585 | 2.2872 | 2.3499 | 0.0324 | 0.0236 | 0.2381 | 0.1739 |  | MURS ETAGE | OB17
Panneau de contreventement MFP | Premier Etage | OSB | 0.5136 | 0.012 | 2.4876 | 0.074 | 2.5913 | 2.6036 | 0.0153 | 0.0152 | 0.1227 | 0.1215 | 0 | MURS ETAGE | OB18
2 x Panneau de contreventement MFP | Rez de chaussée | OSB | 1.196 | 0.012 | 2.758 | 0.1722 | 6.6026 | 6.6313 | 0.0396 | 0.0392 | 0.3167 | 0.3133 | 0 | MURS RDC | OB020
Bardage | Rez de chaussée | Mélèze | 2.4626 | 0.021 | 2.835 | 1.086 | 7.3254 | 7.4288 | 0.1466 | 0.074 | 1.0783 | 0.5444 |  | MURS RDC | OB08
Panneau de contreventement MFP | Rez de chaussée | OSB | 1.196 | 0.012 | 2.8 | 0.1722 | 6.7648 | 6.7935 | 0.0402 | 0.0402 | 0.3215 | 0.3215 | 0 | MURS RDC | OB022
Bardage | Rez de chaussée | Mélèze | 2.5016 | 0.021 | 3.005 | 1.1032 | 15.1608 | 15.2659 | 0.1579 | 0.1579 | 1.1611 | 1.1611 |  | MURS RDC | OB014
Panneau de contreventement MFP | Rez de chaussée | OSB | 1.196 | 0.012 | 2.8 | 0.1722 | 2.4185 | 2.4472 | 0.0402 | 0.0138 | 0.3215 | 0.1103 | 0 | MURS RDC | OB022
Bardage | Rez de chaussée | Mélèze | 4.4725 | 0.021 | 3.005 | 1.9724 | 22.8937 | 23.0816 | 0.2822 | 0.2378 | 2.0758 | 1.7487 |  | MURS RDC | OB011
Bardage | Rez de chaussée | Mélèze | 2.2408 | 0.021 | 2.74 | 0.9882 | 5.1831 | 5.2772 | 0.1289 | 0.0515 | 0.9483 | 0.3789 |  | MURS RDC | OB012
Bardage | Rez de chaussée | Mélèze | 2.2408 | 0.021 | 2.74 | 0.9882 | 5.1831 | 5.2772 | 0.1289 | 0.0515 | 0.9483 | 0.3789 |  | MURS RDC | OB013
Panneau de contreventement MFP | Rez de chaussée | OSB | 1.196 | 0.012 | 2.705 | 0.1722 | 2.5068 | 2.5355 | 0.0388 | 0.0145 | 0.3106 | 0.1161 | 0 | MURS RDC | OB013
Panneau de contreventement MFP | Rez de chaussée | OSB | 0.1416 | 0.012 | 2.8 | 0.0204 | 0.8601 | 0.8635 | 0.0048 | 0.0048 | 0.0381 | 0.0381 | 0 | MURS RDC | OB014
Panneau de contreventement MFP | Premier Etage | OSB | 1.196 | 0.012 | 1.2791 | 0.1722 | 1.3028 | 1.3315 | 0.0184 | 0.0076 | 0.1469 | 0.0604 | 0 | MURS ETAGE | OB121
Panneau de contreventement MFP | Rez de chaussée | OSB | 0.2236 | 0.012 | 2.73 | 0.0322 | 1.2866 | 1.292 | 0.0073 | 0.0073 | 0.0586 | 0.0586 | 0 | MURS RDC | OB010
Panneau de contreventement MFP | Premier Etage | OSB | 1.196 | 0.012 | 1.5736 | 0.1722 | 2.5938 | 2.6225 | 0.0226 | 0.0154 | 0.1807 | 0.1231 | 0 | MURS COMBLE | OB14
Panneau de contreventement MFP | Premier Etage | OSB | 1.0539 | 0.012 | 1.2021 | 0.1518 | 1.1572 | 1.1825 | 0.0152 | 0.0067 | 0.1216 | 0.0536 | 0 | MURS ETAGE | OB122
Bardage | Premier Etage | Mélèze | 2.2408 | 0.021 | 1.846 | 0.9882 | 3.0244 | 3.1185 | 0.0869 | 0.0299 | 0.6389 | 0.2202 |  | MURS ETAGE | OB122
2 x Panneau de contreventement MFP | Rez de chaussée | OSB | 1.196 | 0.012 | 2.8 | 0.1722 | 6.7648 | 6.7935 | 0.0402 | 0.0402 | 0.3215 | 0.3215 | 0 | MURS RDC | OB014
Bardage | Rez de chaussée | Mélèze | 1.8362 | 0.021 | 2.765 | 0.8098 | 10.2703 | 10.3474 | 0.1066 | 0.1066 | 0.7842 | 0.7842 |  | MURS RDC | OB06
Panneau de contreventement MFP | Rez de chaussée | OSB | 1.196 | 0.012 | 2.73 | 0.1722 | 6.5957 | 6.6244 | 0.0392 | 0.0392 | 0.3134 | 0.3134 | 0 | MURS RDC | OB06
Panneau de contreventement MFP | Rez de chaussée | OSB | 1.196 | 0.012 | 2.73 | 0.1722 | 2.9595 | 2.9882 | 0.0392 | 0.0172 | 0.3134 | 0.1379 | 0 | MURS RDC | OB07
Panneau de contreventement MFP | Rez de chaussée | OSB | 1.196 | 0.012 | 2.73 | 0.1722 | 2.7408 | 2.7695 | 0.0392 | 0.0159 | 0.3134 | 0.1274 | 0 | MURS RDC | OB09
Panneau de contreventement MFP | Premier Etage | OSB | 1.196 | 0.012 | 2.6903 | 0.1722 | 5.668 | 5.6967 | 0.0386 | 0.0337 | 0.3089 | 0.2693 | 0 | MURS ETAGE | OB120
Panneau de contreventement MFP | Rez de chaussée | OSB | 1.196 | 0.012 | 2.8 | 0.1722 | 6.2342 | 6.2629 | 0.0402 | 0.037 | 0.3215 | 0.2957 | 0 | MURS RDC | OB017
Panneau de contreventement MFP | Rez de chaussée | OSB | 1.196 | 0.012 | 2.73 | 0.1722 | 6.5201 | 6.5488 | 0.0392 | 0.0387 | 0.3134 | 0.3098 | 0 | MURS RDC | OB010
Panneau de contreventement MFP | Rez de chaussée | OSB | 1.196 | 0.012 | 2.8 | 0.1722 | 5.9227 | 5.9514 | 0.0402 | 0.0351 | 0.3215 | 0.2808 | 0 | MURS RDC | OB011
Panneau de contreventement MFP | Rez de chaussée | OSB | 1.0539 | 0.012 | 2.705 | 0.1518 | 2.3337 | 2.359 | 0.0342 | 0.0135 | 0.2737 | 0.108 | 0 | MURS RDC | OB012
Panneau de contreventement MFP | Premier Etage | OSB | 1.196 | 0.012 | 2.7705 | 0.1722 | 3.3614 | 3.3902 | 0.0398 | 0.0197 | 0.3181 | 0.1572 | 0 | MURS ETAGE | OB14
Panneau de contreventement MFP | Rez de chaussée | OSB | 1.196 | 0.012 | 2.73 | 0.1722 | 6.5771 | 6.6058 | 0.0392 | 0.0391 | 0.3134 | 0.3126 | 0 | MURS RDC | OB027
surf_placo | Rez de chaussée | NH II | 0 | 2.4724 | 2.8 | 0 | 6.9226 | 6.9226 | 0 | 0.0069 | 0 | 0 |  | MURS RDC
Surf balcon | Premier Etage | NH II | 1.1048 | 0.021 | 3.264 | 0.4872 | 7.3494 | 7.3958 | 0.0757 | 0.0757 | 0 | 0 |  | Balcon Etage
Panneau de contreventement MFP | Premier Etage | OSB | 1.196 | 0.012 | 2.8 | 0.1722 | 5.9881 | 6.0168 | 0.0402 | 0.0356 | 0.3215 | 0.2845 | 0 | MURS ETAGE | OB120
Panneau de contreventement MFP | Rez de chaussée | OSB | 0.3351 | 0.012 | 2.73 | 0.0483 | 1.8778 | 1.8858 | 0.011 | 0.0109 | 0.0878 | 0.087 | 0 | MURS RDC | OB019
Bardage | Premier Etage | Mélèze | 1.1871 | 0.021 | 1.1761 | 0.5235 | 2.8417 | 2.8915 | 0.0293 | 0.0293 | 0.2156 | 0.2156 |  | MURS ETAGE | OB123
Panneau de contreventement MFP | Comble et couverture | OSB | 0.1208 | 0.012 | 1.245 | 0.0174 | 0.3307 | 0.3336 | 0.0018 | 0.0018 | 0.0144 | 0.0144 | 0 | MURS COMBLE | OB13
Panneau de contreventement MFP | Premier Etage | OSB | 1.1811 | 0.012 | 0.9629 | 0.1701 | 2.2817 | 2.31 | 0.0136 | 0.0136 | 0.1092 | 0.1084 | 0 | MURS ETAGE | OB123

# IfcWall (6)
Material: NH II
BaseQuantities - Height: 0.108 m; GrossWeight: 0; NetWeight: 0
Name | In | Width (m) | Length (m) | CrossSectionArea (m2) | OuterfaceArea (m2) | TotalSurfaceArea (m2) | GrossVolume (m3) | NetVolume (m3) | Group
Surf_cloison | Rez de chaussée | 3.059 | 2.635 | 35.6802 | 16.6901 | 17.3508 | 0.8705 | 0.8705 | MURS RDC
Surf_cloison | Rez de chaussée | 2.0288 | 2.635 | 23.6637 | 11.2608 | 11.6991 | 0.5774 | 0.5774 | MURS RDC
Surf_cloison | Premier Etage | 0.9101 | 3.8621 | 10.6151 | 7.1164 | 7.313 | 0.3796 | 0.3421 | MURS ETAGE
Surf_cloison | Rez de chaussée | 3.103 | 2.635 | 36.1934 | 16.922 | 17.5922 | 0.8831 | 0.8831 | MURS RDC
Surf_cloison | Rez de chaussée | 1.9638 | 2.635 | 22.906 | 10.9185 | 11.3427 | 0.5589 | 0.5589 | MURS RDC
Surf_cloison | Rez de chaussée | 0.6579 | 2.635 | 7.6741 | 4.0365 | 4.1786 | 0.1872 | 0.1872 | MURS RDC
